VERSION 5.7 ;
  NOWIREEXTENSIONATPIN ON ;
  DIVIDERCHAR "/" ;
  BUSBITCHARS "[]" ;
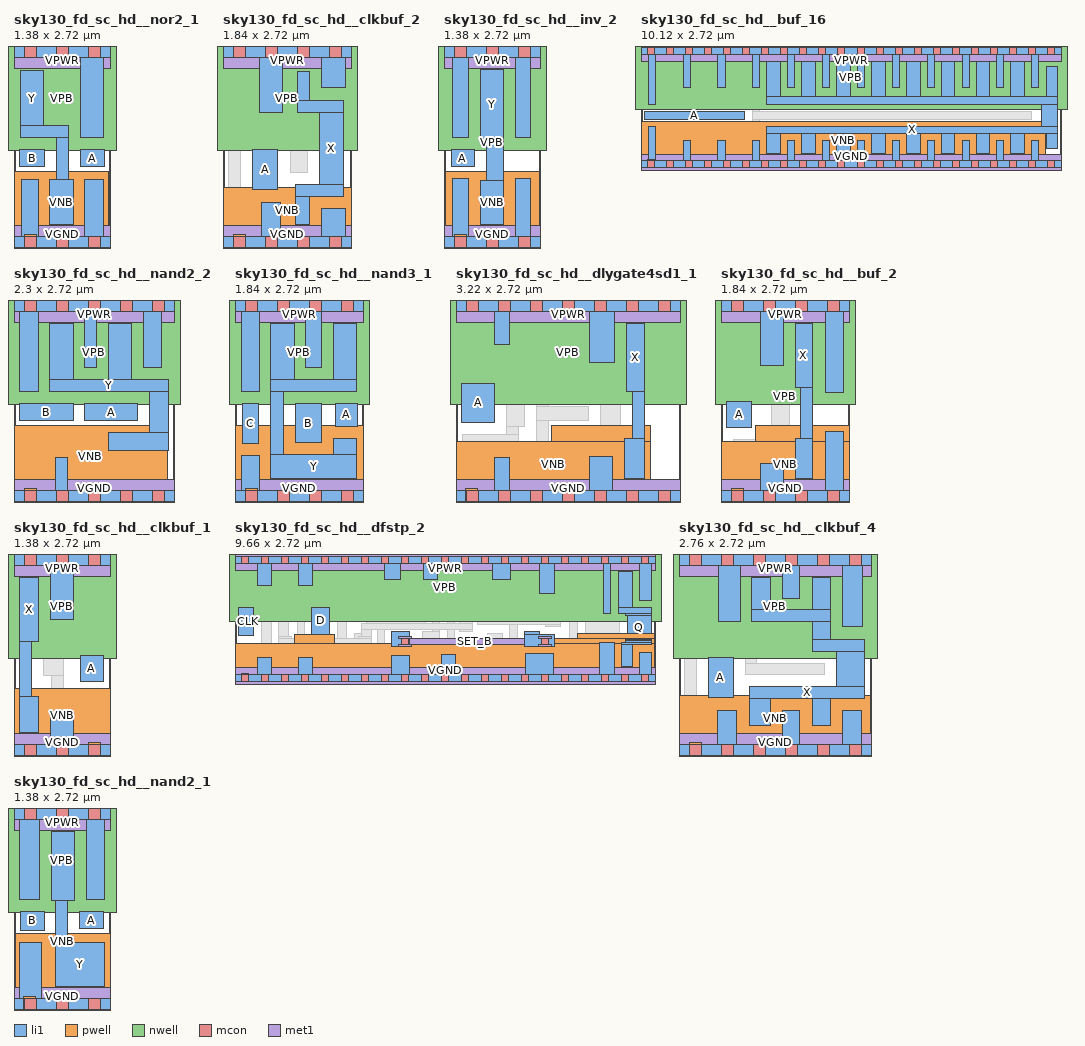
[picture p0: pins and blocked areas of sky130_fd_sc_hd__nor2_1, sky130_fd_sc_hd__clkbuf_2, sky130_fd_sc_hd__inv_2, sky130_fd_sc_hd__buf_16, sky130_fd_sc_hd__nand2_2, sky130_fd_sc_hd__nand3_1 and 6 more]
MACRO sky130_fd_sc_hd__nor2_1
  CLASS BLOCK ;
  FOREIGN sky130_fd_sc_hd__nor2_1 ;
  ORIGIN 0.000 0.000 ;
  SIZE 1.380 BY 2.720 ;
  PIN B
    ANTENNAGATEAREA 0.247500 ;
    PORT
      LAYER li1 ;
        RECT 0.085 1.075 0.435 1.325 ;
    END
  END B
  PIN Y
    ANTENNADIFFAREA 0.435500 ;
    PORT
      LAYER li1 ;
        RECT 0.095 1.665 0.425 2.450 ;
        RECT 0.095 1.495 0.775 1.665 ;
        RECT 0.605 0.895 0.775 1.495 ;
        RECT 0.515 0.255 0.845 0.895 ;
    END
  END Y
  PIN A
    ANTENNAGATEAREA 0.247500 ;
    PORT
      LAYER li1 ;
        RECT 0.945 1.075 1.295 1.325 ;
    END
  END A
  PIN VNB
    PORT
      LAYER pwell ;
        RECT 0.005 0.105 1.355 1.015 ;
        RECT 0.150 -0.085 0.320 0.105 ;
    END
  END VNB
  PIN VPB
    PORT
      LAYER nwell ;
        RECT -0.190 1.305 1.570 2.910 ;
    END
  END VPB
  PIN VGND
    USE GROUND ;
    PORT
      LAYER li1 ;
        RECT 0.105 0.085 0.345 0.895 ;
        RECT 1.015 0.085 1.285 0.895 ;
        RECT 0.000 -0.085 1.380 0.085 ;
      LAYER mcon ;
        RECT 0.145 -0.085 0.315 0.085 ;
        RECT 0.605 -0.085 0.775 0.085 ;
        RECT 1.065 -0.085 1.235 0.085 ;
      LAYER met1 ;
        RECT 0.000 -0.240 1.380 0.240 ;
    END
  END VGND
  PIN VPWR
    USE POWER ;
    PORT
      LAYER li1 ;
        RECT 0.000 2.635 1.380 2.805 ;
        RECT 0.955 1.495 1.285 2.635 ;
      LAYER mcon ;
        RECT 0.145 2.635 0.315 2.805 ;
        RECT 0.605 2.635 0.775 2.805 ;
        RECT 1.065 2.635 1.235 2.805 ;
      LAYER met1 ;
        RECT 0.000 2.480 1.380 2.960 ;
    END
  END VPWR
END sky130_fd_sc_hd__nor2_1
MACRO sky130_fd_sc_hd__clkbuf_2
  CLASS BLOCK ;
  FOREIGN sky130_fd_sc_hd__clkbuf_2 ;
  ORIGIN 0.000 0.000 ;
  SIZE 1.840 BY 2.720 ;
  PIN A
    ANTENNAGATEAREA 0.213000 ;
    PORT
      LAYER li1 ;
        RECT 0.425 0.745 0.785 1.325 ;
    END
  END A
  PIN X
    ANTENNADIFFAREA 0.383400 ;
    PORT
      LAYER li1 ;
        RECT 1.060 2.030 1.245 2.435 ;
        RECT 1.060 1.855 1.725 2.030 ;
        RECT 1.385 0.825 1.725 1.855 ;
        RECT 1.040 0.655 1.725 0.825 ;
        RECT 1.040 0.255 1.245 0.655 ;
    END
  END X
  PIN VNB
    PORT
      LAYER pwell ;
        RECT 0.005 0.105 1.835 0.785 ;
        RECT 0.145 -0.085 0.315 0.105 ;
    END
  END VNB
  PIN VPB
    PORT
      LAYER nwell ;
        RECT -0.190 1.305 2.030 2.910 ;
    END
  END VPB
  PIN VGND
    USE GROUND ;
    PORT
      LAYER li1 ;
        RECT 0.555 0.085 0.830 0.565 ;
        RECT 1.415 0.085 1.750 0.485 ;
        RECT 0.000 -0.085 1.840 0.085 ;
      LAYER mcon ;
        RECT 0.145 -0.085 0.315 0.085 ;
        RECT 0.605 -0.085 0.775 0.085 ;
        RECT 1.065 -0.085 1.235 0.085 ;
        RECT 1.525 -0.085 1.695 0.085 ;
      LAYER met1 ;
        RECT 0.000 -0.240 1.840 0.240 ;
    END
  END VGND
  PIN VPWR
    USE POWER ;
    PORT
      LAYER li1 ;
        RECT 0.000 2.635 1.840 2.805 ;
        RECT 0.525 1.855 0.855 2.635 ;
        RECT 1.415 2.210 1.750 2.635 ;
      LAYER mcon ;
        RECT 0.145 2.635 0.315 2.805 ;
        RECT 0.605 2.635 0.775 2.805 ;
        RECT 1.065 2.635 1.235 2.805 ;
        RECT 1.525 2.635 1.695 2.805 ;
      LAYER met1 ;
        RECT 0.000 2.480 1.840 2.960 ;
    END
  END VPWR
  OBS
      LAYER li1 ;
        RECT 0.085 1.665 0.355 2.435 ;
        RECT 0.085 1.495 1.215 1.665 ;
        RECT 0.085 0.585 0.255 1.495 ;
        RECT 0.965 0.995 1.215 1.495 ;
        RECT 0.085 0.255 0.345 0.585 ;
  END
END sky130_fd_sc_hd__clkbuf_2
MACRO sky130_fd_sc_hd__inv_2
  CLASS BLOCK ;
  FOREIGN sky130_fd_sc_hd__inv_2 ;
  ORIGIN 0.000 0.000 ;
  SIZE 1.380 BY 2.720 ;
  PIN A
    ANTENNAGATEAREA 0.495000 ;
    PORT
      LAYER li1 ;
        RECT 0.105 1.075 0.435 1.325 ;
    END
  END A
  PIN Y
    ANTENNADIFFAREA 0.445500 ;
    PORT
      LAYER li1 ;
        RECT 0.525 1.485 0.855 2.465 ;
        RECT 0.605 0.885 0.855 1.485 ;
        RECT 0.525 0.255 0.855 0.885 ;
    END
  END Y
  PIN VNB
    PORT
      LAYER pwell ;
        RECT 0.015 0.105 1.365 1.015 ;
        RECT 0.145 -0.085 0.315 0.105 ;
    END
  END VNB
  PIN VPB
    PORT
      LAYER nwell ;
        RECT -0.190 1.305 1.570 2.910 ;
    END
  END VPB
  PIN VPWR
    USE POWER ;
    PORT
      LAYER li1 ;
        RECT 0.000 2.635 1.380 2.805 ;
        RECT 0.125 1.495 0.355 2.635 ;
        RECT 1.025 1.495 1.235 2.635 ;
      LAYER mcon ;
        RECT 0.145 2.635 0.315 2.805 ;
        RECT 0.605 2.635 0.775 2.805 ;
        RECT 1.065 2.635 1.235 2.805 ;
      LAYER met1 ;
        RECT 0.000 2.480 1.380 2.960 ;
    END
  END VPWR
  PIN VGND
    USE GROUND ;
    PORT
      LAYER li1 ;
        RECT 0.125 0.085 0.355 0.905 ;
        RECT 1.025 0.085 1.235 0.905 ;
        RECT 0.000 -0.085 1.380 0.085 ;
      LAYER mcon ;
        RECT 0.145 -0.085 0.315 0.085 ;
        RECT 0.605 -0.085 0.775 0.085 ;
        RECT 1.065 -0.085 1.235 0.085 ;
      LAYER met1 ;
        RECT 0.000 -0.240 1.380 0.240 ;
    END
  END VGND
END sky130_fd_sc_hd__inv_2
MACRO sky130_fd_sc_hd__buf_16
  CLASS BLOCK ;
  FOREIGN sky130_fd_sc_hd__buf_16 ;
  ORIGIN 0.000 0.000 ;
  SIZE 10.120 BY 2.720 ;
  PIN A
    ANTENNAGATEAREA 1.485000 ;
    PORT
      LAYER li1 ;
        RECT 0.085 1.075 2.485 1.275 ;
    END
  END A
  PIN X
    ANTENNADIFFAREA 3.564000 ;
    PORT
      LAYER li1 ;
        RECT 3.035 1.615 3.365 2.465 ;
        RECT 3.875 1.615 4.205 2.465 ;
        RECT 4.715 1.615 5.045 2.465 ;
        RECT 5.555 1.615 5.885 2.465 ;
        RECT 6.395 1.615 6.725 2.465 ;
        RECT 7.235 1.615 7.565 2.465 ;
        RECT 8.075 1.615 8.405 2.465 ;
        RECT 8.915 1.615 9.245 2.465 ;
        RECT 9.760 1.615 10.035 2.360 ;
        RECT 3.035 1.445 10.035 1.615 ;
        RECT 9.655 0.905 10.035 1.445 ;
        RECT 3.035 0.735 10.035 0.905 ;
        RECT 3.035 0.260 3.365 0.735 ;
        RECT 3.875 0.260 4.205 0.735 ;
        RECT 4.715 0.260 5.045 0.735 ;
        RECT 5.555 0.260 5.885 0.735 ;
        RECT 6.395 0.260 6.725 0.735 ;
        RECT 7.235 0.260 7.565 0.735 ;
        RECT 8.075 0.260 8.405 0.735 ;
        RECT 8.915 0.260 9.245 0.735 ;
        RECT 9.760 0.365 10.035 0.735 ;
        RECT 3.035 0.255 3.285 0.260 ;
        RECT 3.955 0.255 4.125 0.260 ;
        RECT 4.795 0.255 4.965 0.260 ;
    END
  END X
  PIN VNB
    PORT
      LAYER pwell ;
        RECT 0.005 0.105 9.755 1.015 ;
        RECT 0.150 -0.085 0.320 0.105 ;
    END
  END VNB
  PIN VPB
    PORT
      LAYER nwell ;
        RECT -0.190 1.305 10.310 2.910 ;
    END
  END VPB
  PIN VGND
    USE GROUND ;
    PORT
      LAYER li1 ;
        RECT 0.175 0.085 0.345 0.905 ;
        RECT 1.015 0.085 1.185 0.565 ;
        RECT 1.855 0.085 2.025 0.565 ;
        RECT 2.695 0.085 2.865 0.565 ;
        RECT 3.535 0.085 3.705 0.565 ;
        RECT 4.375 0.085 4.545 0.565 ;
        RECT 5.215 0.085 5.385 0.565 ;
        RECT 6.055 0.085 6.225 0.565 ;
        RECT 6.895 0.085 7.065 0.565 ;
        RECT 7.735 0.085 7.905 0.565 ;
        RECT 8.575 0.085 8.745 0.565 ;
        RECT 9.415 0.085 9.585 0.565 ;
        RECT 0.000 -0.085 10.120 0.085 ;
      LAYER mcon ;
        RECT 0.145 -0.085 0.315 0.085 ;
        RECT 0.605 -0.085 0.775 0.085 ;
        RECT 1.065 -0.085 1.235 0.085 ;
        RECT 1.525 -0.085 1.695 0.085 ;
        RECT 1.985 -0.085 2.155 0.085 ;
        RECT 2.445 -0.085 2.615 0.085 ;
        RECT 2.905 -0.085 3.075 0.085 ;
        RECT 3.365 -0.085 3.535 0.085 ;
        RECT 3.825 -0.085 3.995 0.085 ;
        RECT 4.285 -0.085 4.455 0.085 ;
        RECT 4.745 -0.085 4.915 0.085 ;
        RECT 5.205 -0.085 5.375 0.085 ;
        RECT 5.665 -0.085 5.835 0.085 ;
        RECT 6.125 -0.085 6.295 0.085 ;
        RECT 6.585 -0.085 6.755 0.085 ;
        RECT 7.045 -0.085 7.215 0.085 ;
        RECT 7.505 -0.085 7.675 0.085 ;
        RECT 7.965 -0.085 8.135 0.085 ;
        RECT 8.425 -0.085 8.595 0.085 ;
        RECT 8.885 -0.085 9.055 0.085 ;
        RECT 9.345 -0.085 9.515 0.085 ;
        RECT 9.805 -0.085 9.975 0.085 ;
      LAYER met1 ;
        RECT 0.000 -0.240 10.120 0.240 ;
    END
  END VGND
  PIN VPWR
    USE POWER ;
    PORT
      LAYER li1 ;
        RECT 0.000 2.635 10.120 2.805 ;
        RECT 0.175 1.445 0.345 2.635 ;
        RECT 1.015 1.835 1.185 2.635 ;
        RECT 1.855 1.835 2.025 2.635 ;
        RECT 2.695 1.835 2.865 2.635 ;
        RECT 3.535 1.835 3.705 2.635 ;
        RECT 4.375 1.835 4.545 2.635 ;
        RECT 5.215 1.835 5.385 2.635 ;
        RECT 6.055 1.835 6.225 2.635 ;
        RECT 6.895 1.835 7.065 2.635 ;
        RECT 7.735 1.835 7.905 2.635 ;
        RECT 8.575 1.835 8.745 2.635 ;
        RECT 9.415 1.835 9.585 2.635 ;
      LAYER mcon ;
        RECT 0.145 2.635 0.315 2.805 ;
        RECT 0.605 2.635 0.775 2.805 ;
        RECT 1.065 2.635 1.235 2.805 ;
        RECT 1.525 2.635 1.695 2.805 ;
        RECT 1.985 2.635 2.155 2.805 ;
        RECT 2.445 2.635 2.615 2.805 ;
        RECT 2.905 2.635 3.075 2.805 ;
        RECT 3.365 2.635 3.535 2.805 ;
        RECT 3.825 2.635 3.995 2.805 ;
        RECT 4.285 2.635 4.455 2.805 ;
        RECT 4.745 2.635 4.915 2.805 ;
        RECT 5.205 2.635 5.375 2.805 ;
        RECT 5.665 2.635 5.835 2.805 ;
        RECT 6.125 2.635 6.295 2.805 ;
        RECT 6.585 2.635 6.755 2.805 ;
        RECT 7.045 2.635 7.215 2.805 ;
        RECT 7.505 2.635 7.675 2.805 ;
        RECT 7.965 2.635 8.135 2.805 ;
        RECT 8.425 2.635 8.595 2.805 ;
        RECT 8.885 2.635 9.055 2.805 ;
        RECT 9.345 2.635 9.515 2.805 ;
        RECT 9.805 2.635 9.975 2.805 ;
      LAYER met1 ;
        RECT 0.000 2.480 10.120 2.960 ;
    END
  END VPWR
  OBS
      LAYER li1 ;
        RECT 0.515 1.615 0.845 2.465 ;
        RECT 1.355 1.615 1.685 2.465 ;
        RECT 2.195 1.615 2.525 2.465 ;
        RECT 0.515 1.445 2.865 1.615 ;
        RECT 2.690 1.275 2.865 1.445 ;
        RECT 2.690 1.075 9.410 1.275 ;
        RECT 2.690 0.905 2.865 1.075 ;
        RECT 0.515 0.735 2.865 0.905 ;
        RECT 0.515 0.260 0.845 0.735 ;
        RECT 1.355 0.260 1.685 0.735 ;
        RECT 2.195 0.260 2.525 0.735 ;
  END
END sky130_fd_sc_hd__buf_16
MACRO VIA_via4_1600x1600
  CLASS BLOCK ;
  FOREIGN VIA_via4_1600x1600 ;
  ORIGIN 0.800 0.800 ;
  SIZE 1.600 BY 1.600 ;
  OBS
      LAYER met4 ;
        RECT -0.800 -0.800 0.800 0.800 ;
      LAYER via4 ;
        RECT -0.590 -0.590 0.590 0.590 ;
      LAYER met5 ;
        RECT -0.800 -0.800 0.800 0.800 ;
  END
END VIA_via4_1600x1600
MACRO VIA_via4_4200x1600
  CLASS BLOCK ;
  FOREIGN VIA_via4_4200x1600 ;
  ORIGIN 2.100 0.800 ;
  SIZE 4.200 BY 1.600 ;
  OBS
      LAYER met4 ;
        RECT -2.100 -0.800 2.100 0.800 ;
      LAYER via4 ;
        RECT -1.390 -0.590 -0.210 0.590 ;
        RECT 0.210 -0.590 1.390 0.590 ;
      LAYER met5 ;
        RECT -2.100 -0.800 2.100 0.800 ;
  END
END VIA_via4_4200x1600
MACRO VIA_M2M3_PR
  CLASS BLOCK ;
  FOREIGN VIA_M2M3_PR ;
  ORIGIN 0.165 0.185 ;
  SIZE 0.330 BY 0.370 ;
  OBS
      LAYER met2 ;
        RECT -0.140 -0.185 0.140 0.185 ;
      LAYER via2 ;
        RECT -0.140 -0.140 0.140 0.140 ;
      LAYER met3 ;
        RECT -0.165 -0.165 0.165 0.165 ;
  END
END VIA_M2M3_PR
MACRO sky130_fd_sc_hd__nand2_2
  CLASS BLOCK ;
  FOREIGN sky130_fd_sc_hd__nand2_2 ;
  ORIGIN 0.000 0.000 ;
  SIZE 2.300 BY 2.720 ;
  PIN Y
    ANTENNADIFFAREA 0.715500 ;
    PORT
      LAYER li1 ;
        RECT 0.515 1.665 0.845 2.465 ;
        RECT 1.355 1.665 1.685 2.465 ;
        RECT 0.515 1.495 2.215 1.665 ;
        RECT 1.935 0.905 2.215 1.495 ;
        RECT 1.355 0.655 2.215 0.905 ;
    END
  END Y
  PIN A
    ANTENNAGATEAREA 0.495000 ;
    PORT
      LAYER li1 ;
        RECT 1.015 1.075 1.765 1.325 ;
    END
  END A
  PIN B
    ANTENNAGATEAREA 0.495000 ;
    PORT
      LAYER li1 ;
        RECT 0.085 1.075 0.845 1.325 ;
    END
  END B
  PIN VNB
    PORT
      LAYER pwell ;
        RECT 0.005 0.105 2.195 1.015 ;
        RECT 0.150 -0.085 0.320 0.105 ;
    END
  END VNB
  PIN VPB
    PORT
      LAYER nwell ;
        RECT -0.190 1.305 2.490 2.910 ;
    END
  END VPB
  PIN VGND
    USE GROUND ;
    PORT
      LAYER li1 ;
        RECT 0.595 0.085 0.765 0.545 ;
        RECT 0.000 -0.085 2.300 0.085 ;
      LAYER mcon ;
        RECT 0.145 -0.085 0.315 0.085 ;
        RECT 0.605 -0.085 0.775 0.085 ;
        RECT 1.065 -0.085 1.235 0.085 ;
        RECT 1.525 -0.085 1.695 0.085 ;
        RECT 1.985 -0.085 2.155 0.085 ;
      LAYER met1 ;
        RECT 0.000 -0.240 2.300 0.240 ;
    END
  END VGND
  PIN VPWR
    USE POWER ;
    PORT
      LAYER li1 ;
        RECT 0.000 2.635 2.300 2.805 ;
        RECT 0.085 1.495 0.345 2.635 ;
        RECT 1.015 1.835 1.185 2.635 ;
        RECT 1.855 1.835 2.110 2.635 ;
      LAYER mcon ;
        RECT 0.145 2.635 0.315 2.805 ;
        RECT 0.605 2.635 0.775 2.805 ;
        RECT 1.065 2.635 1.235 2.805 ;
        RECT 1.525 2.635 1.695 2.805 ;
        RECT 1.985 2.635 2.155 2.805 ;
      LAYER met1 ;
        RECT 0.000 2.480 2.300 2.960 ;
    END
  END VPWR
  OBS
      LAYER li1 ;
        RECT 0.085 0.715 1.185 0.885 ;
        RECT 0.085 0.255 0.425 0.715 ;
        RECT 0.935 0.465 1.185 0.715 ;
        RECT 1.775 0.465 2.105 0.485 ;
        RECT 0.935 0.255 2.105 0.465 ;
  END
END sky130_fd_sc_hd__nand2_2
MACRO sky130_fd_sc_hd__nand3_1
  CLASS BLOCK ;
  FOREIGN sky130_fd_sc_hd__nand3_1 ;
  ORIGIN 0.000 0.000 ;
  SIZE 1.840 BY 2.720 ;
  PIN Y
    ANTENNADIFFAREA 0.699000 ;
    PORT
      LAYER li1 ;
        RECT 0.515 1.665 0.845 2.465 ;
        RECT 1.415 1.665 1.745 2.465 ;
        RECT 0.515 1.495 1.745 1.665 ;
        RECT 0.515 0.595 0.695 1.495 ;
        RECT 1.415 0.595 1.745 0.825 ;
        RECT 0.515 0.255 1.745 0.595 ;
    END
  END Y
  PIN A
    ANTENNAGATEAREA 0.247500 ;
    PORT
      LAYER li1 ;
        RECT 1.445 0.995 1.755 1.325 ;
    END
  END A
  PIN C
    ANTENNAGATEAREA 0.247500 ;
    PORT
      LAYER li1 ;
        RECT 0.110 0.745 0.330 1.325 ;
    END
  END C
  PIN B
    ANTENNAGATEAREA 0.247500 ;
    PORT
      LAYER li1 ;
        RECT 0.865 0.765 1.240 1.325 ;
    END
  END B
  PIN VNB
    PORT
      LAYER pwell ;
        RECT 0.005 0.105 1.835 1.015 ;
        RECT 0.150 -0.085 0.320 0.105 ;
    END
  END VNB
  PIN VPB
    PORT
      LAYER nwell ;
        RECT -0.190 1.305 2.030 2.910 ;
    END
  END VPB
  PIN VGND
    USE GROUND ;
    PORT
      LAYER li1 ;
        RECT 0.090 0.085 0.345 0.575 ;
        RECT 0.000 -0.085 1.840 0.085 ;
      LAYER mcon ;
        RECT 0.145 -0.085 0.315 0.085 ;
        RECT 0.605 -0.085 0.775 0.085 ;
        RECT 1.065 -0.085 1.235 0.085 ;
        RECT 1.525 -0.085 1.695 0.085 ;
      LAYER met1 ;
        RECT 0.000 -0.240 1.840 0.240 ;
    END
  END VGND
  PIN VPWR
    USE POWER ;
    PORT
      LAYER li1 ;
        RECT 0.000 2.635 1.840 2.805 ;
        RECT 0.090 1.495 0.345 2.635 ;
        RECT 1.015 1.835 1.245 2.635 ;
      LAYER mcon ;
        RECT 0.145 2.635 0.315 2.805 ;
        RECT 0.605 2.635 0.775 2.805 ;
        RECT 1.065 2.635 1.235 2.805 ;
        RECT 1.525 2.635 1.695 2.805 ;
      LAYER met1 ;
        RECT 0.000 2.480 1.840 2.960 ;
    END
  END VPWR
END sky130_fd_sc_hd__nand3_1
MACRO sky130_fd_sc_hd__dlygate4sd1_1
  CLASS BLOCK ;
  FOREIGN sky130_fd_sc_hd__dlygate4sd1_1 ;
  ORIGIN 0.000 0.000 ;
  SIZE 3.220 BY 2.720 ;
  PIN A
    ANTENNAGATEAREA 0.126000 ;
    PORT
      LAYER li1 ;
        RECT 0.085 1.055 0.555 1.615 ;
    END
  END A
  PIN X
    ANTENNADIFFAREA 0.429000 ;
    PORT
      LAYER li1 ;
        RECT 2.440 1.495 2.700 2.465 ;
        RECT 2.530 0.825 2.700 1.495 ;
        RECT 2.410 0.255 2.700 0.825 ;
    END
  END X
  PIN VNB
    PORT
      LAYER pwell ;
        RECT 1.365 0.785 2.780 1.015 ;
        RECT 0.005 0.105 2.780 0.785 ;
        RECT 0.140 -0.085 0.310 0.105 ;
    END
  END VNB
  PIN VPB
    PORT
      LAYER nwell ;
        RECT -0.190 1.305 3.410 2.910 ;
    END
  END VPB
  PIN VPWR
    USE POWER ;
    PORT
      LAYER li1 ;
        RECT 0.000 2.635 3.220 2.805 ;
        RECT 0.550 2.175 0.765 2.635 ;
        RECT 1.910 1.915 2.270 2.635 ;
      LAYER mcon ;
        RECT 0.145 2.635 0.315 2.805 ;
        RECT 0.605 2.635 0.775 2.805 ;
        RECT 1.065 2.635 1.235 2.805 ;
        RECT 1.525 2.635 1.695 2.805 ;
        RECT 1.985 2.635 2.155 2.805 ;
        RECT 2.445 2.635 2.615 2.805 ;
        RECT 2.905 2.635 3.075 2.805 ;
      LAYER met1 ;
        RECT 0.000 2.480 3.220 2.960 ;
    END
  END VPWR
  PIN VGND
    USE GROUND ;
    PORT
      LAYER li1 ;
        RECT 0.550 0.085 0.765 0.545 ;
        RECT 1.910 0.085 2.240 0.565 ;
        RECT 0.000 -0.085 3.220 0.085 ;
      LAYER mcon ;
        RECT 0.145 -0.085 0.315 0.085 ;
        RECT 0.605 -0.085 0.775 0.085 ;
        RECT 1.065 -0.085 1.235 0.085 ;
        RECT 1.525 -0.085 1.695 0.085 ;
        RECT 1.985 -0.085 2.155 0.085 ;
        RECT 2.445 -0.085 2.615 0.085 ;
        RECT 2.905 -0.085 3.075 0.085 ;
      LAYER met1 ;
        RECT 0.000 -0.240 3.220 0.240 ;
    END
  END VGND
  OBS
      LAYER li1 ;
        RECT 0.085 2.005 0.380 2.465 ;
        RECT 0.935 2.175 1.320 2.465 ;
        RECT 0.085 1.785 0.895 2.005 ;
        RECT 0.725 1.325 0.895 1.785 ;
        RECT 0.725 0.995 0.980 1.325 ;
        RECT 1.150 1.275 1.320 2.175 ;
        RECT 1.515 1.745 1.740 2.430 ;
        RECT 1.515 1.575 2.240 1.745 ;
        RECT 2.070 1.325 2.240 1.575 ;
        RECT 1.150 1.075 1.900 1.275 ;
        RECT 0.725 0.885 0.895 0.995 ;
        RECT 0.095 0.715 0.895 0.885 ;
        RECT 0.095 0.255 0.380 0.715 ;
        RECT 1.150 0.545 1.320 1.075 ;
        RECT 2.070 0.995 2.360 1.325 ;
        RECT 2.070 0.905 2.240 0.995 ;
        RECT 0.935 0.255 1.320 0.545 ;
        RECT 1.515 0.735 2.240 0.905 ;
        RECT 1.515 0.255 1.740 0.735 ;
  END
END sky130_fd_sc_hd__dlygate4sd1_1
MACRO sky130_fd_sc_hd__buf_2
  CLASS BLOCK ;
  FOREIGN sky130_fd_sc_hd__buf_2 ;
  ORIGIN 0.000 0.000 ;
  SIZE 1.840 BY 2.720 ;
  PIN VPWR
    USE POWER ;
    PORT
      LAYER li1 ;
        RECT 0.000 2.635 1.840 2.805 ;
        RECT 0.560 1.875 0.890 2.635 ;
        RECT 1.490 1.485 1.750 2.635 ;
      LAYER mcon ;
        RECT 0.145 2.635 0.315 2.805 ;
        RECT 0.605 2.635 0.775 2.805 ;
        RECT 1.065 2.635 1.235 2.805 ;
        RECT 1.525 2.635 1.695 2.805 ;
      LAYER met1 ;
        RECT 0.000 2.480 1.840 2.960 ;
    END
  END VPWR
  PIN VGND
    USE GROUND ;
    PORT
      LAYER li1 ;
        RECT 0.560 0.085 0.890 0.465 ;
        RECT 1.490 0.085 1.750 0.925 ;
        RECT 0.000 -0.085 1.840 0.085 ;
      LAYER mcon ;
        RECT 0.145 -0.085 0.315 0.085 ;
        RECT 0.605 -0.085 0.775 0.085 ;
        RECT 1.065 -0.085 1.235 0.085 ;
        RECT 1.525 -0.085 1.695 0.085 ;
      LAYER met1 ;
        RECT 0.000 -0.240 1.840 0.240 ;
    END
  END VGND
  PIN X
    ANTENNADIFFAREA 0.445500 ;
    PORT
      LAYER li1 ;
        RECT 1.060 1.560 1.315 2.465 ;
        RECT 1.145 0.830 1.315 1.560 ;
        RECT 1.060 0.255 1.315 0.830 ;
    END
  END X
  PIN A
    ANTENNAGATEAREA 0.159000 ;
    PORT
      LAYER li1 ;
        RECT 0.085 0.985 0.440 1.355 ;
    END
  END A
  PIN VNB
    PORT
      LAYER pwell ;
        RECT 0.490 0.785 1.835 1.015 ;
        RECT 0.005 0.105 1.835 0.785 ;
        RECT 0.145 -0.085 0.315 0.105 ;
    END
  END VNB
  PIN VPB
    PORT
      LAYER nwell ;
        RECT -0.190 1.305 2.030 2.910 ;
    END
  END VPB
  OBS
      LAYER li1 ;
        RECT 0.175 1.705 0.345 2.465 ;
        RECT 0.175 1.535 0.890 1.705 ;
        RECT 0.720 1.325 0.890 1.535 ;
        RECT 0.720 0.995 0.975 1.325 ;
        RECT 0.720 0.805 0.890 0.995 ;
        RECT 0.175 0.635 0.890 0.805 ;
        RECT 0.175 0.255 0.345 0.635 ;
  END
END sky130_fd_sc_hd__buf_2
MACRO sky130_fd_sc_hd__clkbuf_1
  CLASS BLOCK ;
  FOREIGN sky130_fd_sc_hd__clkbuf_1 ;
  ORIGIN 0.000 0.000 ;
  SIZE 1.380 BY 2.720 ;
  PIN X
    ANTENNADIFFAREA 0.340600 ;
    PORT
      LAYER li1 ;
        RECT 0.085 1.560 0.355 2.465 ;
        RECT 0.085 0.760 0.255 1.560 ;
        RECT 0.085 0.255 0.345 0.760 ;
    END
  END X
  PIN A
    ANTENNAGATEAREA 0.196500 ;
    PORT
      LAYER li1 ;
        RECT 0.945 0.985 1.275 1.355 ;
    END
  END A
  PIN VNB
    PORT
      LAYER pwell ;
        RECT 0.005 0.105 1.375 0.885 ;
        RECT 1.065 -0.085 1.235 0.105 ;
    END
  END VNB
  PIN VPB
    PORT
      LAYER nwell ;
        RECT -0.190 1.305 1.570 2.910 ;
    END
  END VPB
  PIN VGND
    USE GROUND ;
    PORT
      LAYER li1 ;
        RECT 0.525 0.085 0.855 0.465 ;
        RECT 0.000 -0.085 1.380 0.085 ;
      LAYER mcon ;
        RECT 0.145 -0.085 0.315 0.085 ;
        RECT 0.605 -0.085 0.775 0.085 ;
        RECT 1.065 -0.085 1.235 0.085 ;
      LAYER met1 ;
        RECT 0.000 -0.240 1.380 0.240 ;
    END
  END VGND
  PIN VPWR
    USE POWER ;
    PORT
      LAYER li1 ;
        RECT 0.000 2.635 1.380 2.805 ;
        RECT 0.525 1.875 0.855 2.635 ;
      LAYER mcon ;
        RECT 0.145 2.635 0.315 2.805 ;
        RECT 0.605 2.635 0.775 2.805 ;
        RECT 1.065 2.635 1.235 2.805 ;
      LAYER met1 ;
        RECT 0.000 2.480 1.380 2.960 ;
    END
  END VPWR
  OBS
      LAYER li1 ;
        RECT 1.035 1.705 1.205 2.465 ;
        RECT 0.540 1.535 1.205 1.705 ;
        RECT 0.540 1.390 0.710 1.535 ;
        RECT 0.425 1.060 0.710 1.390 ;
        RECT 0.540 0.805 0.710 1.060 ;
        RECT 0.540 0.635 1.205 0.805 ;
        RECT 1.035 0.255 1.205 0.635 ;
  END
END sky130_fd_sc_hd__clkbuf_1
MACRO sky130_fd_sc_hd__dfstp_2
  CLASS BLOCK ;
  FOREIGN sky130_fd_sc_hd__dfstp_2 ;
  ORIGIN 0.000 0.000 ;
  SIZE 9.660 BY 2.720 ;
  PIN Q
    ANTENNADIFFAREA 0.445500 ;
    PORT
      LAYER li1 ;
        RECT 8.810 1.615 9.140 2.460 ;
        RECT 8.810 1.495 9.575 1.615 ;
        RECT 8.975 1.445 9.575 1.495 ;
        RECT 9.020 0.895 9.575 1.445 ;
        RECT 8.990 0.855 9.575 0.895 ;
        RECT 8.975 0.825 9.575 0.855 ;
        RECT 8.890 0.765 9.575 0.825 ;
        RECT 8.890 0.265 9.135 0.765 ;
    END
  END Q
  PIN D
    ANTENNAGATEAREA 0.222000 ;
    PORT
      LAYER li1 ;
        RECT 1.770 1.005 2.180 1.625 ;
    END
  END D
  PIN VPWR
    USE POWER ;
    PORT
      LAYER li1 ;
        RECT 0.000 2.635 9.660 2.805 ;
        RECT 0.515 2.135 0.845 2.635 ;
        RECT 1.455 2.135 1.785 2.635 ;
        RECT 3.430 2.255 3.810 2.635 ;
        RECT 4.330 2.255 4.660 2.635 ;
        RECT 5.920 2.255 6.340 2.635 ;
        RECT 7.010 1.945 7.340 2.635 ;
        RECT 8.470 1.495 8.640 2.635 ;
        RECT 9.310 1.785 9.575 2.635 ;
      LAYER mcon ;
        RECT 0.145 2.635 0.315 2.805 ;
        RECT 0.605 2.635 0.775 2.805 ;
        RECT 1.065 2.635 1.235 2.805 ;
        RECT 1.525 2.635 1.695 2.805 ;
        RECT 1.985 2.635 2.155 2.805 ;
        RECT 2.445 2.635 2.615 2.805 ;
        RECT 2.905 2.635 3.075 2.805 ;
        RECT 3.365 2.635 3.535 2.805 ;
        RECT 3.825 2.635 3.995 2.805 ;
        RECT 4.285 2.635 4.455 2.805 ;
        RECT 4.745 2.635 4.915 2.805 ;
        RECT 5.205 2.635 5.375 2.805 ;
        RECT 5.665 2.635 5.835 2.805 ;
        RECT 6.125 2.635 6.295 2.805 ;
        RECT 6.585 2.635 6.755 2.805 ;
        RECT 7.045 2.635 7.215 2.805 ;
        RECT 7.505 2.635 7.675 2.805 ;
        RECT 7.965 2.635 8.135 2.805 ;
        RECT 8.425 2.635 8.595 2.805 ;
        RECT 8.885 2.635 9.055 2.805 ;
        RECT 9.345 2.635 9.515 2.805 ;
      LAYER met1 ;
        RECT 0.000 2.480 9.660 2.960 ;
    END
  END VPWR
  PIN SET_B
    ANTENNAGATEAREA 0.252000 ;
    PORT
      LAYER li1 ;
        RECT 3.610 0.735 4.020 1.065 ;
        RECT 6.660 1.005 7.010 1.065 ;
        RECT 6.660 0.735 7.340 1.005 ;
      LAYER mcon ;
        RECT 3.825 0.765 3.995 0.935 ;
        RECT 7.045 0.765 7.215 0.935 ;
      LAYER met1 ;
        RECT 3.765 0.920 4.055 0.965 ;
        RECT 6.985 0.920 7.275 0.965 ;
        RECT 3.765 0.780 7.275 0.920 ;
        RECT 3.765 0.735 4.055 0.780 ;
        RECT 6.985 0.735 7.275 0.780 ;
    END
  END SET_B
  PIN CLK
    ANTENNAGATEAREA 0.159000 ;
    PORT
      LAYER li1 ;
        RECT 0.085 0.975 0.435 1.625 ;
    END
  END CLK
  PIN VGND
    USE GROUND ;
    PORT
      LAYER li1 ;
        RECT 0.515 0.085 0.845 0.465 ;
        RECT 1.455 0.085 1.785 0.465 ;
        RECT 3.610 0.085 4.020 0.525 ;
        RECT 4.760 0.085 5.080 0.545 ;
        RECT 6.690 0.085 7.330 0.565 ;
        RECT 8.390 0.085 8.720 0.825 ;
        RECT 9.305 0.085 9.575 0.595 ;
        RECT 0.000 -0.085 9.660 0.085 ;
      LAYER mcon ;
        RECT 0.145 -0.085 0.315 0.085 ;
        RECT 0.605 -0.085 0.775 0.085 ;
        RECT 1.065 -0.085 1.235 0.085 ;
        RECT 1.525 -0.085 1.695 0.085 ;
        RECT 1.985 -0.085 2.155 0.085 ;
        RECT 2.445 -0.085 2.615 0.085 ;
        RECT 2.905 -0.085 3.075 0.085 ;
        RECT 3.365 -0.085 3.535 0.085 ;
        RECT 3.825 -0.085 3.995 0.085 ;
        RECT 4.285 -0.085 4.455 0.085 ;
        RECT 4.745 -0.085 4.915 0.085 ;
        RECT 5.205 -0.085 5.375 0.085 ;
        RECT 5.665 -0.085 5.835 0.085 ;
        RECT 6.125 -0.085 6.295 0.085 ;
        RECT 6.585 -0.085 6.755 0.085 ;
        RECT 7.045 -0.085 7.215 0.085 ;
        RECT 7.505 -0.085 7.675 0.085 ;
        RECT 7.965 -0.085 8.135 0.085 ;
        RECT 8.425 -0.085 8.595 0.085 ;
        RECT 8.885 -0.085 9.055 0.085 ;
        RECT 9.345 -0.085 9.515 0.085 ;
      LAYER met1 ;
        RECT 0.000 -0.240 9.660 0.240 ;
    END
  END VGND
  PIN VNB
    PORT
      LAYER pwell ;
        RECT 1.365 0.785 2.285 1.005 ;
        RECT 7.880 0.905 9.650 1.015 ;
        RECT 6.950 0.785 9.650 0.905 ;
        RECT 0.005 0.105 9.650 0.785 ;
        RECT 0.145 -0.085 0.315 0.105 ;
    END
  END VNB
  PIN VPB
    PORT
      LAYER nwell ;
        RECT -0.190 1.305 9.850 2.910 ;
    END
  END VPB
  OBS
      LAYER li1 ;
        RECT 0.085 1.965 0.345 2.465 ;
        RECT 1.015 2.045 1.235 2.465 ;
        RECT 0.085 1.795 0.835 1.965 ;
        RECT 0.605 0.805 0.835 1.795 ;
        RECT 0.085 0.635 0.835 0.805 ;
        RECT 0.085 0.345 0.345 0.635 ;
        RECT 1.005 0.565 1.235 2.045 ;
        RECT 1.955 1.965 2.125 2.465 ;
        RECT 2.360 2.250 3.190 2.420 ;
        RECT 1.430 1.795 2.125 1.965 ;
        RECT 1.430 0.825 1.600 1.795 ;
        RECT 2.350 1.575 2.850 1.955 ;
        RECT 1.430 0.635 2.125 0.825 ;
        RECT 2.350 0.705 2.570 1.575 ;
        RECT 3.020 1.405 3.190 2.250 ;
        RECT 3.990 2.085 4.160 2.375 ;
        RECT 5.110 2.165 5.740 2.415 ;
        RECT 5.570 2.085 5.740 2.165 ;
        RECT 6.540 2.085 6.780 2.375 ;
        RECT 3.360 1.835 4.710 2.085 ;
        RECT 3.360 1.575 3.610 1.835 ;
        RECT 4.120 1.405 4.370 1.565 ;
        RECT 3.020 1.235 4.370 1.405 ;
        RECT 3.020 1.195 3.440 1.235 ;
        RECT 2.750 0.645 3.100 1.015 ;
        RECT 1.015 0.345 1.235 0.565 ;
        RECT 1.955 0.305 2.125 0.635 ;
        RECT 3.270 0.465 3.440 1.195 ;
        RECT 4.540 1.065 4.710 1.835 ;
        RECT 2.425 0.265 3.440 0.465 ;
        RECT 4.310 0.725 4.710 1.065 ;
        RECT 4.880 1.655 5.400 1.965 ;
        RECT 5.570 1.915 6.780 2.085 ;
        RECT 4.880 0.895 5.050 1.655 ;
        RECT 5.220 1.065 5.400 1.475 ;
        RECT 5.570 1.405 5.740 1.915 ;
        RECT 7.510 1.765 7.680 2.375 ;
        RECT 7.970 1.915 8.300 2.425 ;
        RECT 7.510 1.745 7.880 1.765 ;
        RECT 5.910 1.575 7.880 1.745 ;
        RECT 5.570 1.235 7.490 1.405 ;
        RECT 5.800 0.895 6.150 1.015 ;
        RECT 4.880 0.725 6.150 0.895 ;
        RECT 4.310 0.295 4.560 0.725 ;
        RECT 6.320 0.475 6.490 1.235 ;
        RECT 7.140 1.175 7.490 1.235 ;
        RECT 7.690 0.680 7.880 1.575 ;
        RECT 5.640 0.305 6.490 0.475 ;
        RECT 7.530 0.350 7.880 0.680 ;
        RECT 8.050 1.325 8.300 1.915 ;
        RECT 8.050 0.995 8.850 1.325 ;
        RECT 8.050 0.345 8.220 0.995 ;
      LAYER mcon ;
        RECT 0.605 1.785 0.775 1.955 ;
        RECT 1.065 0.765 1.235 0.935 ;
        RECT 2.445 1.785 2.615 1.955 ;
        RECT 2.905 0.765 3.075 0.935 ;
        RECT 5.205 1.785 5.375 1.955 ;
        RECT 5.225 1.105 5.395 1.275 ;
      LAYER met1 ;
        RECT 0.545 1.940 0.835 1.985 ;
        RECT 2.385 1.940 2.675 1.985 ;
        RECT 5.145 1.940 5.435 1.985 ;
        RECT 0.545 1.800 5.435 1.940 ;
        RECT 0.545 1.755 0.835 1.800 ;
        RECT 2.385 1.755 2.675 1.800 ;
        RECT 5.145 1.755 5.435 1.800 ;
        RECT 5.165 1.260 5.455 1.305 ;
        RECT 2.920 1.120 5.455 1.260 ;
        RECT 2.920 0.965 3.135 1.120 ;
        RECT 5.165 1.075 5.455 1.120 ;
        RECT 1.005 0.920 1.295 0.965 ;
        RECT 2.845 0.920 3.135 0.965 ;
        RECT 1.005 0.780 3.135 0.920 ;
        RECT 1.005 0.735 1.295 0.780 ;
        RECT 2.845 0.735 3.135 0.780 ;
  END
END sky130_fd_sc_hd__dfstp_2
MACRO sky130_fd_sc_hd__clkbuf_4
  CLASS BLOCK ;
  FOREIGN sky130_fd_sc_hd__clkbuf_4 ;
  ORIGIN 0.000 0.000 ;
  SIZE 2.760 BY 2.720 ;
  PIN X
    ANTENNADIFFAREA 0.795200 ;
    PORT
      LAYER li1 ;
        RECT 1.045 2.005 1.305 2.465 ;
        RECT 1.905 2.005 2.165 2.465 ;
        RECT 1.045 1.835 2.165 2.005 ;
        RECT 1.905 1.585 2.165 1.835 ;
        RECT 1.905 1.415 2.660 1.585 ;
        RECT 2.255 0.905 2.660 1.415 ;
        RECT 1.010 0.735 2.660 0.905 ;
        RECT 1.010 0.345 1.305 0.735 ;
        RECT 1.905 0.345 2.165 0.735 ;
    END
  END X
  PIN A
    ANTENNAGATEAREA 0.213000 ;
    PORT
      LAYER li1 ;
        RECT 0.425 0.755 0.775 1.325 ;
    END
  END A
  PIN VNB
    PORT
      LAYER pwell ;
        RECT 0.005 0.105 2.745 0.785 ;
        RECT 0.145 -0.085 0.315 0.105 ;
    END
  END VNB
  PIN VPB
    PORT
      LAYER nwell ;
        RECT -0.190 1.305 2.950 2.910 ;
    END
  END VPB
  PIN VGND
    USE GROUND ;
    PORT
      LAYER li1 ;
        RECT 0.555 0.085 0.830 0.565 ;
        RECT 1.475 0.085 1.730 0.565 ;
        RECT 2.335 0.085 2.615 0.565 ;
        RECT 0.000 -0.085 2.760 0.085 ;
      LAYER mcon ;
        RECT 0.145 -0.085 0.315 0.085 ;
        RECT 0.605 -0.085 0.775 0.085 ;
        RECT 1.065 -0.085 1.235 0.085 ;
        RECT 1.525 -0.085 1.695 0.085 ;
        RECT 1.985 -0.085 2.155 0.085 ;
        RECT 2.445 -0.085 2.615 0.085 ;
      LAYER met1 ;
        RECT 0.000 -0.240 2.760 0.240 ;
    END
  END VGND
  PIN VPWR
    USE POWER ;
    PORT
      LAYER li1 ;
        RECT 0.000 2.635 2.760 2.805 ;
        RECT 0.565 1.835 0.875 2.635 ;
        RECT 1.475 2.175 1.730 2.635 ;
        RECT 2.335 1.765 2.620 2.635 ;
      LAYER mcon ;
        RECT 0.145 2.635 0.315 2.805 ;
        RECT 0.605 2.635 0.775 2.805 ;
        RECT 1.065 2.635 1.235 2.805 ;
        RECT 1.525 2.635 1.695 2.805 ;
        RECT 1.985 2.635 2.155 2.805 ;
        RECT 2.445 2.635 2.615 2.805 ;
      LAYER met1 ;
        RECT 0.000 2.480 2.760 2.960 ;
    END
  END VPWR
  OBS
      LAYER li1 ;
        RECT 0.085 1.665 0.395 2.465 ;
        RECT 0.085 1.495 1.115 1.665 ;
        RECT 0.085 0.585 0.255 1.495 ;
        RECT 0.945 1.245 1.115 1.495 ;
        RECT 0.945 1.075 2.085 1.245 ;
        RECT 0.085 0.255 0.385 0.585 ;
  END
END sky130_fd_sc_hd__clkbuf_4
MACRO sky130_fd_sc_hd__nand2_1
  CLASS BLOCK ;
  FOREIGN sky130_fd_sc_hd__nand2_1 ;
  ORIGIN 0.000 0.000 ;
  SIZE 1.380 BY 2.720 ;
  PIN Y
    ANTENNADIFFAREA 0.439000 ;
    PORT
      LAYER li1 ;
        RECT 0.535 1.485 0.865 2.465 ;
        RECT 0.600 0.885 0.770 1.485 ;
        RECT 0.600 0.255 1.295 0.885 ;
    END
  END Y
  PIN B
    ANTENNAGATEAREA 0.247500 ;
    PORT
      LAYER li1 ;
        RECT 0.095 1.055 0.430 1.325 ;
    END
  END B
  PIN A
    ANTENNAGATEAREA 0.247500 ;
    PORT
      LAYER li1 ;
        RECT 0.940 1.075 1.275 1.325 ;
    END
  END A
  PIN VNB
    PORT
      LAYER pwell ;
        RECT 0.025 0.105 1.375 1.015 ;
        RECT 0.140 -0.085 0.310 0.105 ;
    END
  END VNB
  PIN VPB
    PORT
      LAYER nwell ;
        RECT -0.190 1.305 1.570 2.910 ;
    END
  END VPB
  PIN VGND
    USE GROUND ;
    PORT
      LAYER li1 ;
        RECT 0.085 0.085 0.395 0.885 ;
        RECT 0.000 -0.085 1.380 0.085 ;
      LAYER mcon ;
        RECT 0.145 -0.085 0.315 0.085 ;
        RECT 0.605 -0.085 0.775 0.085 ;
        RECT 1.065 -0.085 1.235 0.085 ;
      LAYER met1 ;
        RECT 0.000 -0.240 1.380 0.240 ;
    END
  END VGND
  PIN VPWR
    USE POWER ;
    PORT
      LAYER li1 ;
        RECT 0.000 2.635 1.380 2.805 ;
        RECT 0.085 1.495 0.365 2.635 ;
        RECT 1.035 1.495 1.295 2.635 ;
      LAYER mcon ;
        RECT 0.145 2.635 0.315 2.805 ;
        RECT 0.605 2.635 0.775 2.805 ;
        RECT 1.065 2.635 1.235 2.805 ;
      LAYER met1 ;
        RECT 0.000 2.480 1.380 2.960 ;
    END
  END VPWR
END sky130_fd_sc_hd__nand2_1
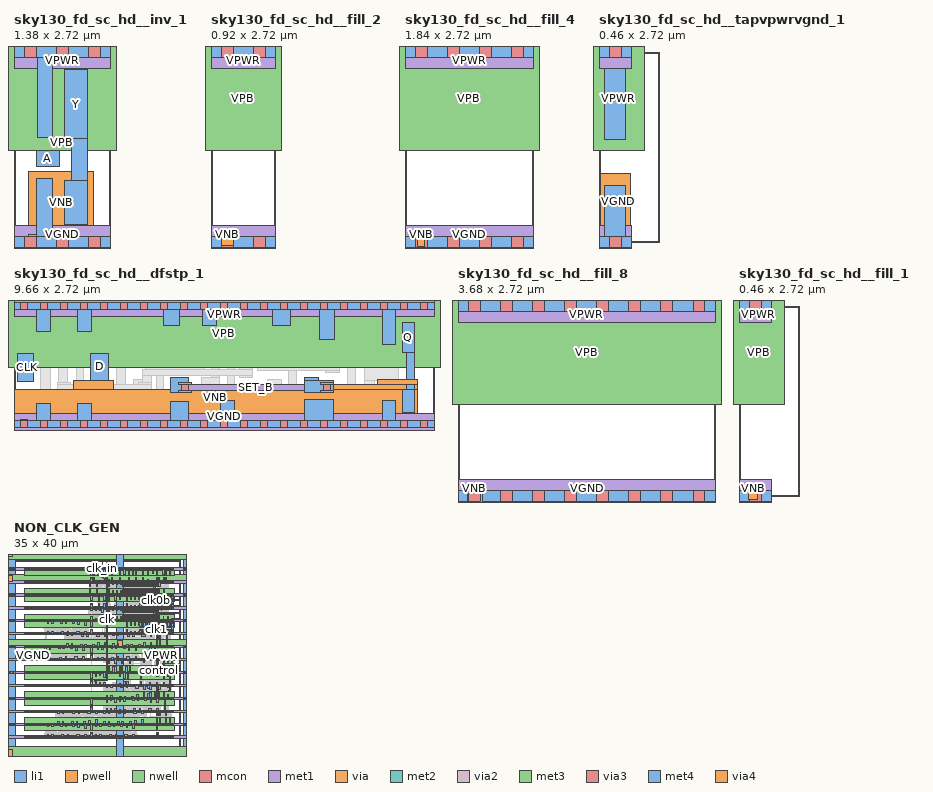
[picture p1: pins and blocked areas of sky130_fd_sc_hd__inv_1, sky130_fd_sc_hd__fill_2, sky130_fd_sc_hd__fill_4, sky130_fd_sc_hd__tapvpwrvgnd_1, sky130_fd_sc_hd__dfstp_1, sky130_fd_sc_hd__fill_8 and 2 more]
MACRO sky130_fd_sc_hd__inv_1
  CLASS BLOCK ;
  FOREIGN sky130_fd_sc_hd__inv_1 ;
  ORIGIN 0.000 0.000 ;
  SIZE 1.380 BY 2.720 ;
  PIN Y
    ANTENNADIFFAREA 0.429000 ;
    PORT
      LAYER li1 ;
        RECT 0.720 1.485 1.050 2.465 ;
        RECT 0.820 0.885 1.050 1.485 ;
        RECT 0.720 0.255 1.050 0.885 ;
    END
  END Y
  PIN A
    ANTENNAGATEAREA 0.247500 ;
    PORT
      LAYER li1 ;
        RECT 0.320 1.075 0.650 1.315 ;
    END
  END A
  PIN VNB
    PORT
      LAYER pwell ;
        RECT 0.210 0.105 1.140 1.015 ;
        RECT 0.210 0.085 0.315 0.105 ;
        RECT 0.145 -0.085 0.315 0.085 ;
    END
  END VNB
  PIN VPB
    PORT
      LAYER nwell ;
        RECT -0.190 1.305 1.570 2.910 ;
    END
  END VPB
  PIN VGND
    USE GROUND ;
    PORT
      LAYER li1 ;
        RECT 0.320 0.085 0.550 0.905 ;
        RECT 0.000 -0.085 1.380 0.085 ;
      LAYER mcon ;
        RECT 0.145 -0.085 0.315 0.085 ;
        RECT 0.605 -0.085 0.775 0.085 ;
        RECT 1.065 -0.085 1.235 0.085 ;
      LAYER met1 ;
        RECT 0.000 -0.240 1.380 0.240 ;
    END
  END VGND
  PIN VPWR
    USE POWER ;
    PORT
      LAYER li1 ;
        RECT 0.000 2.635 1.380 2.805 ;
        RECT 0.340 1.495 0.550 2.635 ;
      LAYER mcon ;
        RECT 0.145 2.635 0.315 2.805 ;
        RECT 0.605 2.635 0.775 2.805 ;
        RECT 1.065 2.635 1.235 2.805 ;
      LAYER met1 ;
        RECT 0.000 2.480 1.380 2.960 ;
    END
  END VPWR
END sky130_fd_sc_hd__inv_1
MACRO VIA_M1M2_PR
  CLASS BLOCK ;
  FOREIGN VIA_M1M2_PR ;
  ORIGIN 0.160 0.160 ;
  SIZE 0.320 BY 0.320 ;
  OBS
      LAYER met1 ;
        RECT -0.160 -0.130 0.160 0.130 ;
      LAYER via ;
        RECT -0.130 -0.130 0.130 0.130 ;
      LAYER met2 ;
        RECT -0.130 -0.160 0.130 0.160 ;
  END
END VIA_M1M2_PR
MACRO sky130_fd_sc_hd__fill_2
  CLASS BLOCK ;
  FOREIGN sky130_fd_sc_hd__fill_2 ;
  ORIGIN 0.000 0.000 ;
  SIZE 0.920 BY 2.720 ;
  PIN VNB
    PORT
      LAYER pwell ;
        RECT 0.155 -0.050 0.315 0.060 ;
    END
  END VNB
  PIN VPB
    PORT
      LAYER nwell ;
        RECT -0.190 1.305 1.110 2.910 ;
    END
  END VPB
  PIN VGND
    USE GROUND ;
    PORT
      LAYER li1 ;
        RECT 0.000 -0.085 0.920 0.085 ;
      LAYER mcon ;
        RECT 0.145 -0.085 0.315 0.085 ;
        RECT 0.605 -0.085 0.775 0.085 ;
      LAYER met1 ;
        RECT 0.000 -0.240 0.920 0.240 ;
    END
  END VGND
  PIN VPWR
    USE POWER ;
    PORT
      LAYER li1 ;
        RECT 0.000 2.635 0.920 2.805 ;
      LAYER mcon ;
        RECT 0.145 2.635 0.315 2.805 ;
        RECT 0.605 2.635 0.775 2.805 ;
      LAYER met1 ;
        RECT 0.000 2.480 0.920 2.960 ;
    END
  END VPWR
END sky130_fd_sc_hd__fill_2
MACRO sky130_fd_sc_hd__fill_4
  CLASS BLOCK ;
  FOREIGN sky130_fd_sc_hd__fill_4 ;
  ORIGIN 0.000 0.000 ;
  SIZE 1.840 BY 2.720 ;
  PIN VNB
    PORT
      LAYER pwell ;
        RECT 0.175 -0.060 0.285 0.060 ;
    END
  END VNB
  PIN VPB
    PORT
      LAYER nwell ;
        RECT -0.190 1.305 2.030 2.910 ;
    END
  END VPB
  PIN VGND
    USE GROUND ;
    PORT
      LAYER li1 ;
        RECT 0.000 -0.085 1.840 0.085 ;
      LAYER mcon ;
        RECT 0.145 -0.085 0.315 0.085 ;
        RECT 0.605 -0.085 0.775 0.085 ;
        RECT 1.065 -0.085 1.235 0.085 ;
        RECT 1.525 -0.085 1.695 0.085 ;
      LAYER met1 ;
        RECT 0.000 -0.240 1.840 0.240 ;
    END
  END VGND
  PIN VPWR
    USE POWER ;
    PORT
      LAYER li1 ;
        RECT 0.000 2.635 1.840 2.805 ;
      LAYER mcon ;
        RECT 0.145 2.635 0.315 2.805 ;
        RECT 0.605 2.635 0.775 2.805 ;
        RECT 1.065 2.635 1.235 2.805 ;
        RECT 1.525 2.635 1.695 2.805 ;
      LAYER met1 ;
        RECT 0.000 2.480 1.840 2.960 ;
    END
  END VPWR
END sky130_fd_sc_hd__fill_4
MACRO VIA_L1M1_PR_MR
  CLASS BLOCK ;
  FOREIGN VIA_L1M1_PR_MR ;
  ORIGIN 0.145 0.115 ;
  SIZE 0.290 BY 0.230 ;
  OBS
      LAYER li1 ;
        RECT -0.085 -0.085 0.085 0.085 ;
      LAYER met1 ;
        RECT -0.145 -0.115 0.145 0.115 ;
  END
END VIA_L1M1_PR_MR
MACRO sky130_fd_sc_hd__tapvpwrvgnd_1
  CLASS BLOCK ;
  FOREIGN sky130_fd_sc_hd__tapvpwrvgnd_1 ;
  ORIGIN 0.000 0.000 ;
  SIZE 0.460 BY 2.720 ;
  PIN VPWR
    USE POWER ;
    PORT
      LAYER nwell ;
        RECT -0.190 1.305 0.650 2.910 ;
      LAYER li1 ;
        RECT 0.000 2.635 0.460 2.805 ;
        RECT 0.085 1.470 0.375 2.635 ;
      LAYER mcon ;
        RECT 0.145 2.635 0.315 2.805 ;
      LAYER met1 ;
        RECT 0.000 2.480 0.460 2.960 ;
    END
  END VPWR
  PIN VGND
    USE GROUND ;
    PORT
      LAYER pwell ;
        RECT 0.015 0.190 0.445 0.975 ;
      LAYER li1 ;
        RECT 0.085 0.085 0.375 0.810 ;
        RECT 0.000 -0.085 0.460 0.085 ;
      LAYER mcon ;
        RECT 0.145 -0.085 0.315 0.085 ;
      LAYER met1 ;
        RECT 0.000 -0.240 0.460 0.240 ;
    END
  END VGND
END sky130_fd_sc_hd__tapvpwrvgnd_1
MACRO VIA_via2_1600x480
  CLASS BLOCK ;
  FOREIGN VIA_via2_1600x480 ;
  ORIGIN 0.800 0.240 ;
  SIZE 1.600 BY 0.480 ;
  OBS
      LAYER met2 ;
        RECT -0.740 -0.240 0.740 0.240 ;
      LAYER via2 ;
        RECT -0.740 -0.140 -0.460 0.140 ;
        RECT -0.340 -0.140 -0.060 0.140 ;
        RECT 0.060 -0.140 0.340 0.140 ;
        RECT 0.460 -0.140 0.740 0.140 ;
      LAYER met3 ;
        RECT -0.800 -0.165 0.800 0.165 ;
  END
END VIA_via2_1600x480
MACRO VIA_via3_1600x480
  CLASS BLOCK ;
  FOREIGN VIA_via3_1600x480 ;
  ORIGIN 0.800 0.240 ;
  SIZE 1.600 BY 0.480 ;
  OBS
      LAYER met3 ;
        RECT -0.800 -0.160 0.800 0.160 ;
      LAYER via3 ;
        RECT -0.760 -0.160 -0.440 0.160 ;
        RECT -0.360 -0.160 -0.040 0.160 ;
        RECT 0.040 -0.160 0.360 0.160 ;
        RECT 0.440 -0.160 0.760 0.160 ;
      LAYER met4 ;
        RECT -0.800 -0.240 0.800 0.240 ;
  END
END VIA_via3_1600x480
MACRO VIA_via_1600x480
  CLASS BLOCK ;
  FOREIGN VIA_via_1600x480 ;
  ORIGIN 0.800 0.240 ;
  SIZE 1.600 BY 0.480 ;
  OBS
      LAYER met1 ;
        RECT -0.800 -0.240 0.800 0.240 ;
      LAYER via ;
        RECT -0.770 -0.130 -0.510 0.130 ;
        RECT -0.450 -0.130 -0.190 0.130 ;
        RECT -0.130 -0.130 0.130 0.130 ;
        RECT 0.190 -0.130 0.450 0.130 ;
        RECT 0.510 -0.130 0.770 0.130 ;
      LAYER met2 ;
        RECT -0.770 -0.240 0.770 0.240 ;
  END
END VIA_via_1600x480
MACRO sky130_fd_sc_hd__dfstp_1
  CLASS BLOCK ;
  FOREIGN sky130_fd_sc_hd__dfstp_1 ;
  ORIGIN 0.000 0.000 ;
  SIZE 9.660 BY 2.720 ;
  PIN D
    ANTENNAGATEAREA 0.222000 ;
    PORT
      LAYER li1 ;
        RECT 1.770 1.005 2.180 1.625 ;
    END
  END D
  PIN VPWR
    USE POWER ;
    PORT
      LAYER li1 ;
        RECT 0.000 2.635 9.660 2.805 ;
        RECT 0.515 2.135 0.845 2.635 ;
        RECT 1.455 2.135 1.785 2.635 ;
        RECT 3.430 2.255 3.810 2.635 ;
        RECT 4.330 2.255 4.660 2.635 ;
        RECT 5.940 2.255 6.360 2.635 ;
        RECT 7.030 1.945 7.360 2.635 ;
        RECT 8.480 1.835 8.765 2.635 ;
      LAYER mcon ;
        RECT 0.145 2.635 0.315 2.805 ;
        RECT 0.605 2.635 0.775 2.805 ;
        RECT 1.065 2.635 1.235 2.805 ;
        RECT 1.525 2.635 1.695 2.805 ;
        RECT 1.985 2.635 2.155 2.805 ;
        RECT 2.445 2.635 2.615 2.805 ;
        RECT 2.905 2.635 3.075 2.805 ;
        RECT 3.365 2.635 3.535 2.805 ;
        RECT 3.825 2.635 3.995 2.805 ;
        RECT 4.285 2.635 4.455 2.805 ;
        RECT 4.745 2.635 4.915 2.805 ;
        RECT 5.205 2.635 5.375 2.805 ;
        RECT 5.665 2.635 5.835 2.805 ;
        RECT 6.125 2.635 6.295 2.805 ;
        RECT 6.585 2.635 6.755 2.805 ;
        RECT 7.045 2.635 7.215 2.805 ;
        RECT 7.505 2.635 7.675 2.805 ;
        RECT 7.965 2.635 8.135 2.805 ;
        RECT 8.425 2.635 8.595 2.805 ;
        RECT 8.885 2.635 9.055 2.805 ;
        RECT 9.345 2.635 9.515 2.805 ;
      LAYER met1 ;
        RECT 0.000 2.480 9.660 2.960 ;
    END
  END VPWR
  PIN Q
    ANTENNADIFFAREA 0.429000 ;
    PORT
      LAYER li1 ;
        RECT 8.945 1.655 9.200 2.325 ;
        RECT 9.020 0.795 9.200 1.655 ;
        RECT 8.945 0.265 9.200 0.795 ;
    END
  END Q
  PIN SET_B
    ANTENNAGATEAREA 0.252000 ;
    PORT
      LAYER li1 ;
        RECT 3.610 0.735 4.020 1.065 ;
        RECT 6.680 1.005 7.010 1.065 ;
        RECT 6.680 0.735 7.340 1.005 ;
      LAYER mcon ;
        RECT 3.850 0.765 4.020 0.935 ;
        RECT 7.110 0.765 7.280 0.935 ;
      LAYER met1 ;
        RECT 3.790 0.920 4.080 0.965 ;
        RECT 7.050 0.920 7.340 0.965 ;
        RECT 3.790 0.780 7.340 0.920 ;
        RECT 3.790 0.735 4.080 0.780 ;
        RECT 7.050 0.735 7.340 0.780 ;
    END
  END SET_B
  PIN CLK
    ANTENNAGATEAREA 0.159000 ;
    PORT
      LAYER li1 ;
        RECT 0.090 0.975 0.440 1.625 ;
    END
  END CLK
  PIN VGND
    USE GROUND ;
    PORT
      LAYER li1 ;
        RECT 0.515 0.085 0.845 0.465 ;
        RECT 1.455 0.085 1.785 0.465 ;
        RECT 3.610 0.085 4.020 0.525 ;
        RECT 4.760 0.085 5.080 0.545 ;
        RECT 6.690 0.085 7.350 0.565 ;
        RECT 8.480 0.085 8.765 0.545 ;
        RECT 0.000 -0.085 9.660 0.085 ;
      LAYER mcon ;
        RECT 0.145 -0.085 0.315 0.085 ;
        RECT 0.605 -0.085 0.775 0.085 ;
        RECT 1.065 -0.085 1.235 0.085 ;
        RECT 1.525 -0.085 1.695 0.085 ;
        RECT 1.985 -0.085 2.155 0.085 ;
        RECT 2.445 -0.085 2.615 0.085 ;
        RECT 2.905 -0.085 3.075 0.085 ;
        RECT 3.365 -0.085 3.535 0.085 ;
        RECT 3.825 -0.085 3.995 0.085 ;
        RECT 4.285 -0.085 4.455 0.085 ;
        RECT 4.745 -0.085 4.915 0.085 ;
        RECT 5.205 -0.085 5.375 0.085 ;
        RECT 5.665 -0.085 5.835 0.085 ;
        RECT 6.125 -0.085 6.295 0.085 ;
        RECT 6.585 -0.085 6.755 0.085 ;
        RECT 7.045 -0.085 7.215 0.085 ;
        RECT 7.505 -0.085 7.675 0.085 ;
        RECT 7.965 -0.085 8.135 0.085 ;
        RECT 8.425 -0.085 8.595 0.085 ;
        RECT 8.885 -0.085 9.055 0.085 ;
        RECT 9.345 -0.085 9.515 0.085 ;
      LAYER met1 ;
        RECT 0.000 -0.240 9.660 0.240 ;
    END
  END VGND
  PIN VNB
    PORT
      LAYER pwell ;
        RECT 1.365 0.785 2.285 1.005 ;
        RECT 8.365 0.905 9.285 1.015 ;
        RECT 6.950 0.785 9.285 0.905 ;
        RECT 0.005 0.105 9.285 0.785 ;
        RECT 0.145 -0.085 0.315 0.105 ;
    END
  END VNB
  PIN VPB
    PORT
      LAYER nwell ;
        RECT -0.190 1.305 9.850 2.910 ;
    END
  END VPB
  OBS
      LAYER li1 ;
        RECT 0.175 1.965 0.345 2.465 ;
        RECT 0.175 1.795 0.840 1.965 ;
        RECT 0.610 0.805 0.840 1.795 ;
        RECT 0.175 0.635 0.840 0.805 ;
        RECT 0.175 0.345 0.345 0.635 ;
        RECT 1.015 0.345 1.240 2.465 ;
        RECT 1.955 1.965 2.125 2.465 ;
        RECT 2.360 2.250 3.190 2.420 ;
        RECT 1.430 1.795 2.125 1.965 ;
        RECT 1.430 0.825 1.600 1.795 ;
        RECT 2.350 1.575 2.850 1.955 ;
        RECT 1.430 0.635 2.125 0.825 ;
        RECT 2.350 0.705 2.570 1.575 ;
        RECT 3.020 1.405 3.190 2.250 ;
        RECT 3.990 2.085 4.160 2.375 ;
        RECT 5.130 2.165 5.760 2.415 ;
        RECT 5.590 2.085 5.760 2.165 ;
        RECT 6.560 2.085 6.800 2.375 ;
        RECT 3.360 1.835 4.730 2.085 ;
        RECT 3.360 1.575 3.610 1.835 ;
        RECT 4.120 1.405 4.370 1.565 ;
        RECT 3.020 1.235 4.370 1.405 ;
        RECT 3.020 1.195 3.440 1.235 ;
        RECT 2.750 0.645 3.100 1.015 ;
        RECT 1.955 0.305 2.125 0.635 ;
        RECT 3.270 0.465 3.440 1.195 ;
        RECT 4.540 1.065 4.730 1.835 ;
        RECT 2.425 0.265 3.440 0.465 ;
        RECT 4.310 0.725 4.730 1.065 ;
        RECT 4.900 1.655 5.420 1.965 ;
        RECT 5.590 1.915 6.800 2.085 ;
        RECT 4.900 0.895 5.070 1.655 ;
        RECT 5.240 1.065 5.420 1.475 ;
        RECT 5.590 1.405 5.760 1.915 ;
        RECT 7.530 1.765 7.700 2.375 ;
        RECT 7.970 1.915 8.300 2.425 ;
        RECT 7.530 1.745 7.850 1.765 ;
        RECT 5.930 1.575 7.850 1.745 ;
        RECT 5.590 1.235 7.490 1.405 ;
        RECT 5.820 0.895 6.150 1.015 ;
        RECT 4.900 0.725 6.150 0.895 ;
        RECT 4.310 0.295 4.560 0.725 ;
        RECT 6.320 0.475 6.490 1.235 ;
        RECT 7.160 1.175 7.490 1.235 ;
        RECT 7.660 0.680 7.850 1.575 ;
        RECT 5.640 0.305 6.490 0.475 ;
        RECT 7.530 0.350 7.850 0.680 ;
        RECT 8.050 1.325 8.300 1.915 ;
        RECT 8.050 0.995 8.850 1.325 ;
        RECT 8.050 0.345 8.300 0.995 ;
      LAYER mcon ;
        RECT 0.610 1.785 0.780 1.955 ;
        RECT 1.070 0.765 1.240 0.935 ;
        RECT 2.470 1.785 2.640 1.955 ;
        RECT 2.930 0.765 3.100 0.935 ;
        RECT 5.250 1.785 5.420 1.955 ;
        RECT 5.250 1.105 5.420 1.275 ;
      LAYER met1 ;
        RECT 0.550 1.940 0.840 1.985 ;
        RECT 2.410 1.940 2.700 1.985 ;
        RECT 5.190 1.940 5.480 1.985 ;
        RECT 0.550 1.800 5.480 1.940 ;
        RECT 0.550 1.755 0.840 1.800 ;
        RECT 2.410 1.755 2.700 1.800 ;
        RECT 5.190 1.755 5.480 1.800 ;
        RECT 5.190 1.260 5.480 1.305 ;
        RECT 2.945 1.120 5.480 1.260 ;
        RECT 2.945 0.965 3.160 1.120 ;
        RECT 5.190 1.075 5.480 1.120 ;
        RECT 1.010 0.920 1.300 0.965 ;
        RECT 2.870 0.920 3.160 0.965 ;
        RECT 1.010 0.780 3.160 0.920 ;
        RECT 1.010 0.735 1.300 0.780 ;
        RECT 2.870 0.735 3.160 0.780 ;
  END
END sky130_fd_sc_hd__dfstp_1
MACRO sky130_fd_sc_hd__fill_8
  CLASS BLOCK ;
  FOREIGN sky130_fd_sc_hd__fill_8 ;
  ORIGIN 0.000 0.000 ;
  SIZE 3.680 BY 2.720 ;
  PIN VNB
    PORT
      LAYER pwell ;
        RECT 0.130 -0.120 0.350 0.050 ;
    END
  END VNB
  PIN VPB
    PORT
      LAYER nwell ;
        RECT -0.190 1.305 3.870 2.910 ;
    END
  END VPB
  PIN VGND
    USE GROUND ;
    PORT
      LAYER li1 ;
        RECT 0.000 -0.085 3.680 0.085 ;
      LAYER mcon ;
        RECT 0.145 -0.085 0.315 0.085 ;
        RECT 0.605 -0.085 0.775 0.085 ;
        RECT 1.065 -0.085 1.235 0.085 ;
        RECT 1.525 -0.085 1.695 0.085 ;
        RECT 1.985 -0.085 2.155 0.085 ;
        RECT 2.445 -0.085 2.615 0.085 ;
        RECT 2.905 -0.085 3.075 0.085 ;
        RECT 3.365 -0.085 3.535 0.085 ;
      LAYER met1 ;
        RECT 0.000 -0.240 3.680 0.240 ;
    END
  END VGND
  PIN VPWR
    USE POWER ;
    PORT
      LAYER li1 ;
        RECT 0.000 2.635 3.680 2.805 ;
      LAYER mcon ;
        RECT 0.145 2.635 0.315 2.805 ;
        RECT 0.605 2.635 0.775 2.805 ;
        RECT 1.065 2.635 1.235 2.805 ;
        RECT 1.525 2.635 1.695 2.805 ;
        RECT 1.985 2.635 2.155 2.805 ;
        RECT 2.445 2.635 2.615 2.805 ;
        RECT 2.905 2.635 3.075 2.805 ;
        RECT 3.365 2.635 3.535 2.805 ;
      LAYER met1 ;
        RECT 0.000 2.480 3.680 2.960 ;
    END
  END VPWR
END sky130_fd_sc_hd__fill_8
MACRO sky130_fd_sc_hd__fill_1
  CLASS BLOCK ;
  FOREIGN sky130_fd_sc_hd__fill_1 ;
  ORIGIN 0.000 0.000 ;
  SIZE 0.460 BY 2.720 ;
  PIN VNB
    PORT
      LAYER pwell ;
        RECT 0.140 -0.055 0.260 0.055 ;
    END
  END VNB
  PIN VPB
    PORT
      LAYER nwell ;
        RECT -0.190 1.305 0.650 2.910 ;
    END
  END VPB
  PIN VPWR
    USE POWER ;
    PORT
      LAYER li1 ;
        RECT 0.000 2.635 0.460 2.805 ;
      LAYER mcon ;
        RECT 0.145 2.635 0.315 2.805 ;
      LAYER met1 ;
        RECT 0.000 2.480 0.460 2.960 ;
    END
  END VPWR
  PIN VGND
    USE GROUND ;
    PORT
      LAYER li1 ;
        RECT 0.000 -0.085 0.460 0.085 ;
      LAYER mcon ;
        RECT 0.145 -0.085 0.315 0.085 ;
      LAYER met1 ;
        RECT 0.000 -0.240 0.460 0.240 ;
    END
  END VGND
END sky130_fd_sc_hd__fill_1
MACRO VIA_via2_4200x480
  CLASS BLOCK ;
  FOREIGN VIA_via2_4200x480 ;
  ORIGIN 2.100 0.240 ;
  SIZE 4.200 BY 0.480 ;
  OBS
      LAYER met2 ;
        RECT -1.940 -0.240 1.940 0.240 ;
      LAYER via2 ;
        RECT -1.940 -0.140 -1.660 0.140 ;
        RECT -1.540 -0.140 -1.260 0.140 ;
        RECT -1.140 -0.140 -0.860 0.140 ;
        RECT -0.740 -0.140 -0.460 0.140 ;
        RECT -0.340 -0.140 -0.060 0.140 ;
        RECT 0.060 -0.140 0.340 0.140 ;
        RECT 0.460 -0.140 0.740 0.140 ;
        RECT 0.860 -0.140 1.140 0.140 ;
        RECT 1.260 -0.140 1.540 0.140 ;
        RECT 1.660 -0.140 1.940 0.140 ;
      LAYER met3 ;
        RECT -2.100 -0.165 2.100 0.165 ;
  END
END VIA_via2_4200x480
MACRO VIA_via3_4200x480
  CLASS BLOCK ;
  FOREIGN VIA_via3_4200x480 ;
  ORIGIN 2.100 0.240 ;
  SIZE 4.200 BY 0.480 ;
  OBS
      LAYER met3 ;
        RECT -2.100 -0.160 2.100 0.160 ;
      LAYER via3 ;
        RECT -1.960 -0.160 -1.640 0.160 ;
        RECT -1.560 -0.160 -1.240 0.160 ;
        RECT -1.160 -0.160 -0.840 0.160 ;
        RECT -0.760 -0.160 -0.440 0.160 ;
        RECT -0.360 -0.160 -0.040 0.160 ;
        RECT 0.040 -0.160 0.360 0.160 ;
        RECT 0.440 -0.160 0.760 0.160 ;
        RECT 0.840 -0.160 1.160 0.160 ;
        RECT 1.240 -0.160 1.560 0.160 ;
        RECT 1.640 -0.160 1.960 0.160 ;
      LAYER met4 ;
        RECT -2.100 -0.240 2.100 0.240 ;
  END
END VIA_via3_4200x480
MACRO VIA_via_4200x480
  CLASS BLOCK ;
  FOREIGN VIA_via_4200x480 ;
  ORIGIN 2.100 0.240 ;
  SIZE 4.200 BY 0.480 ;
  OBS
      LAYER met1 ;
        RECT -2.100 -0.240 2.100 0.240 ;
      LAYER via ;
        RECT -2.050 -0.130 -1.790 0.130 ;
        RECT -1.730 -0.130 -1.470 0.130 ;
        RECT -1.410 -0.130 -1.150 0.130 ;
        RECT -1.090 -0.130 -0.830 0.130 ;
        RECT -0.770 -0.130 -0.510 0.130 ;
        RECT -0.450 -0.130 -0.190 0.130 ;
        RECT -0.130 -0.130 0.130 0.130 ;
        RECT 0.190 -0.130 0.450 0.130 ;
        RECT 0.510 -0.130 0.770 0.130 ;
        RECT 0.830 -0.130 1.090 0.130 ;
        RECT 1.150 -0.130 1.410 0.130 ;
        RECT 1.470 -0.130 1.730 0.130 ;
        RECT 1.790 -0.130 2.050 0.130 ;
      LAYER met2 ;
        RECT -2.050 -0.240 2.050 0.240 ;
  END
END VIA_via_4200x480
MACRO VIA_via4_1600x4200
  CLASS BLOCK ;
  FOREIGN VIA_via4_1600x4200 ;
  ORIGIN 0.800 2.100 ;
  SIZE 1.600 BY 4.200 ;
  OBS
      LAYER met4 ;
        RECT -0.800 -2.100 0.800 2.100 ;
      LAYER via4 ;
        RECT -0.590 0.210 0.590 1.390 ;
        RECT -0.590 -1.390 0.590 -0.210 ;
      LAYER met5 ;
        RECT -0.800 -2.100 0.800 2.100 ;
  END
END VIA_via4_1600x4200
MACRO VIA_via4_4200x4200
  CLASS BLOCK ;
  FOREIGN VIA_via4_4200x4200 ;
  ORIGIN 2.100 2.100 ;
  SIZE 4.200 BY 4.200 ;
  OBS
      LAYER met4 ;
        RECT -2.100 -2.100 2.100 2.100 ;
      LAYER via4 ;
        RECT -1.390 -1.390 1.390 1.390 ;
      LAYER met5 ;
        RECT -2.100 -2.100 2.100 2.100 ;
  END
END VIA_via4_4200x4200
MACRO NON_CLK_GEN
  CLASS BLOCK ;
  FOREIGN NON_CLK_GEN ;
  ORIGIN 0.000 0.000 ;
  SIZE 35.000 BY 40.000 ;
  PIN VPWR
    USE POWER ;
    PORT
      LAYER nwell ;
        RECT 2.110 36.665 33.770 38.270 ;
        RECT 2.110 31.225 33.770 34.055 ;
        RECT 2.110 25.785 33.770 28.615 ;
        RECT 2.110 20.345 33.770 23.175 ;
        RECT 2.110 14.905 33.770 17.735 ;
        RECT 2.110 9.465 33.770 12.295 ;
        RECT 2.110 4.025 33.770 6.855 ;
      LAYER li1 ;
        RECT 2.300 37.995 33.580 38.165 ;
        RECT 16.185 36.830 16.475 37.995 ;
        RECT 16.645 36.855 16.925 37.995 ;
        RECT 17.595 36.855 17.855 37.995 ;
        RECT 18.925 37.215 19.255 37.995 ;
        RECT 19.815 37.570 20.150 37.995 ;
        RECT 20.580 36.855 20.790 37.995 ;
        RECT 22.165 36.855 22.445 37.995 ;
        RECT 23.115 36.855 23.375 37.995 ;
        RECT 24.005 36.855 24.285 37.995 ;
        RECT 24.955 36.855 25.215 37.995 ;
        RECT 25.640 36.855 25.850 37.995 ;
        RECT 27.020 36.855 27.230 37.995 ;
        RECT 28.150 36.855 28.405 37.995 ;
        RECT 29.075 37.195 29.305 37.995 ;
        RECT 29.985 36.830 30.275 37.995 ;
        RECT 31.315 36.855 31.645 37.995 ;
        RECT 31.825 36.855 32.105 37.995 ;
        RECT 32.775 36.855 33.035 37.995 ;
        RECT 15.980 32.725 16.190 33.865 ;
        RECT 17.360 32.725 17.570 33.865 ;
        RECT 19.955 32.725 20.125 33.915 ;
        RECT 20.795 32.725 20.965 33.525 ;
        RECT 21.635 32.725 21.805 33.525 ;
        RECT 22.475 32.725 22.645 33.525 ;
        RECT 23.315 32.725 23.485 33.525 ;
        RECT 24.155 32.725 24.325 33.525 ;
        RECT 24.995 32.725 25.165 33.525 ;
        RECT 25.835 32.725 26.005 33.525 ;
        RECT 26.675 32.725 26.845 33.525 ;
        RECT 27.515 32.725 27.685 33.525 ;
        RECT 28.355 32.725 28.525 33.525 ;
        RECT 29.195 32.725 29.365 33.525 ;
        RECT 29.985 32.725 30.275 33.890 ;
        RECT 30.445 32.725 30.725 33.865 ;
        RECT 31.395 32.725 31.655 33.865 ;
        RECT 2.300 32.555 33.580 32.725 ;
        RECT 16.185 31.390 16.475 32.555 ;
        RECT 17.820 31.415 18.030 32.555 ;
        RECT 18.945 31.415 19.225 32.555 ;
        RECT 19.895 31.415 20.155 32.555 ;
        RECT 21.250 31.415 21.505 32.555 ;
        RECT 22.175 31.755 22.405 32.555 ;
        RECT 23.635 31.365 23.805 32.555 ;
        RECT 24.475 31.755 24.645 32.555 ;
        RECT 25.315 31.755 25.485 32.555 ;
        RECT 26.155 31.755 26.325 32.555 ;
        RECT 26.995 31.755 27.165 32.555 ;
        RECT 27.835 31.755 28.005 32.555 ;
        RECT 28.675 31.755 28.845 32.555 ;
        RECT 29.515 31.755 29.685 32.555 ;
        RECT 30.355 31.755 30.525 32.555 ;
        RECT 31.195 31.755 31.365 32.555 ;
        RECT 32.035 31.755 32.205 32.555 ;
        RECT 32.875 31.755 33.045 32.555 ;
        RECT 16.205 27.285 16.515 28.085 ;
        RECT 17.115 27.285 17.370 27.745 ;
        RECT 17.975 27.285 18.260 28.155 ;
        RECT 18.525 27.285 18.755 28.425 ;
        RECT 19.425 27.285 19.635 28.425 ;
        RECT 19.955 27.285 20.125 28.475 ;
        RECT 20.795 27.285 20.965 28.085 ;
        RECT 21.635 27.285 21.805 28.085 ;
        RECT 22.475 27.285 22.645 28.085 ;
        RECT 23.315 27.285 23.485 28.085 ;
        RECT 24.155 27.285 24.325 28.085 ;
        RECT 24.995 27.285 25.165 28.085 ;
        RECT 25.835 27.285 26.005 28.085 ;
        RECT 26.675 27.285 26.845 28.085 ;
        RECT 27.515 27.285 27.685 28.085 ;
        RECT 28.355 27.285 28.525 28.085 ;
        RECT 29.195 27.285 29.365 28.085 ;
        RECT 29.985 27.285 30.275 28.450 ;
        RECT 30.445 27.285 30.705 28.425 ;
        RECT 31.375 27.285 31.545 28.085 ;
        RECT 32.215 27.285 32.470 28.085 ;
        RECT 2.300 27.115 33.580 27.285 ;
        RECT 6.955 26.615 7.285 27.115 ;
        RECT 7.895 26.615 8.225 27.115 ;
        RECT 9.870 26.735 10.250 27.115 ;
        RECT 10.770 26.735 11.100 27.115 ;
        RECT 12.380 26.735 12.800 27.115 ;
        RECT 13.470 26.425 13.800 27.115 ;
        RECT 14.920 26.315 15.205 27.115 ;
        RECT 16.185 25.950 16.475 27.115 ;
        RECT 23.635 25.925 23.805 27.115 ;
        RECT 24.475 26.315 24.645 27.115 ;
        RECT 25.315 26.315 25.485 27.115 ;
        RECT 26.155 26.315 26.325 27.115 ;
        RECT 26.995 26.315 27.165 27.115 ;
        RECT 27.835 26.315 28.005 27.115 ;
        RECT 28.675 26.315 28.845 27.115 ;
        RECT 29.515 26.315 29.685 27.115 ;
        RECT 30.355 26.315 30.525 27.115 ;
        RECT 31.195 26.315 31.365 27.115 ;
        RECT 32.035 26.315 32.205 27.115 ;
        RECT 32.875 26.315 33.045 27.115 ;
        RECT 11.095 21.845 11.425 22.345 ;
        RECT 12.035 21.845 12.365 22.345 ;
        RECT 14.010 21.845 14.390 22.225 ;
        RECT 14.910 21.845 15.240 22.225 ;
        RECT 16.520 21.845 16.940 22.225 ;
        RECT 17.610 21.845 17.940 22.535 ;
        RECT 19.060 21.845 19.345 22.645 ;
        RECT 20.755 21.845 21.085 22.345 ;
        RECT 21.695 21.845 22.025 22.345 ;
        RECT 23.670 21.845 24.050 22.225 ;
        RECT 24.570 21.845 24.900 22.225 ;
        RECT 26.180 21.845 26.600 22.225 ;
        RECT 27.270 21.845 27.600 22.535 ;
        RECT 28.720 21.845 29.005 22.645 ;
        RECT 29.985 21.845 30.275 23.010 ;
        RECT 30.700 21.845 30.910 22.985 ;
        RECT 32.080 21.845 32.290 22.985 ;
        RECT 2.300 21.675 33.580 21.845 ;
        RECT 6.495 21.175 6.825 21.675 ;
        RECT 7.435 21.175 7.765 21.675 ;
        RECT 9.410 21.295 9.790 21.675 ;
        RECT 10.310 21.295 10.640 21.675 ;
        RECT 11.920 21.295 12.340 21.675 ;
        RECT 13.010 20.985 13.340 21.675 ;
        RECT 14.460 20.875 14.745 21.675 ;
        RECT 16.185 20.510 16.475 21.675 ;
        RECT 17.535 21.175 17.865 21.675 ;
        RECT 18.475 21.175 18.805 21.675 ;
        RECT 20.450 21.295 20.830 21.675 ;
        RECT 21.350 21.295 21.680 21.675 ;
        RECT 22.960 21.295 23.380 21.675 ;
        RECT 24.050 20.985 24.380 21.675 ;
        RECT 25.500 20.875 25.785 21.675 ;
        RECT 28.605 20.535 28.885 21.675 ;
        RECT 29.555 20.535 29.815 21.675 ;
        RECT 19.865 16.405 20.145 17.545 ;
        RECT 20.815 16.405 21.075 17.545 ;
        RECT 21.245 16.405 21.525 17.545 ;
        RECT 22.195 16.405 22.455 17.545 ;
        RECT 22.625 16.405 22.905 17.545 ;
        RECT 23.575 16.405 23.835 17.545 ;
        RECT 24.260 16.405 24.470 17.545 ;
        RECT 26.765 16.405 27.025 17.545 ;
        RECT 27.695 16.405 27.865 17.205 ;
        RECT 28.535 16.405 28.790 17.205 ;
        RECT 29.985 16.405 30.275 17.570 ;
        RECT 31.385 16.405 31.695 17.205 ;
        RECT 32.295 16.405 32.550 16.865 ;
        RECT 33.155 16.405 33.440 17.275 ;
        RECT 2.300 16.235 33.580 16.405 ;
        RECT 16.185 15.070 16.475 16.235 ;
        RECT 17.125 15.435 17.435 16.235 ;
        RECT 18.035 15.775 18.290 16.235 ;
        RECT 18.895 15.365 19.180 16.235 ;
        RECT 22.180 15.475 22.510 16.235 ;
        RECT 23.110 15.085 23.370 16.235 ;
        RECT 23.800 15.095 24.010 16.235 ;
        RECT 26.560 15.095 26.770 16.235 ;
        RECT 28.610 15.775 28.825 16.235 ;
        RECT 29.970 15.515 30.330 16.235 ;
        RECT 31.370 15.095 31.625 16.235 ;
        RECT 32.295 15.435 32.525 16.235 ;
        RECT 19.375 10.965 19.705 11.465 ;
        RECT 20.315 10.965 20.645 11.465 ;
        RECT 22.290 10.965 22.670 11.345 ;
        RECT 23.190 10.965 23.520 11.345 ;
        RECT 24.780 10.965 25.200 11.345 ;
        RECT 25.870 10.965 26.200 11.655 ;
        RECT 27.330 10.965 27.500 12.105 ;
        RECT 28.170 10.965 28.435 11.815 ;
        RECT 28.605 10.965 28.885 12.105 ;
        RECT 29.555 10.965 29.815 12.105 ;
        RECT 29.985 10.965 30.275 12.130 ;
        RECT 30.445 10.965 30.725 12.105 ;
        RECT 31.395 10.965 31.655 12.105 ;
        RECT 32.265 10.965 32.595 11.725 ;
        RECT 2.300 10.795 33.580 10.965 ;
        RECT 16.185 9.630 16.475 10.795 ;
        RECT 19.425 9.995 19.735 10.795 ;
        RECT 20.335 10.335 20.590 10.795 ;
        RECT 21.195 9.925 21.480 10.795 ;
        RECT 22.135 10.295 22.465 10.795 ;
        RECT 23.075 10.295 23.405 10.795 ;
        RECT 25.050 10.415 25.430 10.795 ;
        RECT 25.950 10.415 26.280 10.795 ;
        RECT 27.560 10.415 27.980 10.795 ;
        RECT 28.650 10.105 28.980 10.795 ;
        RECT 30.100 9.995 30.385 10.795 ;
        RECT 31.620 9.655 31.830 10.795 ;
        RECT 9.255 5.525 9.585 6.025 ;
        RECT 10.195 5.525 10.525 6.025 ;
        RECT 12.170 5.525 12.550 5.905 ;
        RECT 13.070 5.525 13.400 5.905 ;
        RECT 14.680 5.525 15.100 5.905 ;
        RECT 15.770 5.525 16.100 6.215 ;
        RECT 17.220 5.525 17.505 6.325 ;
        RECT 18.915 5.525 19.245 6.025 ;
        RECT 19.855 5.525 20.185 6.025 ;
        RECT 21.830 5.525 22.210 5.905 ;
        RECT 22.730 5.525 23.060 5.905 ;
        RECT 24.340 5.525 24.760 5.905 ;
        RECT 25.430 5.525 25.760 6.215 ;
        RECT 26.880 5.525 27.165 6.325 ;
        RECT 29.985 5.525 30.275 6.690 ;
        RECT 30.700 5.525 30.910 6.665 ;
        RECT 31.825 5.525 32.105 6.665 ;
        RECT 32.775 5.525 33.035 6.665 ;
        RECT 2.300 5.355 33.580 5.525 ;
        RECT 6.955 4.855 7.285 5.355 ;
        RECT 7.895 4.855 8.225 5.355 ;
        RECT 9.870 4.975 10.250 5.355 ;
        RECT 10.770 4.975 11.100 5.355 ;
        RECT 12.380 4.975 12.800 5.355 ;
        RECT 13.470 4.665 13.800 5.355 ;
        RECT 14.920 4.555 15.205 5.355 ;
        RECT 16.185 4.190 16.475 5.355 ;
        RECT 17.075 4.855 17.405 5.355 ;
        RECT 18.015 4.855 18.345 5.355 ;
        RECT 19.990 4.975 20.370 5.355 ;
        RECT 20.890 4.975 21.220 5.355 ;
        RECT 22.500 4.975 22.920 5.355 ;
        RECT 23.590 4.665 23.920 5.355 ;
        RECT 25.040 4.555 25.325 5.355 ;
        RECT 29.985 4.190 30.275 5.355 ;
      LAYER mcon ;
        RECT 2.445 37.995 2.615 38.165 ;
        RECT 2.905 37.995 3.075 38.165 ;
        RECT 3.365 37.995 3.535 38.165 ;
        RECT 3.825 37.995 3.995 38.165 ;
        RECT 4.285 37.995 4.455 38.165 ;
        RECT 4.745 37.995 4.915 38.165 ;
        RECT 5.205 37.995 5.375 38.165 ;
        RECT 5.665 37.995 5.835 38.165 ;
        RECT 6.125 37.995 6.295 38.165 ;
        RECT 6.585 37.995 6.755 38.165 ;
        RECT 7.045 37.995 7.215 38.165 ;
        RECT 7.505 37.995 7.675 38.165 ;
        RECT 7.965 37.995 8.135 38.165 ;
        RECT 8.425 37.995 8.595 38.165 ;
        RECT 8.885 37.995 9.055 38.165 ;
        RECT 9.345 37.995 9.515 38.165 ;
        RECT 9.805 37.995 9.975 38.165 ;
        RECT 10.265 37.995 10.435 38.165 ;
        RECT 10.725 37.995 10.895 38.165 ;
        RECT 11.185 37.995 11.355 38.165 ;
        RECT 11.645 37.995 11.815 38.165 ;
        RECT 12.105 37.995 12.275 38.165 ;
        RECT 12.565 37.995 12.735 38.165 ;
        RECT 13.025 37.995 13.195 38.165 ;
        RECT 13.485 37.995 13.655 38.165 ;
        RECT 13.945 37.995 14.115 38.165 ;
        RECT 14.405 37.995 14.575 38.165 ;
        RECT 14.865 37.995 15.035 38.165 ;
        RECT 15.325 37.995 15.495 38.165 ;
        RECT 15.785 37.995 15.955 38.165 ;
        RECT 16.245 37.995 16.415 38.165 ;
        RECT 16.705 37.995 16.875 38.165 ;
        RECT 17.165 37.995 17.335 38.165 ;
        RECT 17.625 37.995 17.795 38.165 ;
        RECT 18.085 37.995 18.255 38.165 ;
        RECT 18.545 37.995 18.715 38.165 ;
        RECT 19.005 37.995 19.175 38.165 ;
        RECT 19.465 37.995 19.635 38.165 ;
        RECT 19.925 37.995 20.095 38.165 ;
        RECT 20.385 37.995 20.555 38.165 ;
        RECT 20.845 37.995 21.015 38.165 ;
        RECT 21.305 37.995 21.475 38.165 ;
        RECT 21.765 37.995 21.935 38.165 ;
        RECT 22.225 37.995 22.395 38.165 ;
        RECT 22.685 37.995 22.855 38.165 ;
        RECT 23.145 37.995 23.315 38.165 ;
        RECT 23.605 37.995 23.775 38.165 ;
        RECT 24.065 37.995 24.235 38.165 ;
        RECT 24.525 37.995 24.695 38.165 ;
        RECT 24.985 37.995 25.155 38.165 ;
        RECT 25.445 37.995 25.615 38.165 ;
        RECT 25.905 37.995 26.075 38.165 ;
        RECT 26.365 37.995 26.535 38.165 ;
        RECT 26.825 37.995 26.995 38.165 ;
        RECT 27.285 37.995 27.455 38.165 ;
        RECT 27.745 37.995 27.915 38.165 ;
        RECT 28.205 37.995 28.375 38.165 ;
        RECT 28.665 37.995 28.835 38.165 ;
        RECT 29.125 37.995 29.295 38.165 ;
        RECT 29.585 37.995 29.755 38.165 ;
        RECT 30.045 37.995 30.215 38.165 ;
        RECT 30.505 37.995 30.675 38.165 ;
        RECT 30.965 37.995 31.135 38.165 ;
        RECT 31.425 37.995 31.595 38.165 ;
        RECT 31.885 37.995 32.055 38.165 ;
        RECT 32.345 37.995 32.515 38.165 ;
        RECT 32.805 37.995 32.975 38.165 ;
        RECT 33.265 37.995 33.435 38.165 ;
        RECT 2.445 32.555 2.615 32.725 ;
        RECT 2.905 32.555 3.075 32.725 ;
        RECT 3.365 32.555 3.535 32.725 ;
        RECT 3.825 32.555 3.995 32.725 ;
        RECT 4.285 32.555 4.455 32.725 ;
        RECT 4.745 32.555 4.915 32.725 ;
        RECT 5.205 32.555 5.375 32.725 ;
        RECT 5.665 32.555 5.835 32.725 ;
        RECT 6.125 32.555 6.295 32.725 ;
        RECT 6.585 32.555 6.755 32.725 ;
        RECT 7.045 32.555 7.215 32.725 ;
        RECT 7.505 32.555 7.675 32.725 ;
        RECT 7.965 32.555 8.135 32.725 ;
        RECT 8.425 32.555 8.595 32.725 ;
        RECT 8.885 32.555 9.055 32.725 ;
        RECT 9.345 32.555 9.515 32.725 ;
        RECT 9.805 32.555 9.975 32.725 ;
        RECT 10.265 32.555 10.435 32.725 ;
        RECT 10.725 32.555 10.895 32.725 ;
        RECT 11.185 32.555 11.355 32.725 ;
        RECT 11.645 32.555 11.815 32.725 ;
        RECT 12.105 32.555 12.275 32.725 ;
        RECT 12.565 32.555 12.735 32.725 ;
        RECT 13.025 32.555 13.195 32.725 ;
        RECT 13.485 32.555 13.655 32.725 ;
        RECT 13.945 32.555 14.115 32.725 ;
        RECT 14.405 32.555 14.575 32.725 ;
        RECT 14.865 32.555 15.035 32.725 ;
        RECT 15.325 32.555 15.495 32.725 ;
        RECT 15.785 32.555 15.955 32.725 ;
        RECT 16.245 32.555 16.415 32.725 ;
        RECT 16.705 32.555 16.875 32.725 ;
        RECT 17.165 32.555 17.335 32.725 ;
        RECT 17.625 32.555 17.795 32.725 ;
        RECT 18.085 32.555 18.255 32.725 ;
        RECT 18.545 32.555 18.715 32.725 ;
        RECT 19.005 32.555 19.175 32.725 ;
        RECT 19.465 32.555 19.635 32.725 ;
        RECT 19.925 32.555 20.095 32.725 ;
        RECT 20.385 32.555 20.555 32.725 ;
        RECT 20.845 32.555 21.015 32.725 ;
        RECT 21.305 32.555 21.475 32.725 ;
        RECT 21.765 32.555 21.935 32.725 ;
        RECT 22.225 32.555 22.395 32.725 ;
        RECT 22.685 32.555 22.855 32.725 ;
        RECT 23.145 32.555 23.315 32.725 ;
        RECT 23.605 32.555 23.775 32.725 ;
        RECT 24.065 32.555 24.235 32.725 ;
        RECT 24.525 32.555 24.695 32.725 ;
        RECT 24.985 32.555 25.155 32.725 ;
        RECT 25.445 32.555 25.615 32.725 ;
        RECT 25.905 32.555 26.075 32.725 ;
        RECT 26.365 32.555 26.535 32.725 ;
        RECT 26.825 32.555 26.995 32.725 ;
        RECT 27.285 32.555 27.455 32.725 ;
        RECT 27.745 32.555 27.915 32.725 ;
        RECT 28.205 32.555 28.375 32.725 ;
        RECT 28.665 32.555 28.835 32.725 ;
        RECT 29.125 32.555 29.295 32.725 ;
        RECT 29.585 32.555 29.755 32.725 ;
        RECT 30.045 32.555 30.215 32.725 ;
        RECT 30.505 32.555 30.675 32.725 ;
        RECT 30.965 32.555 31.135 32.725 ;
        RECT 31.425 32.555 31.595 32.725 ;
        RECT 31.885 32.555 32.055 32.725 ;
        RECT 32.345 32.555 32.515 32.725 ;
        RECT 32.805 32.555 32.975 32.725 ;
        RECT 33.265 32.555 33.435 32.725 ;
        RECT 2.445 27.115 2.615 27.285 ;
        RECT 2.905 27.115 3.075 27.285 ;
        RECT 3.365 27.115 3.535 27.285 ;
        RECT 3.825 27.115 3.995 27.285 ;
        RECT 4.285 27.115 4.455 27.285 ;
        RECT 4.745 27.115 4.915 27.285 ;
        RECT 5.205 27.115 5.375 27.285 ;
        RECT 5.665 27.115 5.835 27.285 ;
        RECT 6.125 27.115 6.295 27.285 ;
        RECT 6.585 27.115 6.755 27.285 ;
        RECT 7.045 27.115 7.215 27.285 ;
        RECT 7.505 27.115 7.675 27.285 ;
        RECT 7.965 27.115 8.135 27.285 ;
        RECT 8.425 27.115 8.595 27.285 ;
        RECT 8.885 27.115 9.055 27.285 ;
        RECT 9.345 27.115 9.515 27.285 ;
        RECT 9.805 27.115 9.975 27.285 ;
        RECT 10.265 27.115 10.435 27.285 ;
        RECT 10.725 27.115 10.895 27.285 ;
        RECT 11.185 27.115 11.355 27.285 ;
        RECT 11.645 27.115 11.815 27.285 ;
        RECT 12.105 27.115 12.275 27.285 ;
        RECT 12.565 27.115 12.735 27.285 ;
        RECT 13.025 27.115 13.195 27.285 ;
        RECT 13.485 27.115 13.655 27.285 ;
        RECT 13.945 27.115 14.115 27.285 ;
        RECT 14.405 27.115 14.575 27.285 ;
        RECT 14.865 27.115 15.035 27.285 ;
        RECT 15.325 27.115 15.495 27.285 ;
        RECT 15.785 27.115 15.955 27.285 ;
        RECT 16.245 27.115 16.415 27.285 ;
        RECT 16.705 27.115 16.875 27.285 ;
        RECT 17.165 27.115 17.335 27.285 ;
        RECT 17.625 27.115 17.795 27.285 ;
        RECT 18.085 27.115 18.255 27.285 ;
        RECT 18.545 27.115 18.715 27.285 ;
        RECT 19.005 27.115 19.175 27.285 ;
        RECT 19.465 27.115 19.635 27.285 ;
        RECT 19.925 27.115 20.095 27.285 ;
        RECT 20.385 27.115 20.555 27.285 ;
        RECT 20.845 27.115 21.015 27.285 ;
        RECT 21.305 27.115 21.475 27.285 ;
        RECT 21.765 27.115 21.935 27.285 ;
        RECT 22.225 27.115 22.395 27.285 ;
        RECT 22.685 27.115 22.855 27.285 ;
        RECT 23.145 27.115 23.315 27.285 ;
        RECT 23.605 27.115 23.775 27.285 ;
        RECT 24.065 27.115 24.235 27.285 ;
        RECT 24.525 27.115 24.695 27.285 ;
        RECT 24.985 27.115 25.155 27.285 ;
        RECT 25.445 27.115 25.615 27.285 ;
        RECT 25.905 27.115 26.075 27.285 ;
        RECT 26.365 27.115 26.535 27.285 ;
        RECT 26.825 27.115 26.995 27.285 ;
        RECT 27.285 27.115 27.455 27.285 ;
        RECT 27.745 27.115 27.915 27.285 ;
        RECT 28.205 27.115 28.375 27.285 ;
        RECT 28.665 27.115 28.835 27.285 ;
        RECT 29.125 27.115 29.295 27.285 ;
        RECT 29.585 27.115 29.755 27.285 ;
        RECT 30.045 27.115 30.215 27.285 ;
        RECT 30.505 27.115 30.675 27.285 ;
        RECT 30.965 27.115 31.135 27.285 ;
        RECT 31.425 27.115 31.595 27.285 ;
        RECT 31.885 27.115 32.055 27.285 ;
        RECT 32.345 27.115 32.515 27.285 ;
        RECT 32.805 27.115 32.975 27.285 ;
        RECT 33.265 27.115 33.435 27.285 ;
        RECT 2.445 21.675 2.615 21.845 ;
        RECT 2.905 21.675 3.075 21.845 ;
        RECT 3.365 21.675 3.535 21.845 ;
        RECT 3.825 21.675 3.995 21.845 ;
        RECT 4.285 21.675 4.455 21.845 ;
        RECT 4.745 21.675 4.915 21.845 ;
        RECT 5.205 21.675 5.375 21.845 ;
        RECT 5.665 21.675 5.835 21.845 ;
        RECT 6.125 21.675 6.295 21.845 ;
        RECT 6.585 21.675 6.755 21.845 ;
        RECT 7.045 21.675 7.215 21.845 ;
        RECT 7.505 21.675 7.675 21.845 ;
        RECT 7.965 21.675 8.135 21.845 ;
        RECT 8.425 21.675 8.595 21.845 ;
        RECT 8.885 21.675 9.055 21.845 ;
        RECT 9.345 21.675 9.515 21.845 ;
        RECT 9.805 21.675 9.975 21.845 ;
        RECT 10.265 21.675 10.435 21.845 ;
        RECT 10.725 21.675 10.895 21.845 ;
        RECT 11.185 21.675 11.355 21.845 ;
        RECT 11.645 21.675 11.815 21.845 ;
        RECT 12.105 21.675 12.275 21.845 ;
        RECT 12.565 21.675 12.735 21.845 ;
        RECT 13.025 21.675 13.195 21.845 ;
        RECT 13.485 21.675 13.655 21.845 ;
        RECT 13.945 21.675 14.115 21.845 ;
        RECT 14.405 21.675 14.575 21.845 ;
        RECT 14.865 21.675 15.035 21.845 ;
        RECT 15.325 21.675 15.495 21.845 ;
        RECT 15.785 21.675 15.955 21.845 ;
        RECT 16.245 21.675 16.415 21.845 ;
        RECT 16.705 21.675 16.875 21.845 ;
        RECT 17.165 21.675 17.335 21.845 ;
        RECT 17.625 21.675 17.795 21.845 ;
        RECT 18.085 21.675 18.255 21.845 ;
        RECT 18.545 21.675 18.715 21.845 ;
        RECT 19.005 21.675 19.175 21.845 ;
        RECT 19.465 21.675 19.635 21.845 ;
        RECT 19.925 21.675 20.095 21.845 ;
        RECT 20.385 21.675 20.555 21.845 ;
        RECT 20.845 21.675 21.015 21.845 ;
        RECT 21.305 21.675 21.475 21.845 ;
        RECT 21.765 21.675 21.935 21.845 ;
        RECT 22.225 21.675 22.395 21.845 ;
        RECT 22.685 21.675 22.855 21.845 ;
        RECT 23.145 21.675 23.315 21.845 ;
        RECT 23.605 21.675 23.775 21.845 ;
        RECT 24.065 21.675 24.235 21.845 ;
        RECT 24.525 21.675 24.695 21.845 ;
        RECT 24.985 21.675 25.155 21.845 ;
        RECT 25.445 21.675 25.615 21.845 ;
        RECT 25.905 21.675 26.075 21.845 ;
        RECT 26.365 21.675 26.535 21.845 ;
        RECT 26.825 21.675 26.995 21.845 ;
        RECT 27.285 21.675 27.455 21.845 ;
        RECT 27.745 21.675 27.915 21.845 ;
        RECT 28.205 21.675 28.375 21.845 ;
        RECT 28.665 21.675 28.835 21.845 ;
        RECT 29.125 21.675 29.295 21.845 ;
        RECT 29.585 21.675 29.755 21.845 ;
        RECT 30.045 21.675 30.215 21.845 ;
        RECT 30.505 21.675 30.675 21.845 ;
        RECT 30.965 21.675 31.135 21.845 ;
        RECT 31.425 21.675 31.595 21.845 ;
        RECT 31.885 21.675 32.055 21.845 ;
        RECT 32.345 21.675 32.515 21.845 ;
        RECT 32.805 21.675 32.975 21.845 ;
        RECT 33.265 21.675 33.435 21.845 ;
        RECT 2.445 16.235 2.615 16.405 ;
        RECT 2.905 16.235 3.075 16.405 ;
        RECT 3.365 16.235 3.535 16.405 ;
        RECT 3.825 16.235 3.995 16.405 ;
        RECT 4.285 16.235 4.455 16.405 ;
        RECT 4.745 16.235 4.915 16.405 ;
        RECT 5.205 16.235 5.375 16.405 ;
        RECT 5.665 16.235 5.835 16.405 ;
        RECT 6.125 16.235 6.295 16.405 ;
        RECT 6.585 16.235 6.755 16.405 ;
        RECT 7.045 16.235 7.215 16.405 ;
        RECT 7.505 16.235 7.675 16.405 ;
        RECT 7.965 16.235 8.135 16.405 ;
        RECT 8.425 16.235 8.595 16.405 ;
        RECT 8.885 16.235 9.055 16.405 ;
        RECT 9.345 16.235 9.515 16.405 ;
        RECT 9.805 16.235 9.975 16.405 ;
        RECT 10.265 16.235 10.435 16.405 ;
        RECT 10.725 16.235 10.895 16.405 ;
        RECT 11.185 16.235 11.355 16.405 ;
        RECT 11.645 16.235 11.815 16.405 ;
        RECT 12.105 16.235 12.275 16.405 ;
        RECT 12.565 16.235 12.735 16.405 ;
        RECT 13.025 16.235 13.195 16.405 ;
        RECT 13.485 16.235 13.655 16.405 ;
        RECT 13.945 16.235 14.115 16.405 ;
        RECT 14.405 16.235 14.575 16.405 ;
        RECT 14.865 16.235 15.035 16.405 ;
        RECT 15.325 16.235 15.495 16.405 ;
        RECT 15.785 16.235 15.955 16.405 ;
        RECT 16.245 16.235 16.415 16.405 ;
        RECT 16.705 16.235 16.875 16.405 ;
        RECT 17.165 16.235 17.335 16.405 ;
        RECT 17.625 16.235 17.795 16.405 ;
        RECT 18.085 16.235 18.255 16.405 ;
        RECT 18.545 16.235 18.715 16.405 ;
        RECT 19.005 16.235 19.175 16.405 ;
        RECT 19.465 16.235 19.635 16.405 ;
        RECT 19.925 16.235 20.095 16.405 ;
        RECT 20.385 16.235 20.555 16.405 ;
        RECT 20.845 16.235 21.015 16.405 ;
        RECT 21.305 16.235 21.475 16.405 ;
        RECT 21.765 16.235 21.935 16.405 ;
        RECT 22.225 16.235 22.395 16.405 ;
        RECT 22.685 16.235 22.855 16.405 ;
        RECT 23.145 16.235 23.315 16.405 ;
        RECT 23.605 16.235 23.775 16.405 ;
        RECT 24.065 16.235 24.235 16.405 ;
        RECT 24.525 16.235 24.695 16.405 ;
        RECT 24.985 16.235 25.155 16.405 ;
        RECT 25.445 16.235 25.615 16.405 ;
        RECT 25.905 16.235 26.075 16.405 ;
        RECT 26.365 16.235 26.535 16.405 ;
        RECT 26.825 16.235 26.995 16.405 ;
        RECT 27.285 16.235 27.455 16.405 ;
        RECT 27.745 16.235 27.915 16.405 ;
        RECT 28.205 16.235 28.375 16.405 ;
        RECT 28.665 16.235 28.835 16.405 ;
        RECT 29.125 16.235 29.295 16.405 ;
        RECT 29.585 16.235 29.755 16.405 ;
        RECT 30.045 16.235 30.215 16.405 ;
        RECT 30.505 16.235 30.675 16.405 ;
        RECT 30.965 16.235 31.135 16.405 ;
        RECT 31.425 16.235 31.595 16.405 ;
        RECT 31.885 16.235 32.055 16.405 ;
        RECT 32.345 16.235 32.515 16.405 ;
        RECT 32.805 16.235 32.975 16.405 ;
        RECT 33.265 16.235 33.435 16.405 ;
        RECT 2.445 10.795 2.615 10.965 ;
        RECT 2.905 10.795 3.075 10.965 ;
        RECT 3.365 10.795 3.535 10.965 ;
        RECT 3.825 10.795 3.995 10.965 ;
        RECT 4.285 10.795 4.455 10.965 ;
        RECT 4.745 10.795 4.915 10.965 ;
        RECT 5.205 10.795 5.375 10.965 ;
        RECT 5.665 10.795 5.835 10.965 ;
        RECT 6.125 10.795 6.295 10.965 ;
        RECT 6.585 10.795 6.755 10.965 ;
        RECT 7.045 10.795 7.215 10.965 ;
        RECT 7.505 10.795 7.675 10.965 ;
        RECT 7.965 10.795 8.135 10.965 ;
        RECT 8.425 10.795 8.595 10.965 ;
        RECT 8.885 10.795 9.055 10.965 ;
        RECT 9.345 10.795 9.515 10.965 ;
        RECT 9.805 10.795 9.975 10.965 ;
        RECT 10.265 10.795 10.435 10.965 ;
        RECT 10.725 10.795 10.895 10.965 ;
        RECT 11.185 10.795 11.355 10.965 ;
        RECT 11.645 10.795 11.815 10.965 ;
        RECT 12.105 10.795 12.275 10.965 ;
        RECT 12.565 10.795 12.735 10.965 ;
        RECT 13.025 10.795 13.195 10.965 ;
        RECT 13.485 10.795 13.655 10.965 ;
        RECT 13.945 10.795 14.115 10.965 ;
        RECT 14.405 10.795 14.575 10.965 ;
        RECT 14.865 10.795 15.035 10.965 ;
        RECT 15.325 10.795 15.495 10.965 ;
        RECT 15.785 10.795 15.955 10.965 ;
        RECT 16.245 10.795 16.415 10.965 ;
        RECT 16.705 10.795 16.875 10.965 ;
        RECT 17.165 10.795 17.335 10.965 ;
        RECT 17.625 10.795 17.795 10.965 ;
        RECT 18.085 10.795 18.255 10.965 ;
        RECT 18.545 10.795 18.715 10.965 ;
        RECT 19.005 10.795 19.175 10.965 ;
        RECT 19.465 10.795 19.635 10.965 ;
        RECT 19.925 10.795 20.095 10.965 ;
        RECT 20.385 10.795 20.555 10.965 ;
        RECT 20.845 10.795 21.015 10.965 ;
        RECT 21.305 10.795 21.475 10.965 ;
        RECT 21.765 10.795 21.935 10.965 ;
        RECT 22.225 10.795 22.395 10.965 ;
        RECT 22.685 10.795 22.855 10.965 ;
        RECT 23.145 10.795 23.315 10.965 ;
        RECT 23.605 10.795 23.775 10.965 ;
        RECT 24.065 10.795 24.235 10.965 ;
        RECT 24.525 10.795 24.695 10.965 ;
        RECT 24.985 10.795 25.155 10.965 ;
        RECT 25.445 10.795 25.615 10.965 ;
        RECT 25.905 10.795 26.075 10.965 ;
        RECT 26.365 10.795 26.535 10.965 ;
        RECT 26.825 10.795 26.995 10.965 ;
        RECT 27.285 10.795 27.455 10.965 ;
        RECT 27.745 10.795 27.915 10.965 ;
        RECT 28.205 10.795 28.375 10.965 ;
        RECT 28.665 10.795 28.835 10.965 ;
        RECT 29.125 10.795 29.295 10.965 ;
        RECT 29.585 10.795 29.755 10.965 ;
        RECT 30.045 10.795 30.215 10.965 ;
        RECT 30.505 10.795 30.675 10.965 ;
        RECT 30.965 10.795 31.135 10.965 ;
        RECT 31.425 10.795 31.595 10.965 ;
        RECT 31.885 10.795 32.055 10.965 ;
        RECT 32.345 10.795 32.515 10.965 ;
        RECT 32.805 10.795 32.975 10.965 ;
        RECT 33.265 10.795 33.435 10.965 ;
        RECT 2.445 5.355 2.615 5.525 ;
        RECT 2.905 5.355 3.075 5.525 ;
        RECT 3.365 5.355 3.535 5.525 ;
        RECT 3.825 5.355 3.995 5.525 ;
        RECT 4.285 5.355 4.455 5.525 ;
        RECT 4.745 5.355 4.915 5.525 ;
        RECT 5.205 5.355 5.375 5.525 ;
        RECT 5.665 5.355 5.835 5.525 ;
        RECT 6.125 5.355 6.295 5.525 ;
        RECT 6.585 5.355 6.755 5.525 ;
        RECT 7.045 5.355 7.215 5.525 ;
        RECT 7.505 5.355 7.675 5.525 ;
        RECT 7.965 5.355 8.135 5.525 ;
        RECT 8.425 5.355 8.595 5.525 ;
        RECT 8.885 5.355 9.055 5.525 ;
        RECT 9.345 5.355 9.515 5.525 ;
        RECT 9.805 5.355 9.975 5.525 ;
        RECT 10.265 5.355 10.435 5.525 ;
        RECT 10.725 5.355 10.895 5.525 ;
        RECT 11.185 5.355 11.355 5.525 ;
        RECT 11.645 5.355 11.815 5.525 ;
        RECT 12.105 5.355 12.275 5.525 ;
        RECT 12.565 5.355 12.735 5.525 ;
        RECT 13.025 5.355 13.195 5.525 ;
        RECT 13.485 5.355 13.655 5.525 ;
        RECT 13.945 5.355 14.115 5.525 ;
        RECT 14.405 5.355 14.575 5.525 ;
        RECT 14.865 5.355 15.035 5.525 ;
        RECT 15.325 5.355 15.495 5.525 ;
        RECT 15.785 5.355 15.955 5.525 ;
        RECT 16.245 5.355 16.415 5.525 ;
        RECT 16.705 5.355 16.875 5.525 ;
        RECT 17.165 5.355 17.335 5.525 ;
        RECT 17.625 5.355 17.795 5.525 ;
        RECT 18.085 5.355 18.255 5.525 ;
        RECT 18.545 5.355 18.715 5.525 ;
        RECT 19.005 5.355 19.175 5.525 ;
        RECT 19.465 5.355 19.635 5.525 ;
        RECT 19.925 5.355 20.095 5.525 ;
        RECT 20.385 5.355 20.555 5.525 ;
        RECT 20.845 5.355 21.015 5.525 ;
        RECT 21.305 5.355 21.475 5.525 ;
        RECT 21.765 5.355 21.935 5.525 ;
        RECT 22.225 5.355 22.395 5.525 ;
        RECT 22.685 5.355 22.855 5.525 ;
        RECT 23.145 5.355 23.315 5.525 ;
        RECT 23.605 5.355 23.775 5.525 ;
        RECT 24.065 5.355 24.235 5.525 ;
        RECT 24.525 5.355 24.695 5.525 ;
        RECT 24.985 5.355 25.155 5.525 ;
        RECT 25.445 5.355 25.615 5.525 ;
        RECT 25.905 5.355 26.075 5.525 ;
        RECT 26.365 5.355 26.535 5.525 ;
        RECT 26.825 5.355 26.995 5.525 ;
        RECT 27.285 5.355 27.455 5.525 ;
        RECT 27.745 5.355 27.915 5.525 ;
        RECT 28.205 5.355 28.375 5.525 ;
        RECT 28.665 5.355 28.835 5.525 ;
        RECT 29.125 5.355 29.295 5.525 ;
        RECT 29.585 5.355 29.755 5.525 ;
        RECT 30.045 5.355 30.215 5.525 ;
        RECT 30.505 5.355 30.675 5.525 ;
        RECT 30.965 5.355 31.135 5.525 ;
        RECT 31.425 5.355 31.595 5.525 ;
        RECT 31.885 5.355 32.055 5.525 ;
        RECT 32.345 5.355 32.515 5.525 ;
        RECT 32.805 5.355 32.975 5.525 ;
        RECT 33.265 5.355 33.435 5.525 ;
      LAYER met1 ;
        RECT -9.700 37.840 45.580 38.320 ;
        RECT -9.700 32.400 45.580 32.880 ;
        RECT -9.700 26.960 45.580 27.440 ;
        RECT -9.700 21.520 45.580 22.000 ;
        RECT -9.700 16.080 45.580 16.560 ;
        RECT -9.700 10.640 45.580 11.120 ;
        RECT -9.700 5.200 45.580 5.680 ;
      LAYER via ;
        RECT -3.850 37.950 -3.590 38.210 ;
        RECT -3.530 37.950 -3.270 38.210 ;
        RECT -3.210 37.950 -2.950 38.210 ;
        RECT -2.890 37.950 -2.630 38.210 ;
        RECT -2.570 37.950 -2.310 38.210 ;
        RECT -2.250 37.950 -1.990 38.210 ;
        RECT -1.930 37.950 -1.670 38.210 ;
        RECT -1.610 37.950 -1.350 38.210 ;
        RECT -1.290 37.950 -1.030 38.210 ;
        RECT -0.970 37.950 -0.710 38.210 ;
        RECT -0.650 37.950 -0.390 38.210 ;
        RECT -0.330 37.950 -0.070 38.210 ;
        RECT -0.010 37.950 0.250 38.210 ;
        RECT 35.630 37.950 35.890 38.210 ;
        RECT 35.950 37.950 36.210 38.210 ;
        RECT 36.270 37.950 36.530 38.210 ;
        RECT 36.590 37.950 36.850 38.210 ;
        RECT 36.910 37.950 37.170 38.210 ;
        RECT 37.230 37.950 37.490 38.210 ;
        RECT 37.550 37.950 37.810 38.210 ;
        RECT 37.870 37.950 38.130 38.210 ;
        RECT 38.190 37.950 38.450 38.210 ;
        RECT 38.510 37.950 38.770 38.210 ;
        RECT 38.830 37.950 39.090 38.210 ;
        RECT 39.150 37.950 39.410 38.210 ;
        RECT 39.470 37.950 39.730 38.210 ;
        RECT -3.850 32.510 -3.590 32.770 ;
        RECT -3.530 32.510 -3.270 32.770 ;
        RECT -3.210 32.510 -2.950 32.770 ;
        RECT -2.890 32.510 -2.630 32.770 ;
        RECT -2.570 32.510 -2.310 32.770 ;
        RECT -2.250 32.510 -1.990 32.770 ;
        RECT -1.930 32.510 -1.670 32.770 ;
        RECT -1.610 32.510 -1.350 32.770 ;
        RECT -1.290 32.510 -1.030 32.770 ;
        RECT -0.970 32.510 -0.710 32.770 ;
        RECT -0.650 32.510 -0.390 32.770 ;
        RECT -0.330 32.510 -0.070 32.770 ;
        RECT -0.010 32.510 0.250 32.770 ;
        RECT 35.630 32.510 35.890 32.770 ;
        RECT 35.950 32.510 36.210 32.770 ;
        RECT 36.270 32.510 36.530 32.770 ;
        RECT 36.590 32.510 36.850 32.770 ;
        RECT 36.910 32.510 37.170 32.770 ;
        RECT 37.230 32.510 37.490 32.770 ;
        RECT 37.550 32.510 37.810 32.770 ;
        RECT 37.870 32.510 38.130 32.770 ;
        RECT 38.190 32.510 38.450 32.770 ;
        RECT 38.510 32.510 38.770 32.770 ;
        RECT 38.830 32.510 39.090 32.770 ;
        RECT 39.150 32.510 39.410 32.770 ;
        RECT 39.470 32.510 39.730 32.770 ;
        RECT -3.850 27.070 -3.590 27.330 ;
        RECT -3.530 27.070 -3.270 27.330 ;
        RECT -3.210 27.070 -2.950 27.330 ;
        RECT -2.890 27.070 -2.630 27.330 ;
        RECT -2.570 27.070 -2.310 27.330 ;
        RECT -2.250 27.070 -1.990 27.330 ;
        RECT -1.930 27.070 -1.670 27.330 ;
        RECT -1.610 27.070 -1.350 27.330 ;
        RECT -1.290 27.070 -1.030 27.330 ;
        RECT -0.970 27.070 -0.710 27.330 ;
        RECT -0.650 27.070 -0.390 27.330 ;
        RECT -0.330 27.070 -0.070 27.330 ;
        RECT -0.010 27.070 0.250 27.330 ;
        RECT 35.630 27.070 35.890 27.330 ;
        RECT 35.950 27.070 36.210 27.330 ;
        RECT 36.270 27.070 36.530 27.330 ;
        RECT 36.590 27.070 36.850 27.330 ;
        RECT 36.910 27.070 37.170 27.330 ;
        RECT 37.230 27.070 37.490 27.330 ;
        RECT 37.550 27.070 37.810 27.330 ;
        RECT 37.870 27.070 38.130 27.330 ;
        RECT 38.190 27.070 38.450 27.330 ;
        RECT 38.510 27.070 38.770 27.330 ;
        RECT 38.830 27.070 39.090 27.330 ;
        RECT 39.150 27.070 39.410 27.330 ;
        RECT 39.470 27.070 39.730 27.330 ;
        RECT -3.850 21.630 -3.590 21.890 ;
        RECT -3.530 21.630 -3.270 21.890 ;
        RECT -3.210 21.630 -2.950 21.890 ;
        RECT -2.890 21.630 -2.630 21.890 ;
        RECT -2.570 21.630 -2.310 21.890 ;
        RECT -2.250 21.630 -1.990 21.890 ;
        RECT -1.930 21.630 -1.670 21.890 ;
        RECT -1.610 21.630 -1.350 21.890 ;
        RECT -1.290 21.630 -1.030 21.890 ;
        RECT -0.970 21.630 -0.710 21.890 ;
        RECT -0.650 21.630 -0.390 21.890 ;
        RECT -0.330 21.630 -0.070 21.890 ;
        RECT -0.010 21.630 0.250 21.890 ;
        RECT 35.630 21.630 35.890 21.890 ;
        RECT 35.950 21.630 36.210 21.890 ;
        RECT 36.270 21.630 36.530 21.890 ;
        RECT 36.590 21.630 36.850 21.890 ;
        RECT 36.910 21.630 37.170 21.890 ;
        RECT 37.230 21.630 37.490 21.890 ;
        RECT 37.550 21.630 37.810 21.890 ;
        RECT 37.870 21.630 38.130 21.890 ;
        RECT 38.190 21.630 38.450 21.890 ;
        RECT 38.510 21.630 38.770 21.890 ;
        RECT 38.830 21.630 39.090 21.890 ;
        RECT 39.150 21.630 39.410 21.890 ;
        RECT 39.470 21.630 39.730 21.890 ;
        RECT -3.850 16.190 -3.590 16.450 ;
        RECT -3.530 16.190 -3.270 16.450 ;
        RECT -3.210 16.190 -2.950 16.450 ;
        RECT -2.890 16.190 -2.630 16.450 ;
        RECT -2.570 16.190 -2.310 16.450 ;
        RECT -2.250 16.190 -1.990 16.450 ;
        RECT -1.930 16.190 -1.670 16.450 ;
        RECT -1.610 16.190 -1.350 16.450 ;
        RECT -1.290 16.190 -1.030 16.450 ;
        RECT -0.970 16.190 -0.710 16.450 ;
        RECT -0.650 16.190 -0.390 16.450 ;
        RECT -0.330 16.190 -0.070 16.450 ;
        RECT -0.010 16.190 0.250 16.450 ;
        RECT 35.630 16.190 35.890 16.450 ;
        RECT 35.950 16.190 36.210 16.450 ;
        RECT 36.270 16.190 36.530 16.450 ;
        RECT 36.590 16.190 36.850 16.450 ;
        RECT 36.910 16.190 37.170 16.450 ;
        RECT 37.230 16.190 37.490 16.450 ;
        RECT 37.550 16.190 37.810 16.450 ;
        RECT 37.870 16.190 38.130 16.450 ;
        RECT 38.190 16.190 38.450 16.450 ;
        RECT 38.510 16.190 38.770 16.450 ;
        RECT 38.830 16.190 39.090 16.450 ;
        RECT 39.150 16.190 39.410 16.450 ;
        RECT 39.470 16.190 39.730 16.450 ;
        RECT -3.850 10.750 -3.590 11.010 ;
        RECT -3.530 10.750 -3.270 11.010 ;
        RECT -3.210 10.750 -2.950 11.010 ;
        RECT -2.890 10.750 -2.630 11.010 ;
        RECT -2.570 10.750 -2.310 11.010 ;
        RECT -2.250 10.750 -1.990 11.010 ;
        RECT -1.930 10.750 -1.670 11.010 ;
        RECT -1.610 10.750 -1.350 11.010 ;
        RECT -1.290 10.750 -1.030 11.010 ;
        RECT -0.970 10.750 -0.710 11.010 ;
        RECT -0.650 10.750 -0.390 11.010 ;
        RECT -0.330 10.750 -0.070 11.010 ;
        RECT -0.010 10.750 0.250 11.010 ;
        RECT 35.630 10.750 35.890 11.010 ;
        RECT 35.950 10.750 36.210 11.010 ;
        RECT 36.270 10.750 36.530 11.010 ;
        RECT 36.590 10.750 36.850 11.010 ;
        RECT 36.910 10.750 37.170 11.010 ;
        RECT 37.230 10.750 37.490 11.010 ;
        RECT 37.550 10.750 37.810 11.010 ;
        RECT 37.870 10.750 38.130 11.010 ;
        RECT 38.190 10.750 38.450 11.010 ;
        RECT 38.510 10.750 38.770 11.010 ;
        RECT 38.830 10.750 39.090 11.010 ;
        RECT 39.150 10.750 39.410 11.010 ;
        RECT 39.470 10.750 39.730 11.010 ;
        RECT -3.850 5.310 -3.590 5.570 ;
        RECT -3.530 5.310 -3.270 5.570 ;
        RECT -3.210 5.310 -2.950 5.570 ;
        RECT -2.890 5.310 -2.630 5.570 ;
        RECT -2.570 5.310 -2.310 5.570 ;
        RECT -2.250 5.310 -1.990 5.570 ;
        RECT -1.930 5.310 -1.670 5.570 ;
        RECT -1.610 5.310 -1.350 5.570 ;
        RECT -1.290 5.310 -1.030 5.570 ;
        RECT -0.970 5.310 -0.710 5.570 ;
        RECT -0.650 5.310 -0.390 5.570 ;
        RECT -0.330 5.310 -0.070 5.570 ;
        RECT -0.010 5.310 0.250 5.570 ;
        RECT 35.630 5.310 35.890 5.570 ;
        RECT 35.950 5.310 36.210 5.570 ;
        RECT 36.270 5.310 36.530 5.570 ;
        RECT 36.590 5.310 36.850 5.570 ;
        RECT 36.910 5.310 37.170 5.570 ;
        RECT 37.230 5.310 37.490 5.570 ;
        RECT 37.550 5.310 37.810 5.570 ;
        RECT 37.870 5.310 38.130 5.570 ;
        RECT 38.190 5.310 38.450 5.570 ;
        RECT 38.510 5.310 38.770 5.570 ;
        RECT 38.830 5.310 39.090 5.570 ;
        RECT 39.150 5.310 39.410 5.570 ;
        RECT 39.470 5.310 39.730 5.570 ;
      LAYER met2 ;
        RECT -3.850 37.840 0.250 38.320 ;
        RECT 35.630 37.840 39.730 38.320 ;
        RECT -3.850 32.400 0.250 32.880 ;
        RECT 35.630 32.400 39.730 32.880 ;
        RECT -3.850 26.960 0.250 27.440 ;
        RECT 35.630 26.960 39.730 27.440 ;
        RECT -3.850 21.520 0.250 22.000 ;
        RECT 35.630 21.520 39.730 22.000 ;
        RECT -3.850 16.080 0.250 16.560 ;
        RECT 35.630 16.080 39.730 16.560 ;
        RECT -3.850 10.640 0.250 11.120 ;
        RECT 35.630 10.640 39.730 11.120 ;
        RECT -3.850 5.200 0.250 5.680 ;
        RECT 35.630 5.200 39.730 5.680 ;
      LAYER via2 ;
        RECT -3.740 37.940 -3.460 38.220 ;
        RECT -3.340 37.940 -3.060 38.220 ;
        RECT -2.940 37.940 -2.660 38.220 ;
        RECT -2.540 37.940 -2.260 38.220 ;
        RECT -2.140 37.940 -1.860 38.220 ;
        RECT -1.740 37.940 -1.460 38.220 ;
        RECT -1.340 37.940 -1.060 38.220 ;
        RECT -0.940 37.940 -0.660 38.220 ;
        RECT -0.540 37.940 -0.260 38.220 ;
        RECT -0.140 37.940 0.140 38.220 ;
        RECT 35.740 37.940 36.020 38.220 ;
        RECT 36.140 37.940 36.420 38.220 ;
        RECT 36.540 37.940 36.820 38.220 ;
        RECT 36.940 37.940 37.220 38.220 ;
        RECT 37.340 37.940 37.620 38.220 ;
        RECT 37.740 37.940 38.020 38.220 ;
        RECT 38.140 37.940 38.420 38.220 ;
        RECT 38.540 37.940 38.820 38.220 ;
        RECT 38.940 37.940 39.220 38.220 ;
        RECT 39.340 37.940 39.620 38.220 ;
        RECT -3.740 32.500 -3.460 32.780 ;
        RECT -3.340 32.500 -3.060 32.780 ;
        RECT -2.940 32.500 -2.660 32.780 ;
        RECT -2.540 32.500 -2.260 32.780 ;
        RECT -2.140 32.500 -1.860 32.780 ;
        RECT -1.740 32.500 -1.460 32.780 ;
        RECT -1.340 32.500 -1.060 32.780 ;
        RECT -0.940 32.500 -0.660 32.780 ;
        RECT -0.540 32.500 -0.260 32.780 ;
        RECT -0.140 32.500 0.140 32.780 ;
        RECT 35.740 32.500 36.020 32.780 ;
        RECT 36.140 32.500 36.420 32.780 ;
        RECT 36.540 32.500 36.820 32.780 ;
        RECT 36.940 32.500 37.220 32.780 ;
        RECT 37.340 32.500 37.620 32.780 ;
        RECT 37.740 32.500 38.020 32.780 ;
        RECT 38.140 32.500 38.420 32.780 ;
        RECT 38.540 32.500 38.820 32.780 ;
        RECT 38.940 32.500 39.220 32.780 ;
        RECT 39.340 32.500 39.620 32.780 ;
        RECT -3.740 27.060 -3.460 27.340 ;
        RECT -3.340 27.060 -3.060 27.340 ;
        RECT -2.940 27.060 -2.660 27.340 ;
        RECT -2.540 27.060 -2.260 27.340 ;
        RECT -2.140 27.060 -1.860 27.340 ;
        RECT -1.740 27.060 -1.460 27.340 ;
        RECT -1.340 27.060 -1.060 27.340 ;
        RECT -0.940 27.060 -0.660 27.340 ;
        RECT -0.540 27.060 -0.260 27.340 ;
        RECT -0.140 27.060 0.140 27.340 ;
        RECT 35.740 27.060 36.020 27.340 ;
        RECT 36.140 27.060 36.420 27.340 ;
        RECT 36.540 27.060 36.820 27.340 ;
        RECT 36.940 27.060 37.220 27.340 ;
        RECT 37.340 27.060 37.620 27.340 ;
        RECT 37.740 27.060 38.020 27.340 ;
        RECT 38.140 27.060 38.420 27.340 ;
        RECT 38.540 27.060 38.820 27.340 ;
        RECT 38.940 27.060 39.220 27.340 ;
        RECT 39.340 27.060 39.620 27.340 ;
        RECT -3.740 21.620 -3.460 21.900 ;
        RECT -3.340 21.620 -3.060 21.900 ;
        RECT -2.940 21.620 -2.660 21.900 ;
        RECT -2.540 21.620 -2.260 21.900 ;
        RECT -2.140 21.620 -1.860 21.900 ;
        RECT -1.740 21.620 -1.460 21.900 ;
        RECT -1.340 21.620 -1.060 21.900 ;
        RECT -0.940 21.620 -0.660 21.900 ;
        RECT -0.540 21.620 -0.260 21.900 ;
        RECT -0.140 21.620 0.140 21.900 ;
        RECT 35.740 21.620 36.020 21.900 ;
        RECT 36.140 21.620 36.420 21.900 ;
        RECT 36.540 21.620 36.820 21.900 ;
        RECT 36.940 21.620 37.220 21.900 ;
        RECT 37.340 21.620 37.620 21.900 ;
        RECT 37.740 21.620 38.020 21.900 ;
        RECT 38.140 21.620 38.420 21.900 ;
        RECT 38.540 21.620 38.820 21.900 ;
        RECT 38.940 21.620 39.220 21.900 ;
        RECT 39.340 21.620 39.620 21.900 ;
        RECT -3.740 16.180 -3.460 16.460 ;
        RECT -3.340 16.180 -3.060 16.460 ;
        RECT -2.940 16.180 -2.660 16.460 ;
        RECT -2.540 16.180 -2.260 16.460 ;
        RECT -2.140 16.180 -1.860 16.460 ;
        RECT -1.740 16.180 -1.460 16.460 ;
        RECT -1.340 16.180 -1.060 16.460 ;
        RECT -0.940 16.180 -0.660 16.460 ;
        RECT -0.540 16.180 -0.260 16.460 ;
        RECT -0.140 16.180 0.140 16.460 ;
        RECT 35.740 16.180 36.020 16.460 ;
        RECT 36.140 16.180 36.420 16.460 ;
        RECT 36.540 16.180 36.820 16.460 ;
        RECT 36.940 16.180 37.220 16.460 ;
        RECT 37.340 16.180 37.620 16.460 ;
        RECT 37.740 16.180 38.020 16.460 ;
        RECT 38.140 16.180 38.420 16.460 ;
        RECT 38.540 16.180 38.820 16.460 ;
        RECT 38.940 16.180 39.220 16.460 ;
        RECT 39.340 16.180 39.620 16.460 ;
        RECT -3.740 10.740 -3.460 11.020 ;
        RECT -3.340 10.740 -3.060 11.020 ;
        RECT -2.940 10.740 -2.660 11.020 ;
        RECT -2.540 10.740 -2.260 11.020 ;
        RECT -2.140 10.740 -1.860 11.020 ;
        RECT -1.740 10.740 -1.460 11.020 ;
        RECT -1.340 10.740 -1.060 11.020 ;
        RECT -0.940 10.740 -0.660 11.020 ;
        RECT -0.540 10.740 -0.260 11.020 ;
        RECT -0.140 10.740 0.140 11.020 ;
        RECT 35.740 10.740 36.020 11.020 ;
        RECT 36.140 10.740 36.420 11.020 ;
        RECT 36.540 10.740 36.820 11.020 ;
        RECT 36.940 10.740 37.220 11.020 ;
        RECT 37.340 10.740 37.620 11.020 ;
        RECT 37.740 10.740 38.020 11.020 ;
        RECT 38.140 10.740 38.420 11.020 ;
        RECT 38.540 10.740 38.820 11.020 ;
        RECT 38.940 10.740 39.220 11.020 ;
        RECT 39.340 10.740 39.620 11.020 ;
        RECT -3.740 5.300 -3.460 5.580 ;
        RECT -3.340 5.300 -3.060 5.580 ;
        RECT -2.940 5.300 -2.660 5.580 ;
        RECT -2.540 5.300 -2.260 5.580 ;
        RECT -2.140 5.300 -1.860 5.580 ;
        RECT -1.740 5.300 -1.460 5.580 ;
        RECT -1.340 5.300 -1.060 5.580 ;
        RECT -0.940 5.300 -0.660 5.580 ;
        RECT -0.540 5.300 -0.260 5.580 ;
        RECT -0.140 5.300 0.140 5.580 ;
        RECT 35.740 5.300 36.020 5.580 ;
        RECT 36.140 5.300 36.420 5.580 ;
        RECT 36.540 5.300 36.820 5.580 ;
        RECT 36.940 5.300 37.220 5.580 ;
        RECT 37.340 5.300 37.620 5.580 ;
        RECT 37.740 5.300 38.020 5.580 ;
        RECT 38.140 5.300 38.420 5.580 ;
        RECT 38.540 5.300 38.820 5.580 ;
        RECT 38.940 5.300 39.220 5.580 ;
        RECT 39.340 5.300 39.620 5.580 ;
      LAYER met3 ;
        RECT -3.900 37.915 0.300 38.245 ;
        RECT 35.580 37.915 39.780 38.245 ;
        RECT -3.900 32.475 0.300 32.805 ;
        RECT 35.580 32.475 39.780 32.805 ;
        RECT -3.900 27.035 0.300 27.365 ;
        RECT 35.580 27.035 39.780 27.365 ;
        RECT -3.900 21.595 0.300 21.925 ;
        RECT 35.580 21.595 39.780 21.925 ;
        RECT -3.900 16.155 0.300 16.485 ;
        RECT 35.580 16.155 39.780 16.485 ;
        RECT -3.900 10.715 0.300 11.045 ;
        RECT 35.580 10.715 39.780 11.045 ;
        RECT -3.900 5.275 0.300 5.605 ;
        RECT 35.580 5.275 39.780 5.605 ;
      LAYER via3 ;
        RECT -3.760 37.920 -3.440 38.240 ;
        RECT -3.360 37.920 -3.040 38.240 ;
        RECT -2.960 37.920 -2.640 38.240 ;
        RECT -2.560 37.920 -2.240 38.240 ;
        RECT -2.160 37.920 -1.840 38.240 ;
        RECT -1.760 37.920 -1.440 38.240 ;
        RECT -1.360 37.920 -1.040 38.240 ;
        RECT -0.960 37.920 -0.640 38.240 ;
        RECT -0.560 37.920 -0.240 38.240 ;
        RECT -0.160 37.920 0.160 38.240 ;
        RECT 35.720 37.920 36.040 38.240 ;
        RECT 36.120 37.920 36.440 38.240 ;
        RECT 36.520 37.920 36.840 38.240 ;
        RECT 36.920 37.920 37.240 38.240 ;
        RECT 37.320 37.920 37.640 38.240 ;
        RECT 37.720 37.920 38.040 38.240 ;
        RECT 38.120 37.920 38.440 38.240 ;
        RECT 38.520 37.920 38.840 38.240 ;
        RECT 38.920 37.920 39.240 38.240 ;
        RECT 39.320 37.920 39.640 38.240 ;
        RECT -3.760 32.480 -3.440 32.800 ;
        RECT -3.360 32.480 -3.040 32.800 ;
        RECT -2.960 32.480 -2.640 32.800 ;
        RECT -2.560 32.480 -2.240 32.800 ;
        RECT -2.160 32.480 -1.840 32.800 ;
        RECT -1.760 32.480 -1.440 32.800 ;
        RECT -1.360 32.480 -1.040 32.800 ;
        RECT -0.960 32.480 -0.640 32.800 ;
        RECT -0.560 32.480 -0.240 32.800 ;
        RECT -0.160 32.480 0.160 32.800 ;
        RECT 35.720 32.480 36.040 32.800 ;
        RECT 36.120 32.480 36.440 32.800 ;
        RECT 36.520 32.480 36.840 32.800 ;
        RECT 36.920 32.480 37.240 32.800 ;
        RECT 37.320 32.480 37.640 32.800 ;
        RECT 37.720 32.480 38.040 32.800 ;
        RECT 38.120 32.480 38.440 32.800 ;
        RECT 38.520 32.480 38.840 32.800 ;
        RECT 38.920 32.480 39.240 32.800 ;
        RECT 39.320 32.480 39.640 32.800 ;
        RECT -3.760 27.040 -3.440 27.360 ;
        RECT -3.360 27.040 -3.040 27.360 ;
        RECT -2.960 27.040 -2.640 27.360 ;
        RECT -2.560 27.040 -2.240 27.360 ;
        RECT -2.160 27.040 -1.840 27.360 ;
        RECT -1.760 27.040 -1.440 27.360 ;
        RECT -1.360 27.040 -1.040 27.360 ;
        RECT -0.960 27.040 -0.640 27.360 ;
        RECT -0.560 27.040 -0.240 27.360 ;
        RECT -0.160 27.040 0.160 27.360 ;
        RECT 35.720 27.040 36.040 27.360 ;
        RECT 36.120 27.040 36.440 27.360 ;
        RECT 36.520 27.040 36.840 27.360 ;
        RECT 36.920 27.040 37.240 27.360 ;
        RECT 37.320 27.040 37.640 27.360 ;
        RECT 37.720 27.040 38.040 27.360 ;
        RECT 38.120 27.040 38.440 27.360 ;
        RECT 38.520 27.040 38.840 27.360 ;
        RECT 38.920 27.040 39.240 27.360 ;
        RECT 39.320 27.040 39.640 27.360 ;
        RECT -3.760 21.600 -3.440 21.920 ;
        RECT -3.360 21.600 -3.040 21.920 ;
        RECT -2.960 21.600 -2.640 21.920 ;
        RECT -2.560 21.600 -2.240 21.920 ;
        RECT -2.160 21.600 -1.840 21.920 ;
        RECT -1.760 21.600 -1.440 21.920 ;
        RECT -1.360 21.600 -1.040 21.920 ;
        RECT -0.960 21.600 -0.640 21.920 ;
        RECT -0.560 21.600 -0.240 21.920 ;
        RECT -0.160 21.600 0.160 21.920 ;
        RECT 35.720 21.600 36.040 21.920 ;
        RECT 36.120 21.600 36.440 21.920 ;
        RECT 36.520 21.600 36.840 21.920 ;
        RECT 36.920 21.600 37.240 21.920 ;
        RECT 37.320 21.600 37.640 21.920 ;
        RECT 37.720 21.600 38.040 21.920 ;
        RECT 38.120 21.600 38.440 21.920 ;
        RECT 38.520 21.600 38.840 21.920 ;
        RECT 38.920 21.600 39.240 21.920 ;
        RECT 39.320 21.600 39.640 21.920 ;
        RECT -3.760 16.160 -3.440 16.480 ;
        RECT -3.360 16.160 -3.040 16.480 ;
        RECT -2.960 16.160 -2.640 16.480 ;
        RECT -2.560 16.160 -2.240 16.480 ;
        RECT -2.160 16.160 -1.840 16.480 ;
        RECT -1.760 16.160 -1.440 16.480 ;
        RECT -1.360 16.160 -1.040 16.480 ;
        RECT -0.960 16.160 -0.640 16.480 ;
        RECT -0.560 16.160 -0.240 16.480 ;
        RECT -0.160 16.160 0.160 16.480 ;
        RECT 35.720 16.160 36.040 16.480 ;
        RECT 36.120 16.160 36.440 16.480 ;
        RECT 36.520 16.160 36.840 16.480 ;
        RECT 36.920 16.160 37.240 16.480 ;
        RECT 37.320 16.160 37.640 16.480 ;
        RECT 37.720 16.160 38.040 16.480 ;
        RECT 38.120 16.160 38.440 16.480 ;
        RECT 38.520 16.160 38.840 16.480 ;
        RECT 38.920 16.160 39.240 16.480 ;
        RECT 39.320 16.160 39.640 16.480 ;
        RECT -3.760 10.720 -3.440 11.040 ;
        RECT -3.360 10.720 -3.040 11.040 ;
        RECT -2.960 10.720 -2.640 11.040 ;
        RECT -2.560 10.720 -2.240 11.040 ;
        RECT -2.160 10.720 -1.840 11.040 ;
        RECT -1.760 10.720 -1.440 11.040 ;
        RECT -1.360 10.720 -1.040 11.040 ;
        RECT -0.960 10.720 -0.640 11.040 ;
        RECT -0.560 10.720 -0.240 11.040 ;
        RECT -0.160 10.720 0.160 11.040 ;
        RECT 35.720 10.720 36.040 11.040 ;
        RECT 36.120 10.720 36.440 11.040 ;
        RECT 36.520 10.720 36.840 11.040 ;
        RECT 36.920 10.720 37.240 11.040 ;
        RECT 37.320 10.720 37.640 11.040 ;
        RECT 37.720 10.720 38.040 11.040 ;
        RECT 38.120 10.720 38.440 11.040 ;
        RECT 38.520 10.720 38.840 11.040 ;
        RECT 38.920 10.720 39.240 11.040 ;
        RECT 39.320 10.720 39.640 11.040 ;
        RECT -3.760 5.280 -3.440 5.600 ;
        RECT -3.360 5.280 -3.040 5.600 ;
        RECT -2.960 5.280 -2.640 5.600 ;
        RECT -2.560 5.280 -2.240 5.600 ;
        RECT -2.160 5.280 -1.840 5.600 ;
        RECT -1.760 5.280 -1.440 5.600 ;
        RECT -1.360 5.280 -1.040 5.600 ;
        RECT -0.960 5.280 -0.640 5.600 ;
        RECT -0.560 5.280 -0.240 5.600 ;
        RECT -0.160 5.280 0.160 5.600 ;
        RECT 35.720 5.280 36.040 5.600 ;
        RECT 36.120 5.280 36.440 5.600 ;
        RECT 36.520 5.280 36.840 5.600 ;
        RECT 36.920 5.280 37.240 5.600 ;
        RECT 37.320 5.280 37.640 5.600 ;
        RECT 37.720 5.280 38.040 5.600 ;
        RECT 38.120 5.280 38.440 5.600 ;
        RECT 38.520 5.280 38.840 5.600 ;
        RECT 38.920 5.280 39.240 5.600 ;
        RECT 39.320 5.280 39.640 5.600 ;
      LAYER met4 ;
        RECT -3.900 -3.480 0.300 44.280 ;
        RECT 35.580 -3.480 39.780 44.280 ;
      LAYER via4 ;
        RECT -3.190 40.790 -0.410 43.570 ;
        RECT -3.190 35.490 -2.010 36.670 ;
        RECT -1.590 35.490 -0.410 36.670 ;
        RECT -3.190 -2.770 -0.410 0.010 ;
        RECT 36.290 40.790 39.070 43.570 ;
        RECT 36.290 35.490 37.470 36.670 ;
        RECT 37.890 35.490 39.070 36.670 ;
        RECT 36.290 -2.770 39.070 0.010 ;
      LAYER met5 ;
        RECT -3.900 40.080 39.780 44.280 ;
        RECT -9.700 35.280 45.580 36.880 ;
        RECT -3.900 -3.480 39.780 0.720 ;
    END
  END VPWR
  PIN VGND
    USE GROUND ;
    PORT
      LAYER pwell ;
        RECT 16.115 35.550 16.545 36.335 ;
        RECT 29.915 35.550 30.345 36.335 ;
        RECT 29.915 34.385 30.345 35.170 ;
        RECT 16.115 30.110 16.545 30.895 ;
        RECT 29.915 28.945 30.345 29.730 ;
        RECT 16.115 24.670 16.545 25.455 ;
        RECT 29.915 23.505 30.345 24.290 ;
        RECT 16.115 19.230 16.545 20.015 ;
        RECT 29.915 18.065 30.345 18.850 ;
        RECT 16.115 13.790 16.545 14.575 ;
        RECT 29.915 12.625 30.345 13.410 ;
        RECT 16.115 8.350 16.545 9.135 ;
        RECT 29.915 7.185 30.345 7.970 ;
        RECT 16.115 2.910 16.545 3.695 ;
        RECT 29.915 2.910 30.345 3.695 ;
      LAYER li1 ;
        RECT 16.185 35.445 16.475 36.170 ;
        RECT 16.645 35.445 16.955 36.245 ;
        RECT 18.955 35.445 19.230 35.925 ;
        RECT 19.815 35.445 20.150 35.845 ;
        RECT 20.560 35.445 20.790 36.265 ;
        RECT 22.165 35.445 22.475 36.245 ;
        RECT 24.005 35.445 24.315 36.245 ;
        RECT 25.620 35.445 25.850 36.265 ;
        RECT 27.000 35.445 27.230 36.265 ;
        RECT 28.150 35.445 28.405 35.935 ;
        RECT 29.985 35.445 30.275 36.170 ;
        RECT 30.465 35.445 30.705 36.255 ;
        RECT 31.375 35.445 31.645 36.255 ;
        RECT 31.825 35.445 32.135 36.245 ;
        RECT 2.300 35.275 33.580 35.445 ;
        RECT 15.960 34.455 16.190 35.275 ;
        RECT 17.340 34.455 17.570 35.275 ;
        RECT 19.955 34.455 20.125 35.275 ;
        RECT 20.795 34.795 20.965 35.275 ;
        RECT 21.635 34.795 21.805 35.275 ;
        RECT 22.475 34.795 22.645 35.275 ;
        RECT 23.315 34.795 23.485 35.275 ;
        RECT 24.155 34.795 24.325 35.275 ;
        RECT 24.995 34.795 25.165 35.275 ;
        RECT 25.835 34.795 26.005 35.275 ;
        RECT 26.675 34.795 26.845 35.275 ;
        RECT 27.515 34.795 27.685 35.275 ;
        RECT 28.355 34.795 28.525 35.275 ;
        RECT 29.195 34.795 29.365 35.275 ;
        RECT 29.985 34.550 30.275 35.275 ;
        RECT 30.445 34.475 30.755 35.275 ;
        RECT 16.185 30.005 16.475 30.730 ;
        RECT 17.800 30.005 18.030 30.825 ;
        RECT 18.945 30.005 19.255 30.805 ;
        RECT 21.250 30.005 21.505 30.495 ;
        RECT 23.635 30.005 23.805 30.825 ;
        RECT 24.475 30.005 24.645 30.485 ;
        RECT 25.315 30.005 25.485 30.485 ;
        RECT 26.155 30.005 26.325 30.485 ;
        RECT 26.995 30.005 27.165 30.485 ;
        RECT 27.835 30.005 28.005 30.485 ;
        RECT 28.675 30.005 28.845 30.485 ;
        RECT 29.515 30.005 29.685 30.485 ;
        RECT 30.355 30.005 30.525 30.485 ;
        RECT 31.195 30.005 31.365 30.485 ;
        RECT 32.035 30.005 32.205 30.485 ;
        RECT 32.875 30.005 33.045 30.485 ;
        RECT 2.300 29.835 33.580 30.005 ;
        RECT 16.195 29.355 16.470 29.835 ;
        RECT 17.115 29.355 17.370 29.835 ;
        RECT 17.975 29.355 18.255 29.835 ;
        RECT 18.525 29.015 18.755 29.835 ;
        RECT 19.425 29.015 19.635 29.835 ;
        RECT 19.955 29.015 20.125 29.835 ;
        RECT 20.795 29.355 20.965 29.835 ;
        RECT 21.635 29.355 21.805 29.835 ;
        RECT 22.475 29.355 22.645 29.835 ;
        RECT 23.315 29.355 23.485 29.835 ;
        RECT 24.155 29.355 24.325 29.835 ;
        RECT 24.995 29.355 25.165 29.835 ;
        RECT 25.835 29.355 26.005 29.835 ;
        RECT 26.675 29.355 26.845 29.835 ;
        RECT 27.515 29.355 27.685 29.835 ;
        RECT 28.355 29.355 28.525 29.835 ;
        RECT 29.195 29.355 29.365 29.835 ;
        RECT 29.985 29.110 30.275 29.835 ;
        RECT 30.955 29.375 31.125 29.835 ;
        RECT 6.955 24.565 7.285 24.945 ;
        RECT 7.895 24.565 8.225 24.945 ;
        RECT 10.050 24.565 10.460 25.005 ;
        RECT 11.200 24.565 11.520 25.025 ;
        RECT 13.130 24.565 13.790 25.045 ;
        RECT 14.920 24.565 15.205 25.025 ;
        RECT 16.185 24.565 16.475 25.290 ;
        RECT 23.635 24.565 23.805 25.385 ;
        RECT 24.475 24.565 24.645 25.045 ;
        RECT 25.315 24.565 25.485 25.045 ;
        RECT 26.155 24.565 26.325 25.045 ;
        RECT 26.995 24.565 27.165 25.045 ;
        RECT 27.835 24.565 28.005 25.045 ;
        RECT 28.675 24.565 28.845 25.045 ;
        RECT 29.515 24.565 29.685 25.045 ;
        RECT 30.355 24.565 30.525 25.045 ;
        RECT 31.195 24.565 31.365 25.045 ;
        RECT 32.035 24.565 32.205 25.045 ;
        RECT 32.875 24.565 33.045 25.045 ;
        RECT 2.300 24.395 33.580 24.565 ;
        RECT 11.095 24.015 11.425 24.395 ;
        RECT 12.035 24.015 12.365 24.395 ;
        RECT 14.190 23.955 14.600 24.395 ;
        RECT 15.340 23.935 15.660 24.395 ;
        RECT 17.270 23.915 17.930 24.395 ;
        RECT 19.060 23.935 19.345 24.395 ;
        RECT 20.755 24.015 21.085 24.395 ;
        RECT 21.695 24.015 22.025 24.395 ;
        RECT 23.850 23.955 24.260 24.395 ;
        RECT 25.000 23.935 25.320 24.395 ;
        RECT 26.930 23.915 27.590 24.395 ;
        RECT 28.720 23.935 29.005 24.395 ;
        RECT 29.985 23.670 30.275 24.395 ;
        RECT 30.680 23.575 30.910 24.395 ;
        RECT 32.060 23.575 32.290 24.395 ;
        RECT 6.495 19.125 6.825 19.505 ;
        RECT 7.435 19.125 7.765 19.505 ;
        RECT 9.590 19.125 10.000 19.565 ;
        RECT 10.740 19.125 11.060 19.585 ;
        RECT 12.670 19.125 13.330 19.605 ;
        RECT 14.460 19.125 14.745 19.585 ;
        RECT 16.185 19.125 16.475 19.850 ;
        RECT 17.535 19.125 17.865 19.505 ;
        RECT 18.475 19.125 18.805 19.505 ;
        RECT 20.630 19.125 21.040 19.565 ;
        RECT 21.780 19.125 22.100 19.585 ;
        RECT 23.710 19.125 24.370 19.605 ;
        RECT 25.500 19.125 25.785 19.585 ;
        RECT 28.605 19.125 28.915 19.925 ;
        RECT 2.300 18.955 33.580 19.125 ;
        RECT 19.865 18.155 20.175 18.955 ;
        RECT 21.245 18.155 21.555 18.955 ;
        RECT 22.625 18.155 22.935 18.955 ;
        RECT 24.240 18.135 24.470 18.955 ;
        RECT 27.275 18.495 27.445 18.955 ;
        RECT 29.985 18.230 30.275 18.955 ;
        RECT 31.375 18.475 31.650 18.955 ;
        RECT 32.295 18.475 32.550 18.955 ;
        RECT 33.155 18.475 33.435 18.955 ;
        RECT 16.185 13.685 16.475 14.410 ;
        RECT 17.115 13.685 17.390 14.165 ;
        RECT 18.035 13.685 18.290 14.165 ;
        RECT 18.895 13.685 19.175 14.165 ;
        RECT 22.180 13.685 22.510 14.065 ;
        RECT 23.110 13.685 23.370 14.525 ;
        RECT 23.780 13.685 24.010 14.505 ;
        RECT 26.540 13.685 26.770 14.505 ;
        RECT 28.610 13.685 28.825 14.145 ;
        RECT 29.970 13.685 30.300 14.165 ;
        RECT 31.370 13.685 31.625 14.175 ;
        RECT 2.300 13.515 33.580 13.685 ;
        RECT 19.375 13.135 19.705 13.515 ;
        RECT 20.315 13.135 20.645 13.515 ;
        RECT 22.470 13.075 22.880 13.515 ;
        RECT 23.620 13.055 23.940 13.515 ;
        RECT 25.550 13.035 26.190 13.515 ;
        RECT 27.250 12.775 27.580 13.515 ;
        RECT 28.165 13.005 28.435 13.515 ;
        RECT 28.605 12.715 28.915 13.515 ;
        RECT 29.985 12.790 30.275 13.515 ;
        RECT 30.445 12.715 30.755 13.515 ;
        RECT 32.265 13.135 32.595 13.515 ;
        RECT 16.185 8.245 16.475 8.970 ;
        RECT 19.415 8.245 19.690 8.725 ;
        RECT 20.335 8.245 20.590 8.725 ;
        RECT 21.195 8.245 21.475 8.725 ;
        RECT 22.135 8.245 22.465 8.625 ;
        RECT 23.075 8.245 23.405 8.625 ;
        RECT 25.230 8.245 25.640 8.685 ;
        RECT 26.380 8.245 26.700 8.705 ;
        RECT 28.310 8.245 28.970 8.725 ;
        RECT 30.100 8.245 30.385 8.705 ;
        RECT 31.600 8.245 31.830 9.065 ;
        RECT 2.300 8.075 33.580 8.245 ;
        RECT 9.255 7.695 9.585 8.075 ;
        RECT 10.195 7.695 10.525 8.075 ;
        RECT 12.350 7.635 12.760 8.075 ;
        RECT 13.500 7.615 13.820 8.075 ;
        RECT 15.430 7.595 16.090 8.075 ;
        RECT 17.220 7.615 17.505 8.075 ;
        RECT 18.915 7.695 19.245 8.075 ;
        RECT 19.855 7.695 20.185 8.075 ;
        RECT 22.010 7.635 22.420 8.075 ;
        RECT 23.160 7.615 23.480 8.075 ;
        RECT 25.090 7.595 25.750 8.075 ;
        RECT 26.880 7.615 27.165 8.075 ;
        RECT 29.985 7.350 30.275 8.075 ;
        RECT 30.680 7.255 30.910 8.075 ;
        RECT 31.825 7.275 32.135 8.075 ;
        RECT 6.955 2.805 7.285 3.185 ;
        RECT 7.895 2.805 8.225 3.185 ;
        RECT 10.050 2.805 10.460 3.245 ;
        RECT 11.200 2.805 11.520 3.265 ;
        RECT 13.130 2.805 13.790 3.285 ;
        RECT 14.920 2.805 15.205 3.265 ;
        RECT 16.185 2.805 16.475 3.530 ;
        RECT 17.075 2.805 17.405 3.185 ;
        RECT 18.015 2.805 18.345 3.185 ;
        RECT 20.170 2.805 20.580 3.245 ;
        RECT 21.320 2.805 21.640 3.265 ;
        RECT 23.250 2.805 23.910 3.285 ;
        RECT 25.040 2.805 25.325 3.265 ;
        RECT 29.985 2.805 30.275 3.530 ;
        RECT 2.300 2.635 33.580 2.805 ;
      LAYER mcon ;
        RECT 2.445 35.275 2.615 35.445 ;
        RECT 2.905 35.275 3.075 35.445 ;
        RECT 3.365 35.275 3.535 35.445 ;
        RECT 3.825 35.275 3.995 35.445 ;
        RECT 4.285 35.275 4.455 35.445 ;
        RECT 4.745 35.275 4.915 35.445 ;
        RECT 5.205 35.275 5.375 35.445 ;
        RECT 5.665 35.275 5.835 35.445 ;
        RECT 6.125 35.275 6.295 35.445 ;
        RECT 6.585 35.275 6.755 35.445 ;
        RECT 7.045 35.275 7.215 35.445 ;
        RECT 7.505 35.275 7.675 35.445 ;
        RECT 7.965 35.275 8.135 35.445 ;
        RECT 8.425 35.275 8.595 35.445 ;
        RECT 8.885 35.275 9.055 35.445 ;
        RECT 9.345 35.275 9.515 35.445 ;
        RECT 9.805 35.275 9.975 35.445 ;
        RECT 10.265 35.275 10.435 35.445 ;
        RECT 10.725 35.275 10.895 35.445 ;
        RECT 11.185 35.275 11.355 35.445 ;
        RECT 11.645 35.275 11.815 35.445 ;
        RECT 12.105 35.275 12.275 35.445 ;
        RECT 12.565 35.275 12.735 35.445 ;
        RECT 13.025 35.275 13.195 35.445 ;
        RECT 13.485 35.275 13.655 35.445 ;
        RECT 13.945 35.275 14.115 35.445 ;
        RECT 14.405 35.275 14.575 35.445 ;
        RECT 14.865 35.275 15.035 35.445 ;
        RECT 15.325 35.275 15.495 35.445 ;
        RECT 15.785 35.275 15.955 35.445 ;
        RECT 16.245 35.275 16.415 35.445 ;
        RECT 16.705 35.275 16.875 35.445 ;
        RECT 17.165 35.275 17.335 35.445 ;
        RECT 17.625 35.275 17.795 35.445 ;
        RECT 18.085 35.275 18.255 35.445 ;
        RECT 18.545 35.275 18.715 35.445 ;
        RECT 19.005 35.275 19.175 35.445 ;
        RECT 19.465 35.275 19.635 35.445 ;
        RECT 19.925 35.275 20.095 35.445 ;
        RECT 20.385 35.275 20.555 35.445 ;
        RECT 20.845 35.275 21.015 35.445 ;
        RECT 21.305 35.275 21.475 35.445 ;
        RECT 21.765 35.275 21.935 35.445 ;
        RECT 22.225 35.275 22.395 35.445 ;
        RECT 22.685 35.275 22.855 35.445 ;
        RECT 23.145 35.275 23.315 35.445 ;
        RECT 23.605 35.275 23.775 35.445 ;
        RECT 24.065 35.275 24.235 35.445 ;
        RECT 24.525 35.275 24.695 35.445 ;
        RECT 24.985 35.275 25.155 35.445 ;
        RECT 25.445 35.275 25.615 35.445 ;
        RECT 25.905 35.275 26.075 35.445 ;
        RECT 26.365 35.275 26.535 35.445 ;
        RECT 26.825 35.275 26.995 35.445 ;
        RECT 27.285 35.275 27.455 35.445 ;
        RECT 27.745 35.275 27.915 35.445 ;
        RECT 28.205 35.275 28.375 35.445 ;
        RECT 28.665 35.275 28.835 35.445 ;
        RECT 29.125 35.275 29.295 35.445 ;
        RECT 29.585 35.275 29.755 35.445 ;
        RECT 30.045 35.275 30.215 35.445 ;
        RECT 30.505 35.275 30.675 35.445 ;
        RECT 30.965 35.275 31.135 35.445 ;
        RECT 31.425 35.275 31.595 35.445 ;
        RECT 31.885 35.275 32.055 35.445 ;
        RECT 32.345 35.275 32.515 35.445 ;
        RECT 32.805 35.275 32.975 35.445 ;
        RECT 33.265 35.275 33.435 35.445 ;
        RECT 2.445 29.835 2.615 30.005 ;
        RECT 2.905 29.835 3.075 30.005 ;
        RECT 3.365 29.835 3.535 30.005 ;
        RECT 3.825 29.835 3.995 30.005 ;
        RECT 4.285 29.835 4.455 30.005 ;
        RECT 4.745 29.835 4.915 30.005 ;
        RECT 5.205 29.835 5.375 30.005 ;
        RECT 5.665 29.835 5.835 30.005 ;
        RECT 6.125 29.835 6.295 30.005 ;
        RECT 6.585 29.835 6.755 30.005 ;
        RECT 7.045 29.835 7.215 30.005 ;
        RECT 7.505 29.835 7.675 30.005 ;
        RECT 7.965 29.835 8.135 30.005 ;
        RECT 8.425 29.835 8.595 30.005 ;
        RECT 8.885 29.835 9.055 30.005 ;
        RECT 9.345 29.835 9.515 30.005 ;
        RECT 9.805 29.835 9.975 30.005 ;
        RECT 10.265 29.835 10.435 30.005 ;
        RECT 10.725 29.835 10.895 30.005 ;
        RECT 11.185 29.835 11.355 30.005 ;
        RECT 11.645 29.835 11.815 30.005 ;
        RECT 12.105 29.835 12.275 30.005 ;
        RECT 12.565 29.835 12.735 30.005 ;
        RECT 13.025 29.835 13.195 30.005 ;
        RECT 13.485 29.835 13.655 30.005 ;
        RECT 13.945 29.835 14.115 30.005 ;
        RECT 14.405 29.835 14.575 30.005 ;
        RECT 14.865 29.835 15.035 30.005 ;
        RECT 15.325 29.835 15.495 30.005 ;
        RECT 15.785 29.835 15.955 30.005 ;
        RECT 16.245 29.835 16.415 30.005 ;
        RECT 16.705 29.835 16.875 30.005 ;
        RECT 17.165 29.835 17.335 30.005 ;
        RECT 17.625 29.835 17.795 30.005 ;
        RECT 18.085 29.835 18.255 30.005 ;
        RECT 18.545 29.835 18.715 30.005 ;
        RECT 19.005 29.835 19.175 30.005 ;
        RECT 19.465 29.835 19.635 30.005 ;
        RECT 19.925 29.835 20.095 30.005 ;
        RECT 20.385 29.835 20.555 30.005 ;
        RECT 20.845 29.835 21.015 30.005 ;
        RECT 21.305 29.835 21.475 30.005 ;
        RECT 21.765 29.835 21.935 30.005 ;
        RECT 22.225 29.835 22.395 30.005 ;
        RECT 22.685 29.835 22.855 30.005 ;
        RECT 23.145 29.835 23.315 30.005 ;
        RECT 23.605 29.835 23.775 30.005 ;
        RECT 24.065 29.835 24.235 30.005 ;
        RECT 24.525 29.835 24.695 30.005 ;
        RECT 24.985 29.835 25.155 30.005 ;
        RECT 25.445 29.835 25.615 30.005 ;
        RECT 25.905 29.835 26.075 30.005 ;
        RECT 26.365 29.835 26.535 30.005 ;
        RECT 26.825 29.835 26.995 30.005 ;
        RECT 27.285 29.835 27.455 30.005 ;
        RECT 27.745 29.835 27.915 30.005 ;
        RECT 28.205 29.835 28.375 30.005 ;
        RECT 28.665 29.835 28.835 30.005 ;
        RECT 29.125 29.835 29.295 30.005 ;
        RECT 29.585 29.835 29.755 30.005 ;
        RECT 30.045 29.835 30.215 30.005 ;
        RECT 30.505 29.835 30.675 30.005 ;
        RECT 30.965 29.835 31.135 30.005 ;
        RECT 31.425 29.835 31.595 30.005 ;
        RECT 31.885 29.835 32.055 30.005 ;
        RECT 32.345 29.835 32.515 30.005 ;
        RECT 32.805 29.835 32.975 30.005 ;
        RECT 33.265 29.835 33.435 30.005 ;
        RECT 2.445 24.395 2.615 24.565 ;
        RECT 2.905 24.395 3.075 24.565 ;
        RECT 3.365 24.395 3.535 24.565 ;
        RECT 3.825 24.395 3.995 24.565 ;
        RECT 4.285 24.395 4.455 24.565 ;
        RECT 4.745 24.395 4.915 24.565 ;
        RECT 5.205 24.395 5.375 24.565 ;
        RECT 5.665 24.395 5.835 24.565 ;
        RECT 6.125 24.395 6.295 24.565 ;
        RECT 6.585 24.395 6.755 24.565 ;
        RECT 7.045 24.395 7.215 24.565 ;
        RECT 7.505 24.395 7.675 24.565 ;
        RECT 7.965 24.395 8.135 24.565 ;
        RECT 8.425 24.395 8.595 24.565 ;
        RECT 8.885 24.395 9.055 24.565 ;
        RECT 9.345 24.395 9.515 24.565 ;
        RECT 9.805 24.395 9.975 24.565 ;
        RECT 10.265 24.395 10.435 24.565 ;
        RECT 10.725 24.395 10.895 24.565 ;
        RECT 11.185 24.395 11.355 24.565 ;
        RECT 11.645 24.395 11.815 24.565 ;
        RECT 12.105 24.395 12.275 24.565 ;
        RECT 12.565 24.395 12.735 24.565 ;
        RECT 13.025 24.395 13.195 24.565 ;
        RECT 13.485 24.395 13.655 24.565 ;
        RECT 13.945 24.395 14.115 24.565 ;
        RECT 14.405 24.395 14.575 24.565 ;
        RECT 14.865 24.395 15.035 24.565 ;
        RECT 15.325 24.395 15.495 24.565 ;
        RECT 15.785 24.395 15.955 24.565 ;
        RECT 16.245 24.395 16.415 24.565 ;
        RECT 16.705 24.395 16.875 24.565 ;
        RECT 17.165 24.395 17.335 24.565 ;
        RECT 17.625 24.395 17.795 24.565 ;
        RECT 18.085 24.395 18.255 24.565 ;
        RECT 18.545 24.395 18.715 24.565 ;
        RECT 19.005 24.395 19.175 24.565 ;
        RECT 19.465 24.395 19.635 24.565 ;
        RECT 19.925 24.395 20.095 24.565 ;
        RECT 20.385 24.395 20.555 24.565 ;
        RECT 20.845 24.395 21.015 24.565 ;
        RECT 21.305 24.395 21.475 24.565 ;
        RECT 21.765 24.395 21.935 24.565 ;
        RECT 22.225 24.395 22.395 24.565 ;
        RECT 22.685 24.395 22.855 24.565 ;
        RECT 23.145 24.395 23.315 24.565 ;
        RECT 23.605 24.395 23.775 24.565 ;
        RECT 24.065 24.395 24.235 24.565 ;
        RECT 24.525 24.395 24.695 24.565 ;
        RECT 24.985 24.395 25.155 24.565 ;
        RECT 25.445 24.395 25.615 24.565 ;
        RECT 25.905 24.395 26.075 24.565 ;
        RECT 26.365 24.395 26.535 24.565 ;
        RECT 26.825 24.395 26.995 24.565 ;
        RECT 27.285 24.395 27.455 24.565 ;
        RECT 27.745 24.395 27.915 24.565 ;
        RECT 28.205 24.395 28.375 24.565 ;
        RECT 28.665 24.395 28.835 24.565 ;
        RECT 29.125 24.395 29.295 24.565 ;
        RECT 29.585 24.395 29.755 24.565 ;
        RECT 30.045 24.395 30.215 24.565 ;
        RECT 30.505 24.395 30.675 24.565 ;
        RECT 30.965 24.395 31.135 24.565 ;
        RECT 31.425 24.395 31.595 24.565 ;
        RECT 31.885 24.395 32.055 24.565 ;
        RECT 32.345 24.395 32.515 24.565 ;
        RECT 32.805 24.395 32.975 24.565 ;
        RECT 33.265 24.395 33.435 24.565 ;
        RECT 2.445 18.955 2.615 19.125 ;
        RECT 2.905 18.955 3.075 19.125 ;
        RECT 3.365 18.955 3.535 19.125 ;
        RECT 3.825 18.955 3.995 19.125 ;
        RECT 4.285 18.955 4.455 19.125 ;
        RECT 4.745 18.955 4.915 19.125 ;
        RECT 5.205 18.955 5.375 19.125 ;
        RECT 5.665 18.955 5.835 19.125 ;
        RECT 6.125 18.955 6.295 19.125 ;
        RECT 6.585 18.955 6.755 19.125 ;
        RECT 7.045 18.955 7.215 19.125 ;
        RECT 7.505 18.955 7.675 19.125 ;
        RECT 7.965 18.955 8.135 19.125 ;
        RECT 8.425 18.955 8.595 19.125 ;
        RECT 8.885 18.955 9.055 19.125 ;
        RECT 9.345 18.955 9.515 19.125 ;
        RECT 9.805 18.955 9.975 19.125 ;
        RECT 10.265 18.955 10.435 19.125 ;
        RECT 10.725 18.955 10.895 19.125 ;
        RECT 11.185 18.955 11.355 19.125 ;
        RECT 11.645 18.955 11.815 19.125 ;
        RECT 12.105 18.955 12.275 19.125 ;
        RECT 12.565 18.955 12.735 19.125 ;
        RECT 13.025 18.955 13.195 19.125 ;
        RECT 13.485 18.955 13.655 19.125 ;
        RECT 13.945 18.955 14.115 19.125 ;
        RECT 14.405 18.955 14.575 19.125 ;
        RECT 14.865 18.955 15.035 19.125 ;
        RECT 15.325 18.955 15.495 19.125 ;
        RECT 15.785 18.955 15.955 19.125 ;
        RECT 16.245 18.955 16.415 19.125 ;
        RECT 16.705 18.955 16.875 19.125 ;
        RECT 17.165 18.955 17.335 19.125 ;
        RECT 17.625 18.955 17.795 19.125 ;
        RECT 18.085 18.955 18.255 19.125 ;
        RECT 18.545 18.955 18.715 19.125 ;
        RECT 19.005 18.955 19.175 19.125 ;
        RECT 19.465 18.955 19.635 19.125 ;
        RECT 19.925 18.955 20.095 19.125 ;
        RECT 20.385 18.955 20.555 19.125 ;
        RECT 20.845 18.955 21.015 19.125 ;
        RECT 21.305 18.955 21.475 19.125 ;
        RECT 21.765 18.955 21.935 19.125 ;
        RECT 22.225 18.955 22.395 19.125 ;
        RECT 22.685 18.955 22.855 19.125 ;
        RECT 23.145 18.955 23.315 19.125 ;
        RECT 23.605 18.955 23.775 19.125 ;
        RECT 24.065 18.955 24.235 19.125 ;
        RECT 24.525 18.955 24.695 19.125 ;
        RECT 24.985 18.955 25.155 19.125 ;
        RECT 25.445 18.955 25.615 19.125 ;
        RECT 25.905 18.955 26.075 19.125 ;
        RECT 26.365 18.955 26.535 19.125 ;
        RECT 26.825 18.955 26.995 19.125 ;
        RECT 27.285 18.955 27.455 19.125 ;
        RECT 27.745 18.955 27.915 19.125 ;
        RECT 28.205 18.955 28.375 19.125 ;
        RECT 28.665 18.955 28.835 19.125 ;
        RECT 29.125 18.955 29.295 19.125 ;
        RECT 29.585 18.955 29.755 19.125 ;
        RECT 30.045 18.955 30.215 19.125 ;
        RECT 30.505 18.955 30.675 19.125 ;
        RECT 30.965 18.955 31.135 19.125 ;
        RECT 31.425 18.955 31.595 19.125 ;
        RECT 31.885 18.955 32.055 19.125 ;
        RECT 32.345 18.955 32.515 19.125 ;
        RECT 32.805 18.955 32.975 19.125 ;
        RECT 33.265 18.955 33.435 19.125 ;
        RECT 2.445 13.515 2.615 13.685 ;
        RECT 2.905 13.515 3.075 13.685 ;
        RECT 3.365 13.515 3.535 13.685 ;
        RECT 3.825 13.515 3.995 13.685 ;
        RECT 4.285 13.515 4.455 13.685 ;
        RECT 4.745 13.515 4.915 13.685 ;
        RECT 5.205 13.515 5.375 13.685 ;
        RECT 5.665 13.515 5.835 13.685 ;
        RECT 6.125 13.515 6.295 13.685 ;
        RECT 6.585 13.515 6.755 13.685 ;
        RECT 7.045 13.515 7.215 13.685 ;
        RECT 7.505 13.515 7.675 13.685 ;
        RECT 7.965 13.515 8.135 13.685 ;
        RECT 8.425 13.515 8.595 13.685 ;
        RECT 8.885 13.515 9.055 13.685 ;
        RECT 9.345 13.515 9.515 13.685 ;
        RECT 9.805 13.515 9.975 13.685 ;
        RECT 10.265 13.515 10.435 13.685 ;
        RECT 10.725 13.515 10.895 13.685 ;
        RECT 11.185 13.515 11.355 13.685 ;
        RECT 11.645 13.515 11.815 13.685 ;
        RECT 12.105 13.515 12.275 13.685 ;
        RECT 12.565 13.515 12.735 13.685 ;
        RECT 13.025 13.515 13.195 13.685 ;
        RECT 13.485 13.515 13.655 13.685 ;
        RECT 13.945 13.515 14.115 13.685 ;
        RECT 14.405 13.515 14.575 13.685 ;
        RECT 14.865 13.515 15.035 13.685 ;
        RECT 15.325 13.515 15.495 13.685 ;
        RECT 15.785 13.515 15.955 13.685 ;
        RECT 16.245 13.515 16.415 13.685 ;
        RECT 16.705 13.515 16.875 13.685 ;
        RECT 17.165 13.515 17.335 13.685 ;
        RECT 17.625 13.515 17.795 13.685 ;
        RECT 18.085 13.515 18.255 13.685 ;
        RECT 18.545 13.515 18.715 13.685 ;
        RECT 19.005 13.515 19.175 13.685 ;
        RECT 19.465 13.515 19.635 13.685 ;
        RECT 19.925 13.515 20.095 13.685 ;
        RECT 20.385 13.515 20.555 13.685 ;
        RECT 20.845 13.515 21.015 13.685 ;
        RECT 21.305 13.515 21.475 13.685 ;
        RECT 21.765 13.515 21.935 13.685 ;
        RECT 22.225 13.515 22.395 13.685 ;
        RECT 22.685 13.515 22.855 13.685 ;
        RECT 23.145 13.515 23.315 13.685 ;
        RECT 23.605 13.515 23.775 13.685 ;
        RECT 24.065 13.515 24.235 13.685 ;
        RECT 24.525 13.515 24.695 13.685 ;
        RECT 24.985 13.515 25.155 13.685 ;
        RECT 25.445 13.515 25.615 13.685 ;
        RECT 25.905 13.515 26.075 13.685 ;
        RECT 26.365 13.515 26.535 13.685 ;
        RECT 26.825 13.515 26.995 13.685 ;
        RECT 27.285 13.515 27.455 13.685 ;
        RECT 27.745 13.515 27.915 13.685 ;
        RECT 28.205 13.515 28.375 13.685 ;
        RECT 28.665 13.515 28.835 13.685 ;
        RECT 29.125 13.515 29.295 13.685 ;
        RECT 29.585 13.515 29.755 13.685 ;
        RECT 30.045 13.515 30.215 13.685 ;
        RECT 30.505 13.515 30.675 13.685 ;
        RECT 30.965 13.515 31.135 13.685 ;
        RECT 31.425 13.515 31.595 13.685 ;
        RECT 31.885 13.515 32.055 13.685 ;
        RECT 32.345 13.515 32.515 13.685 ;
        RECT 32.805 13.515 32.975 13.685 ;
        RECT 33.265 13.515 33.435 13.685 ;
        RECT 2.445 8.075 2.615 8.245 ;
        RECT 2.905 8.075 3.075 8.245 ;
        RECT 3.365 8.075 3.535 8.245 ;
        RECT 3.825 8.075 3.995 8.245 ;
        RECT 4.285 8.075 4.455 8.245 ;
        RECT 4.745 8.075 4.915 8.245 ;
        RECT 5.205 8.075 5.375 8.245 ;
        RECT 5.665 8.075 5.835 8.245 ;
        RECT 6.125 8.075 6.295 8.245 ;
        RECT 6.585 8.075 6.755 8.245 ;
        RECT 7.045 8.075 7.215 8.245 ;
        RECT 7.505 8.075 7.675 8.245 ;
        RECT 7.965 8.075 8.135 8.245 ;
        RECT 8.425 8.075 8.595 8.245 ;
        RECT 8.885 8.075 9.055 8.245 ;
        RECT 9.345 8.075 9.515 8.245 ;
        RECT 9.805 8.075 9.975 8.245 ;
        RECT 10.265 8.075 10.435 8.245 ;
        RECT 10.725 8.075 10.895 8.245 ;
        RECT 11.185 8.075 11.355 8.245 ;
        RECT 11.645 8.075 11.815 8.245 ;
        RECT 12.105 8.075 12.275 8.245 ;
        RECT 12.565 8.075 12.735 8.245 ;
        RECT 13.025 8.075 13.195 8.245 ;
        RECT 13.485 8.075 13.655 8.245 ;
        RECT 13.945 8.075 14.115 8.245 ;
        RECT 14.405 8.075 14.575 8.245 ;
        RECT 14.865 8.075 15.035 8.245 ;
        RECT 15.325 8.075 15.495 8.245 ;
        RECT 15.785 8.075 15.955 8.245 ;
        RECT 16.245 8.075 16.415 8.245 ;
        RECT 16.705 8.075 16.875 8.245 ;
        RECT 17.165 8.075 17.335 8.245 ;
        RECT 17.625 8.075 17.795 8.245 ;
        RECT 18.085 8.075 18.255 8.245 ;
        RECT 18.545 8.075 18.715 8.245 ;
        RECT 19.005 8.075 19.175 8.245 ;
        RECT 19.465 8.075 19.635 8.245 ;
        RECT 19.925 8.075 20.095 8.245 ;
        RECT 20.385 8.075 20.555 8.245 ;
        RECT 20.845 8.075 21.015 8.245 ;
        RECT 21.305 8.075 21.475 8.245 ;
        RECT 21.765 8.075 21.935 8.245 ;
        RECT 22.225 8.075 22.395 8.245 ;
        RECT 22.685 8.075 22.855 8.245 ;
        RECT 23.145 8.075 23.315 8.245 ;
        RECT 23.605 8.075 23.775 8.245 ;
        RECT 24.065 8.075 24.235 8.245 ;
        RECT 24.525 8.075 24.695 8.245 ;
        RECT 24.985 8.075 25.155 8.245 ;
        RECT 25.445 8.075 25.615 8.245 ;
        RECT 25.905 8.075 26.075 8.245 ;
        RECT 26.365 8.075 26.535 8.245 ;
        RECT 26.825 8.075 26.995 8.245 ;
        RECT 27.285 8.075 27.455 8.245 ;
        RECT 27.745 8.075 27.915 8.245 ;
        RECT 28.205 8.075 28.375 8.245 ;
        RECT 28.665 8.075 28.835 8.245 ;
        RECT 29.125 8.075 29.295 8.245 ;
        RECT 29.585 8.075 29.755 8.245 ;
        RECT 30.045 8.075 30.215 8.245 ;
        RECT 30.505 8.075 30.675 8.245 ;
        RECT 30.965 8.075 31.135 8.245 ;
        RECT 31.425 8.075 31.595 8.245 ;
        RECT 31.885 8.075 32.055 8.245 ;
        RECT 32.345 8.075 32.515 8.245 ;
        RECT 32.805 8.075 32.975 8.245 ;
        RECT 33.265 8.075 33.435 8.245 ;
        RECT 2.445 2.635 2.615 2.805 ;
        RECT 2.905 2.635 3.075 2.805 ;
        RECT 3.365 2.635 3.535 2.805 ;
        RECT 3.825 2.635 3.995 2.805 ;
        RECT 4.285 2.635 4.455 2.805 ;
        RECT 4.745 2.635 4.915 2.805 ;
        RECT 5.205 2.635 5.375 2.805 ;
        RECT 5.665 2.635 5.835 2.805 ;
        RECT 6.125 2.635 6.295 2.805 ;
        RECT 6.585 2.635 6.755 2.805 ;
        RECT 7.045 2.635 7.215 2.805 ;
        RECT 7.505 2.635 7.675 2.805 ;
        RECT 7.965 2.635 8.135 2.805 ;
        RECT 8.425 2.635 8.595 2.805 ;
        RECT 8.885 2.635 9.055 2.805 ;
        RECT 9.345 2.635 9.515 2.805 ;
        RECT 9.805 2.635 9.975 2.805 ;
        RECT 10.265 2.635 10.435 2.805 ;
        RECT 10.725 2.635 10.895 2.805 ;
        RECT 11.185 2.635 11.355 2.805 ;
        RECT 11.645 2.635 11.815 2.805 ;
        RECT 12.105 2.635 12.275 2.805 ;
        RECT 12.565 2.635 12.735 2.805 ;
        RECT 13.025 2.635 13.195 2.805 ;
        RECT 13.485 2.635 13.655 2.805 ;
        RECT 13.945 2.635 14.115 2.805 ;
        RECT 14.405 2.635 14.575 2.805 ;
        RECT 14.865 2.635 15.035 2.805 ;
        RECT 15.325 2.635 15.495 2.805 ;
        RECT 15.785 2.635 15.955 2.805 ;
        RECT 16.245 2.635 16.415 2.805 ;
        RECT 16.705 2.635 16.875 2.805 ;
        RECT 17.165 2.635 17.335 2.805 ;
        RECT 17.625 2.635 17.795 2.805 ;
        RECT 18.085 2.635 18.255 2.805 ;
        RECT 18.545 2.635 18.715 2.805 ;
        RECT 19.005 2.635 19.175 2.805 ;
        RECT 19.465 2.635 19.635 2.805 ;
        RECT 19.925 2.635 20.095 2.805 ;
        RECT 20.385 2.635 20.555 2.805 ;
        RECT 20.845 2.635 21.015 2.805 ;
        RECT 21.305 2.635 21.475 2.805 ;
        RECT 21.765 2.635 21.935 2.805 ;
        RECT 22.225 2.635 22.395 2.805 ;
        RECT 22.685 2.635 22.855 2.805 ;
        RECT 23.145 2.635 23.315 2.805 ;
        RECT 23.605 2.635 23.775 2.805 ;
        RECT 24.065 2.635 24.235 2.805 ;
        RECT 24.525 2.635 24.695 2.805 ;
        RECT 24.985 2.635 25.155 2.805 ;
        RECT 25.445 2.635 25.615 2.805 ;
        RECT 25.905 2.635 26.075 2.805 ;
        RECT 26.365 2.635 26.535 2.805 ;
        RECT 26.825 2.635 26.995 2.805 ;
        RECT 27.285 2.635 27.455 2.805 ;
        RECT 27.745 2.635 27.915 2.805 ;
        RECT 28.205 2.635 28.375 2.805 ;
        RECT 28.665 2.635 28.835 2.805 ;
        RECT 29.125 2.635 29.295 2.805 ;
        RECT 29.585 2.635 29.755 2.805 ;
        RECT 30.045 2.635 30.215 2.805 ;
        RECT 30.505 2.635 30.675 2.805 ;
        RECT 30.965 2.635 31.135 2.805 ;
        RECT 31.425 2.635 31.595 2.805 ;
        RECT 31.885 2.635 32.055 2.805 ;
        RECT 32.345 2.635 32.515 2.805 ;
        RECT 32.805 2.635 32.975 2.805 ;
        RECT 33.265 2.635 33.435 2.805 ;
      LAYER met1 ;
        RECT -9.700 35.120 45.580 35.600 ;
        RECT -9.700 29.680 45.580 30.160 ;
        RECT -9.700 24.240 45.580 24.720 ;
        RECT -9.700 18.800 45.580 19.280 ;
        RECT -9.700 13.360 45.580 13.840 ;
        RECT -9.700 7.920 45.580 8.400 ;
        RECT -9.700 2.480 45.580 2.960 ;
      LAYER via ;
        RECT -9.650 35.230 -9.390 35.490 ;
        RECT -9.330 35.230 -9.070 35.490 ;
        RECT -9.010 35.230 -8.750 35.490 ;
        RECT -8.690 35.230 -8.430 35.490 ;
        RECT -8.370 35.230 -8.110 35.490 ;
        RECT -8.050 35.230 -7.790 35.490 ;
        RECT -7.730 35.230 -7.470 35.490 ;
        RECT -7.410 35.230 -7.150 35.490 ;
        RECT -7.090 35.230 -6.830 35.490 ;
        RECT -6.770 35.230 -6.510 35.490 ;
        RECT -6.450 35.230 -6.190 35.490 ;
        RECT -6.130 35.230 -5.870 35.490 ;
        RECT -5.810 35.230 -5.550 35.490 ;
        RECT 21.530 35.230 21.790 35.490 ;
        RECT 21.850 35.230 22.110 35.490 ;
        RECT 22.170 35.230 22.430 35.490 ;
        RECT 22.490 35.230 22.750 35.490 ;
        RECT 22.810 35.230 23.070 35.490 ;
        RECT 41.430 35.230 41.690 35.490 ;
        RECT 41.750 35.230 42.010 35.490 ;
        RECT 42.070 35.230 42.330 35.490 ;
        RECT 42.390 35.230 42.650 35.490 ;
        RECT 42.710 35.230 42.970 35.490 ;
        RECT 43.030 35.230 43.290 35.490 ;
        RECT 43.350 35.230 43.610 35.490 ;
        RECT 43.670 35.230 43.930 35.490 ;
        RECT 43.990 35.230 44.250 35.490 ;
        RECT 44.310 35.230 44.570 35.490 ;
        RECT 44.630 35.230 44.890 35.490 ;
        RECT 44.950 35.230 45.210 35.490 ;
        RECT 45.270 35.230 45.530 35.490 ;
        RECT -9.650 29.790 -9.390 30.050 ;
        RECT -9.330 29.790 -9.070 30.050 ;
        RECT -9.010 29.790 -8.750 30.050 ;
        RECT -8.690 29.790 -8.430 30.050 ;
        RECT -8.370 29.790 -8.110 30.050 ;
        RECT -8.050 29.790 -7.790 30.050 ;
        RECT -7.730 29.790 -7.470 30.050 ;
        RECT -7.410 29.790 -7.150 30.050 ;
        RECT -7.090 29.790 -6.830 30.050 ;
        RECT -6.770 29.790 -6.510 30.050 ;
        RECT -6.450 29.790 -6.190 30.050 ;
        RECT -6.130 29.790 -5.870 30.050 ;
        RECT -5.810 29.790 -5.550 30.050 ;
        RECT 21.530 29.790 21.790 30.050 ;
        RECT 21.850 29.790 22.110 30.050 ;
        RECT 22.170 29.790 22.430 30.050 ;
        RECT 22.490 29.790 22.750 30.050 ;
        RECT 22.810 29.790 23.070 30.050 ;
        RECT 41.430 29.790 41.690 30.050 ;
        RECT 41.750 29.790 42.010 30.050 ;
        RECT 42.070 29.790 42.330 30.050 ;
        RECT 42.390 29.790 42.650 30.050 ;
        RECT 42.710 29.790 42.970 30.050 ;
        RECT 43.030 29.790 43.290 30.050 ;
        RECT 43.350 29.790 43.610 30.050 ;
        RECT 43.670 29.790 43.930 30.050 ;
        RECT 43.990 29.790 44.250 30.050 ;
        RECT 44.310 29.790 44.570 30.050 ;
        RECT 44.630 29.790 44.890 30.050 ;
        RECT 44.950 29.790 45.210 30.050 ;
        RECT 45.270 29.790 45.530 30.050 ;
        RECT -9.650 24.350 -9.390 24.610 ;
        RECT -9.330 24.350 -9.070 24.610 ;
        RECT -9.010 24.350 -8.750 24.610 ;
        RECT -8.690 24.350 -8.430 24.610 ;
        RECT -8.370 24.350 -8.110 24.610 ;
        RECT -8.050 24.350 -7.790 24.610 ;
        RECT -7.730 24.350 -7.470 24.610 ;
        RECT -7.410 24.350 -7.150 24.610 ;
        RECT -7.090 24.350 -6.830 24.610 ;
        RECT -6.770 24.350 -6.510 24.610 ;
        RECT -6.450 24.350 -6.190 24.610 ;
        RECT -6.130 24.350 -5.870 24.610 ;
        RECT -5.810 24.350 -5.550 24.610 ;
        RECT 21.530 24.350 21.790 24.610 ;
        RECT 21.850 24.350 22.110 24.610 ;
        RECT 22.170 24.350 22.430 24.610 ;
        RECT 22.490 24.350 22.750 24.610 ;
        RECT 22.810 24.350 23.070 24.610 ;
        RECT 41.430 24.350 41.690 24.610 ;
        RECT 41.750 24.350 42.010 24.610 ;
        RECT 42.070 24.350 42.330 24.610 ;
        RECT 42.390 24.350 42.650 24.610 ;
        RECT 42.710 24.350 42.970 24.610 ;
        RECT 43.030 24.350 43.290 24.610 ;
        RECT 43.350 24.350 43.610 24.610 ;
        RECT 43.670 24.350 43.930 24.610 ;
        RECT 43.990 24.350 44.250 24.610 ;
        RECT 44.310 24.350 44.570 24.610 ;
        RECT 44.630 24.350 44.890 24.610 ;
        RECT 44.950 24.350 45.210 24.610 ;
        RECT 45.270 24.350 45.530 24.610 ;
        RECT -9.650 18.910 -9.390 19.170 ;
        RECT -9.330 18.910 -9.070 19.170 ;
        RECT -9.010 18.910 -8.750 19.170 ;
        RECT -8.690 18.910 -8.430 19.170 ;
        RECT -8.370 18.910 -8.110 19.170 ;
        RECT -8.050 18.910 -7.790 19.170 ;
        RECT -7.730 18.910 -7.470 19.170 ;
        RECT -7.410 18.910 -7.150 19.170 ;
        RECT -7.090 18.910 -6.830 19.170 ;
        RECT -6.770 18.910 -6.510 19.170 ;
        RECT -6.450 18.910 -6.190 19.170 ;
        RECT -6.130 18.910 -5.870 19.170 ;
        RECT -5.810 18.910 -5.550 19.170 ;
        RECT 21.530 18.910 21.790 19.170 ;
        RECT 21.850 18.910 22.110 19.170 ;
        RECT 22.170 18.910 22.430 19.170 ;
        RECT 22.490 18.910 22.750 19.170 ;
        RECT 22.810 18.910 23.070 19.170 ;
        RECT 41.430 18.910 41.690 19.170 ;
        RECT 41.750 18.910 42.010 19.170 ;
        RECT 42.070 18.910 42.330 19.170 ;
        RECT 42.390 18.910 42.650 19.170 ;
        RECT 42.710 18.910 42.970 19.170 ;
        RECT 43.030 18.910 43.290 19.170 ;
        RECT 43.350 18.910 43.610 19.170 ;
        RECT 43.670 18.910 43.930 19.170 ;
        RECT 43.990 18.910 44.250 19.170 ;
        RECT 44.310 18.910 44.570 19.170 ;
        RECT 44.630 18.910 44.890 19.170 ;
        RECT 44.950 18.910 45.210 19.170 ;
        RECT 45.270 18.910 45.530 19.170 ;
        RECT -9.650 13.470 -9.390 13.730 ;
        RECT -9.330 13.470 -9.070 13.730 ;
        RECT -9.010 13.470 -8.750 13.730 ;
        RECT -8.690 13.470 -8.430 13.730 ;
        RECT -8.370 13.470 -8.110 13.730 ;
        RECT -8.050 13.470 -7.790 13.730 ;
        RECT -7.730 13.470 -7.470 13.730 ;
        RECT -7.410 13.470 -7.150 13.730 ;
        RECT -7.090 13.470 -6.830 13.730 ;
        RECT -6.770 13.470 -6.510 13.730 ;
        RECT -6.450 13.470 -6.190 13.730 ;
        RECT -6.130 13.470 -5.870 13.730 ;
        RECT -5.810 13.470 -5.550 13.730 ;
        RECT 21.530 13.470 21.790 13.730 ;
        RECT 21.850 13.470 22.110 13.730 ;
        RECT 22.170 13.470 22.430 13.730 ;
        RECT 22.490 13.470 22.750 13.730 ;
        RECT 22.810 13.470 23.070 13.730 ;
        RECT 41.430 13.470 41.690 13.730 ;
        RECT 41.750 13.470 42.010 13.730 ;
        RECT 42.070 13.470 42.330 13.730 ;
        RECT 42.390 13.470 42.650 13.730 ;
        RECT 42.710 13.470 42.970 13.730 ;
        RECT 43.030 13.470 43.290 13.730 ;
        RECT 43.350 13.470 43.610 13.730 ;
        RECT 43.670 13.470 43.930 13.730 ;
        RECT 43.990 13.470 44.250 13.730 ;
        RECT 44.310 13.470 44.570 13.730 ;
        RECT 44.630 13.470 44.890 13.730 ;
        RECT 44.950 13.470 45.210 13.730 ;
        RECT 45.270 13.470 45.530 13.730 ;
        RECT -9.650 8.030 -9.390 8.290 ;
        RECT -9.330 8.030 -9.070 8.290 ;
        RECT -9.010 8.030 -8.750 8.290 ;
        RECT -8.690 8.030 -8.430 8.290 ;
        RECT -8.370 8.030 -8.110 8.290 ;
        RECT -8.050 8.030 -7.790 8.290 ;
        RECT -7.730 8.030 -7.470 8.290 ;
        RECT -7.410 8.030 -7.150 8.290 ;
        RECT -7.090 8.030 -6.830 8.290 ;
        RECT -6.770 8.030 -6.510 8.290 ;
        RECT -6.450 8.030 -6.190 8.290 ;
        RECT -6.130 8.030 -5.870 8.290 ;
        RECT -5.810 8.030 -5.550 8.290 ;
        RECT 21.530 8.030 21.790 8.290 ;
        RECT 21.850 8.030 22.110 8.290 ;
        RECT 22.170 8.030 22.430 8.290 ;
        RECT 22.490 8.030 22.750 8.290 ;
        RECT 22.810 8.030 23.070 8.290 ;
        RECT 41.430 8.030 41.690 8.290 ;
        RECT 41.750 8.030 42.010 8.290 ;
        RECT 42.070 8.030 42.330 8.290 ;
        RECT 42.390 8.030 42.650 8.290 ;
        RECT 42.710 8.030 42.970 8.290 ;
        RECT 43.030 8.030 43.290 8.290 ;
        RECT 43.350 8.030 43.610 8.290 ;
        RECT 43.670 8.030 43.930 8.290 ;
        RECT 43.990 8.030 44.250 8.290 ;
        RECT 44.310 8.030 44.570 8.290 ;
        RECT 44.630 8.030 44.890 8.290 ;
        RECT 44.950 8.030 45.210 8.290 ;
        RECT 45.270 8.030 45.530 8.290 ;
        RECT -9.650 2.590 -9.390 2.850 ;
        RECT -9.330 2.590 -9.070 2.850 ;
        RECT -9.010 2.590 -8.750 2.850 ;
        RECT -8.690 2.590 -8.430 2.850 ;
        RECT -8.370 2.590 -8.110 2.850 ;
        RECT -8.050 2.590 -7.790 2.850 ;
        RECT -7.730 2.590 -7.470 2.850 ;
        RECT -7.410 2.590 -7.150 2.850 ;
        RECT -7.090 2.590 -6.830 2.850 ;
        RECT -6.770 2.590 -6.510 2.850 ;
        RECT -6.450 2.590 -6.190 2.850 ;
        RECT -6.130 2.590 -5.870 2.850 ;
        RECT -5.810 2.590 -5.550 2.850 ;
        RECT 21.530 2.590 21.790 2.850 ;
        RECT 21.850 2.590 22.110 2.850 ;
        RECT 22.170 2.590 22.430 2.850 ;
        RECT 22.490 2.590 22.750 2.850 ;
        RECT 22.810 2.590 23.070 2.850 ;
        RECT 41.430 2.590 41.690 2.850 ;
        RECT 41.750 2.590 42.010 2.850 ;
        RECT 42.070 2.590 42.330 2.850 ;
        RECT 42.390 2.590 42.650 2.850 ;
        RECT 42.710 2.590 42.970 2.850 ;
        RECT 43.030 2.590 43.290 2.850 ;
        RECT 43.350 2.590 43.610 2.850 ;
        RECT 43.670 2.590 43.930 2.850 ;
        RECT 43.990 2.590 44.250 2.850 ;
        RECT 44.310 2.590 44.570 2.850 ;
        RECT 44.630 2.590 44.890 2.850 ;
        RECT 44.950 2.590 45.210 2.850 ;
        RECT 45.270 2.590 45.530 2.850 ;
      LAYER met2 ;
        RECT -9.650 35.120 -5.550 35.600 ;
        RECT 21.530 35.120 23.070 35.600 ;
        RECT 41.430 35.120 45.530 35.600 ;
        RECT -9.650 29.680 -5.550 30.160 ;
        RECT 21.530 29.680 23.070 30.160 ;
        RECT 41.430 29.680 45.530 30.160 ;
        RECT -9.650 24.240 -5.550 24.720 ;
        RECT 21.530 24.240 23.070 24.720 ;
        RECT 41.430 24.240 45.530 24.720 ;
        RECT -9.650 18.800 -5.550 19.280 ;
        RECT 21.530 18.800 23.070 19.280 ;
        RECT 41.430 18.800 45.530 19.280 ;
        RECT -9.650 13.360 -5.550 13.840 ;
        RECT 21.530 13.360 23.070 13.840 ;
        RECT 41.430 13.360 45.530 13.840 ;
        RECT -9.650 7.920 -5.550 8.400 ;
        RECT 21.530 7.920 23.070 8.400 ;
        RECT 41.430 7.920 45.530 8.400 ;
        RECT -9.650 2.480 -5.550 2.960 ;
        RECT 21.530 2.480 23.070 2.960 ;
        RECT 41.430 2.480 45.530 2.960 ;
      LAYER via2 ;
        RECT -9.540 35.220 -9.260 35.500 ;
        RECT -9.140 35.220 -8.860 35.500 ;
        RECT -8.740 35.220 -8.460 35.500 ;
        RECT -8.340 35.220 -8.060 35.500 ;
        RECT -7.940 35.220 -7.660 35.500 ;
        RECT -7.540 35.220 -7.260 35.500 ;
        RECT -7.140 35.220 -6.860 35.500 ;
        RECT -6.740 35.220 -6.460 35.500 ;
        RECT -6.340 35.220 -6.060 35.500 ;
        RECT -5.940 35.220 -5.660 35.500 ;
        RECT 21.560 35.220 21.840 35.500 ;
        RECT 21.960 35.220 22.240 35.500 ;
        RECT 22.360 35.220 22.640 35.500 ;
        RECT 22.760 35.220 23.040 35.500 ;
        RECT 41.540 35.220 41.820 35.500 ;
        RECT 41.940 35.220 42.220 35.500 ;
        RECT 42.340 35.220 42.620 35.500 ;
        RECT 42.740 35.220 43.020 35.500 ;
        RECT 43.140 35.220 43.420 35.500 ;
        RECT 43.540 35.220 43.820 35.500 ;
        RECT 43.940 35.220 44.220 35.500 ;
        RECT 44.340 35.220 44.620 35.500 ;
        RECT 44.740 35.220 45.020 35.500 ;
        RECT 45.140 35.220 45.420 35.500 ;
        RECT -9.540 29.780 -9.260 30.060 ;
        RECT -9.140 29.780 -8.860 30.060 ;
        RECT -8.740 29.780 -8.460 30.060 ;
        RECT -8.340 29.780 -8.060 30.060 ;
        RECT -7.940 29.780 -7.660 30.060 ;
        RECT -7.540 29.780 -7.260 30.060 ;
        RECT -7.140 29.780 -6.860 30.060 ;
        RECT -6.740 29.780 -6.460 30.060 ;
        RECT -6.340 29.780 -6.060 30.060 ;
        RECT -5.940 29.780 -5.660 30.060 ;
        RECT 21.560 29.780 21.840 30.060 ;
        RECT 21.960 29.780 22.240 30.060 ;
        RECT 22.360 29.780 22.640 30.060 ;
        RECT 22.760 29.780 23.040 30.060 ;
        RECT 41.540 29.780 41.820 30.060 ;
        RECT 41.940 29.780 42.220 30.060 ;
        RECT 42.340 29.780 42.620 30.060 ;
        RECT 42.740 29.780 43.020 30.060 ;
        RECT 43.140 29.780 43.420 30.060 ;
        RECT 43.540 29.780 43.820 30.060 ;
        RECT 43.940 29.780 44.220 30.060 ;
        RECT 44.340 29.780 44.620 30.060 ;
        RECT 44.740 29.780 45.020 30.060 ;
        RECT 45.140 29.780 45.420 30.060 ;
        RECT -9.540 24.340 -9.260 24.620 ;
        RECT -9.140 24.340 -8.860 24.620 ;
        RECT -8.740 24.340 -8.460 24.620 ;
        RECT -8.340 24.340 -8.060 24.620 ;
        RECT -7.940 24.340 -7.660 24.620 ;
        RECT -7.540 24.340 -7.260 24.620 ;
        RECT -7.140 24.340 -6.860 24.620 ;
        RECT -6.740 24.340 -6.460 24.620 ;
        RECT -6.340 24.340 -6.060 24.620 ;
        RECT -5.940 24.340 -5.660 24.620 ;
        RECT 21.560 24.340 21.840 24.620 ;
        RECT 21.960 24.340 22.240 24.620 ;
        RECT 22.360 24.340 22.640 24.620 ;
        RECT 22.760 24.340 23.040 24.620 ;
        RECT 41.540 24.340 41.820 24.620 ;
        RECT 41.940 24.340 42.220 24.620 ;
        RECT 42.340 24.340 42.620 24.620 ;
        RECT 42.740 24.340 43.020 24.620 ;
        RECT 43.140 24.340 43.420 24.620 ;
        RECT 43.540 24.340 43.820 24.620 ;
        RECT 43.940 24.340 44.220 24.620 ;
        RECT 44.340 24.340 44.620 24.620 ;
        RECT 44.740 24.340 45.020 24.620 ;
        RECT 45.140 24.340 45.420 24.620 ;
        RECT -9.540 18.900 -9.260 19.180 ;
        RECT -9.140 18.900 -8.860 19.180 ;
        RECT -8.740 18.900 -8.460 19.180 ;
        RECT -8.340 18.900 -8.060 19.180 ;
        RECT -7.940 18.900 -7.660 19.180 ;
        RECT -7.540 18.900 -7.260 19.180 ;
        RECT -7.140 18.900 -6.860 19.180 ;
        RECT -6.740 18.900 -6.460 19.180 ;
        RECT -6.340 18.900 -6.060 19.180 ;
        RECT -5.940 18.900 -5.660 19.180 ;
        RECT 21.560 18.900 21.840 19.180 ;
        RECT 21.960 18.900 22.240 19.180 ;
        RECT 22.360 18.900 22.640 19.180 ;
        RECT 22.760 18.900 23.040 19.180 ;
        RECT 41.540 18.900 41.820 19.180 ;
        RECT 41.940 18.900 42.220 19.180 ;
        RECT 42.340 18.900 42.620 19.180 ;
        RECT 42.740 18.900 43.020 19.180 ;
        RECT 43.140 18.900 43.420 19.180 ;
        RECT 43.540 18.900 43.820 19.180 ;
        RECT 43.940 18.900 44.220 19.180 ;
        RECT 44.340 18.900 44.620 19.180 ;
        RECT 44.740 18.900 45.020 19.180 ;
        RECT 45.140 18.900 45.420 19.180 ;
        RECT -9.540 13.460 -9.260 13.740 ;
        RECT -9.140 13.460 -8.860 13.740 ;
        RECT -8.740 13.460 -8.460 13.740 ;
        RECT -8.340 13.460 -8.060 13.740 ;
        RECT -7.940 13.460 -7.660 13.740 ;
        RECT -7.540 13.460 -7.260 13.740 ;
        RECT -7.140 13.460 -6.860 13.740 ;
        RECT -6.740 13.460 -6.460 13.740 ;
        RECT -6.340 13.460 -6.060 13.740 ;
        RECT -5.940 13.460 -5.660 13.740 ;
        RECT 21.560 13.460 21.840 13.740 ;
        RECT 21.960 13.460 22.240 13.740 ;
        RECT 22.360 13.460 22.640 13.740 ;
        RECT 22.760 13.460 23.040 13.740 ;
        RECT 41.540 13.460 41.820 13.740 ;
        RECT 41.940 13.460 42.220 13.740 ;
        RECT 42.340 13.460 42.620 13.740 ;
        RECT 42.740 13.460 43.020 13.740 ;
        RECT 43.140 13.460 43.420 13.740 ;
        RECT 43.540 13.460 43.820 13.740 ;
        RECT 43.940 13.460 44.220 13.740 ;
        RECT 44.340 13.460 44.620 13.740 ;
        RECT 44.740 13.460 45.020 13.740 ;
        RECT 45.140 13.460 45.420 13.740 ;
        RECT -9.540 8.020 -9.260 8.300 ;
        RECT -9.140 8.020 -8.860 8.300 ;
        RECT -8.740 8.020 -8.460 8.300 ;
        RECT -8.340 8.020 -8.060 8.300 ;
        RECT -7.940 8.020 -7.660 8.300 ;
        RECT -7.540 8.020 -7.260 8.300 ;
        RECT -7.140 8.020 -6.860 8.300 ;
        RECT -6.740 8.020 -6.460 8.300 ;
        RECT -6.340 8.020 -6.060 8.300 ;
        RECT -5.940 8.020 -5.660 8.300 ;
        RECT 21.560 8.020 21.840 8.300 ;
        RECT 21.960 8.020 22.240 8.300 ;
        RECT 22.360 8.020 22.640 8.300 ;
        RECT 22.760 8.020 23.040 8.300 ;
        RECT 41.540 8.020 41.820 8.300 ;
        RECT 41.940 8.020 42.220 8.300 ;
        RECT 42.340 8.020 42.620 8.300 ;
        RECT 42.740 8.020 43.020 8.300 ;
        RECT 43.140 8.020 43.420 8.300 ;
        RECT 43.540 8.020 43.820 8.300 ;
        RECT 43.940 8.020 44.220 8.300 ;
        RECT 44.340 8.020 44.620 8.300 ;
        RECT 44.740 8.020 45.020 8.300 ;
        RECT 45.140 8.020 45.420 8.300 ;
        RECT -9.540 2.580 -9.260 2.860 ;
        RECT -9.140 2.580 -8.860 2.860 ;
        RECT -8.740 2.580 -8.460 2.860 ;
        RECT -8.340 2.580 -8.060 2.860 ;
        RECT -7.940 2.580 -7.660 2.860 ;
        RECT -7.540 2.580 -7.260 2.860 ;
        RECT -7.140 2.580 -6.860 2.860 ;
        RECT -6.740 2.580 -6.460 2.860 ;
        RECT -6.340 2.580 -6.060 2.860 ;
        RECT -5.940 2.580 -5.660 2.860 ;
        RECT 21.560 2.580 21.840 2.860 ;
        RECT 21.960 2.580 22.240 2.860 ;
        RECT 22.360 2.580 22.640 2.860 ;
        RECT 22.760 2.580 23.040 2.860 ;
        RECT 41.540 2.580 41.820 2.860 ;
        RECT 41.940 2.580 42.220 2.860 ;
        RECT 42.340 2.580 42.620 2.860 ;
        RECT 42.740 2.580 43.020 2.860 ;
        RECT 43.140 2.580 43.420 2.860 ;
        RECT 43.540 2.580 43.820 2.860 ;
        RECT 43.940 2.580 44.220 2.860 ;
        RECT 44.340 2.580 44.620 2.860 ;
        RECT 44.740 2.580 45.020 2.860 ;
        RECT 45.140 2.580 45.420 2.860 ;
      LAYER met3 ;
        RECT -9.700 35.195 -5.500 35.525 ;
        RECT 21.500 35.195 23.100 35.525 ;
        RECT 41.380 35.195 45.580 35.525 ;
        RECT -9.700 29.755 -5.500 30.085 ;
        RECT 21.500 29.755 23.100 30.085 ;
        RECT 41.380 29.755 45.580 30.085 ;
        RECT -9.700 24.315 -5.500 24.645 ;
        RECT 21.500 24.315 23.100 24.645 ;
        RECT 41.380 24.315 45.580 24.645 ;
        RECT -9.700 18.875 -5.500 19.205 ;
        RECT 21.500 18.875 23.100 19.205 ;
        RECT 41.380 18.875 45.580 19.205 ;
        RECT -9.700 13.435 -5.500 13.765 ;
        RECT 21.500 13.435 23.100 13.765 ;
        RECT 41.380 13.435 45.580 13.765 ;
        RECT -9.700 7.995 -5.500 8.325 ;
        RECT 21.500 7.995 23.100 8.325 ;
        RECT 41.380 7.995 45.580 8.325 ;
        RECT -9.700 2.555 -5.500 2.885 ;
        RECT 21.500 2.555 23.100 2.885 ;
        RECT 41.380 2.555 45.580 2.885 ;
      LAYER via3 ;
        RECT -9.560 35.200 -9.240 35.520 ;
        RECT -9.160 35.200 -8.840 35.520 ;
        RECT -8.760 35.200 -8.440 35.520 ;
        RECT -8.360 35.200 -8.040 35.520 ;
        RECT -7.960 35.200 -7.640 35.520 ;
        RECT -7.560 35.200 -7.240 35.520 ;
        RECT -7.160 35.200 -6.840 35.520 ;
        RECT -6.760 35.200 -6.440 35.520 ;
        RECT -6.360 35.200 -6.040 35.520 ;
        RECT -5.960 35.200 -5.640 35.520 ;
        RECT 21.540 35.200 21.860 35.520 ;
        RECT 21.940 35.200 22.260 35.520 ;
        RECT 22.340 35.200 22.660 35.520 ;
        RECT 22.740 35.200 23.060 35.520 ;
        RECT 41.520 35.200 41.840 35.520 ;
        RECT 41.920 35.200 42.240 35.520 ;
        RECT 42.320 35.200 42.640 35.520 ;
        RECT 42.720 35.200 43.040 35.520 ;
        RECT 43.120 35.200 43.440 35.520 ;
        RECT 43.520 35.200 43.840 35.520 ;
        RECT 43.920 35.200 44.240 35.520 ;
        RECT 44.320 35.200 44.640 35.520 ;
        RECT 44.720 35.200 45.040 35.520 ;
        RECT 45.120 35.200 45.440 35.520 ;
        RECT -9.560 29.760 -9.240 30.080 ;
        RECT -9.160 29.760 -8.840 30.080 ;
        RECT -8.760 29.760 -8.440 30.080 ;
        RECT -8.360 29.760 -8.040 30.080 ;
        RECT -7.960 29.760 -7.640 30.080 ;
        RECT -7.560 29.760 -7.240 30.080 ;
        RECT -7.160 29.760 -6.840 30.080 ;
        RECT -6.760 29.760 -6.440 30.080 ;
        RECT -6.360 29.760 -6.040 30.080 ;
        RECT -5.960 29.760 -5.640 30.080 ;
        RECT 21.540 29.760 21.860 30.080 ;
        RECT 21.940 29.760 22.260 30.080 ;
        RECT 22.340 29.760 22.660 30.080 ;
        RECT 22.740 29.760 23.060 30.080 ;
        RECT 41.520 29.760 41.840 30.080 ;
        RECT 41.920 29.760 42.240 30.080 ;
        RECT 42.320 29.760 42.640 30.080 ;
        RECT 42.720 29.760 43.040 30.080 ;
        RECT 43.120 29.760 43.440 30.080 ;
        RECT 43.520 29.760 43.840 30.080 ;
        RECT 43.920 29.760 44.240 30.080 ;
        RECT 44.320 29.760 44.640 30.080 ;
        RECT 44.720 29.760 45.040 30.080 ;
        RECT 45.120 29.760 45.440 30.080 ;
        RECT -9.560 24.320 -9.240 24.640 ;
        RECT -9.160 24.320 -8.840 24.640 ;
        RECT -8.760 24.320 -8.440 24.640 ;
        RECT -8.360 24.320 -8.040 24.640 ;
        RECT -7.960 24.320 -7.640 24.640 ;
        RECT -7.560 24.320 -7.240 24.640 ;
        RECT -7.160 24.320 -6.840 24.640 ;
        RECT -6.760 24.320 -6.440 24.640 ;
        RECT -6.360 24.320 -6.040 24.640 ;
        RECT -5.960 24.320 -5.640 24.640 ;
        RECT 21.540 24.320 21.860 24.640 ;
        RECT 21.940 24.320 22.260 24.640 ;
        RECT 22.340 24.320 22.660 24.640 ;
        RECT 22.740 24.320 23.060 24.640 ;
        RECT 41.520 24.320 41.840 24.640 ;
        RECT 41.920 24.320 42.240 24.640 ;
        RECT 42.320 24.320 42.640 24.640 ;
        RECT 42.720 24.320 43.040 24.640 ;
        RECT 43.120 24.320 43.440 24.640 ;
        RECT 43.520 24.320 43.840 24.640 ;
        RECT 43.920 24.320 44.240 24.640 ;
        RECT 44.320 24.320 44.640 24.640 ;
        RECT 44.720 24.320 45.040 24.640 ;
        RECT 45.120 24.320 45.440 24.640 ;
        RECT -9.560 18.880 -9.240 19.200 ;
        RECT -9.160 18.880 -8.840 19.200 ;
        RECT -8.760 18.880 -8.440 19.200 ;
        RECT -8.360 18.880 -8.040 19.200 ;
        RECT -7.960 18.880 -7.640 19.200 ;
        RECT -7.560 18.880 -7.240 19.200 ;
        RECT -7.160 18.880 -6.840 19.200 ;
        RECT -6.760 18.880 -6.440 19.200 ;
        RECT -6.360 18.880 -6.040 19.200 ;
        RECT -5.960 18.880 -5.640 19.200 ;
        RECT 21.540 18.880 21.860 19.200 ;
        RECT 21.940 18.880 22.260 19.200 ;
        RECT 22.340 18.880 22.660 19.200 ;
        RECT 22.740 18.880 23.060 19.200 ;
        RECT 41.520 18.880 41.840 19.200 ;
        RECT 41.920 18.880 42.240 19.200 ;
        RECT 42.320 18.880 42.640 19.200 ;
        RECT 42.720 18.880 43.040 19.200 ;
        RECT 43.120 18.880 43.440 19.200 ;
        RECT 43.520 18.880 43.840 19.200 ;
        RECT 43.920 18.880 44.240 19.200 ;
        RECT 44.320 18.880 44.640 19.200 ;
        RECT 44.720 18.880 45.040 19.200 ;
        RECT 45.120 18.880 45.440 19.200 ;
        RECT -9.560 13.440 -9.240 13.760 ;
        RECT -9.160 13.440 -8.840 13.760 ;
        RECT -8.760 13.440 -8.440 13.760 ;
        RECT -8.360 13.440 -8.040 13.760 ;
        RECT -7.960 13.440 -7.640 13.760 ;
        RECT -7.560 13.440 -7.240 13.760 ;
        RECT -7.160 13.440 -6.840 13.760 ;
        RECT -6.760 13.440 -6.440 13.760 ;
        RECT -6.360 13.440 -6.040 13.760 ;
        RECT -5.960 13.440 -5.640 13.760 ;
        RECT 21.540 13.440 21.860 13.760 ;
        RECT 21.940 13.440 22.260 13.760 ;
        RECT 22.340 13.440 22.660 13.760 ;
        RECT 22.740 13.440 23.060 13.760 ;
        RECT 41.520 13.440 41.840 13.760 ;
        RECT 41.920 13.440 42.240 13.760 ;
        RECT 42.320 13.440 42.640 13.760 ;
        RECT 42.720 13.440 43.040 13.760 ;
        RECT 43.120 13.440 43.440 13.760 ;
        RECT 43.520 13.440 43.840 13.760 ;
        RECT 43.920 13.440 44.240 13.760 ;
        RECT 44.320 13.440 44.640 13.760 ;
        RECT 44.720 13.440 45.040 13.760 ;
        RECT 45.120 13.440 45.440 13.760 ;
        RECT -9.560 8.000 -9.240 8.320 ;
        RECT -9.160 8.000 -8.840 8.320 ;
        RECT -8.760 8.000 -8.440 8.320 ;
        RECT -8.360 8.000 -8.040 8.320 ;
        RECT -7.960 8.000 -7.640 8.320 ;
        RECT -7.560 8.000 -7.240 8.320 ;
        RECT -7.160 8.000 -6.840 8.320 ;
        RECT -6.760 8.000 -6.440 8.320 ;
        RECT -6.360 8.000 -6.040 8.320 ;
        RECT -5.960 8.000 -5.640 8.320 ;
        RECT 21.540 8.000 21.860 8.320 ;
        RECT 21.940 8.000 22.260 8.320 ;
        RECT 22.340 8.000 22.660 8.320 ;
        RECT 22.740 8.000 23.060 8.320 ;
        RECT 41.520 8.000 41.840 8.320 ;
        RECT 41.920 8.000 42.240 8.320 ;
        RECT 42.320 8.000 42.640 8.320 ;
        RECT 42.720 8.000 43.040 8.320 ;
        RECT 43.120 8.000 43.440 8.320 ;
        RECT 43.520 8.000 43.840 8.320 ;
        RECT 43.920 8.000 44.240 8.320 ;
        RECT 44.320 8.000 44.640 8.320 ;
        RECT 44.720 8.000 45.040 8.320 ;
        RECT 45.120 8.000 45.440 8.320 ;
        RECT -9.560 2.560 -9.240 2.880 ;
        RECT -9.160 2.560 -8.840 2.880 ;
        RECT -8.760 2.560 -8.440 2.880 ;
        RECT -8.360 2.560 -8.040 2.880 ;
        RECT -7.960 2.560 -7.640 2.880 ;
        RECT -7.560 2.560 -7.240 2.880 ;
        RECT -7.160 2.560 -6.840 2.880 ;
        RECT -6.760 2.560 -6.440 2.880 ;
        RECT -6.360 2.560 -6.040 2.880 ;
        RECT -5.960 2.560 -5.640 2.880 ;
        RECT 21.540 2.560 21.860 2.880 ;
        RECT 21.940 2.560 22.260 2.880 ;
        RECT 22.340 2.560 22.660 2.880 ;
        RECT 22.740 2.560 23.060 2.880 ;
        RECT 41.520 2.560 41.840 2.880 ;
        RECT 41.920 2.560 42.240 2.880 ;
        RECT 42.320 2.560 42.640 2.880 ;
        RECT 42.720 2.560 43.040 2.880 ;
        RECT 43.120 2.560 43.440 2.880 ;
        RECT 43.520 2.560 43.840 2.880 ;
        RECT 43.920 2.560 44.240 2.880 ;
        RECT 44.320 2.560 44.640 2.880 ;
        RECT 44.720 2.560 45.040 2.880 ;
        RECT 45.120 2.560 45.440 2.880 ;
      LAYER met4 ;
        RECT -9.700 -9.280 -5.500 50.080 ;
        RECT 21.500 -9.280 23.100 50.080 ;
        RECT 41.380 -9.280 45.580 50.080 ;
      LAYER via4 ;
        RECT -8.990 46.590 -6.210 49.370 ;
        RECT -8.990 21.890 -7.810 23.070 ;
        RECT -7.390 21.890 -6.210 23.070 ;
        RECT -8.990 -8.570 -6.210 -5.790 ;
        RECT 21.710 48.190 22.890 49.370 ;
        RECT 21.710 46.590 22.890 47.770 ;
        RECT 21.710 21.890 22.890 23.070 ;
        RECT 21.710 -6.970 22.890 -5.790 ;
        RECT 21.710 -8.570 22.890 -7.390 ;
        RECT 42.090 46.590 44.870 49.370 ;
        RECT 42.090 21.890 43.270 23.070 ;
        RECT 43.690 21.890 44.870 23.070 ;
        RECT 42.090 -8.570 44.870 -5.790 ;
      LAYER met5 ;
        RECT -9.700 45.880 45.580 50.080 ;
        RECT -9.700 21.680 45.580 23.280 ;
        RECT -9.700 -9.280 45.580 -5.080 ;
    END
  END VGND
  PIN clk
    ANTENNAGATEAREA 0.213000 ;
    PORT
      LAYER li1 ;
        RECT 16.985 14.355 17.335 14.925 ;
      LAYER mcon ;
        RECT 17.165 14.705 17.335 14.875 ;
      LAYER met1 ;
        RECT 17.105 14.860 17.395 14.905 ;
        RECT 19.390 14.860 19.710 14.920 ;
        RECT 17.105 14.720 19.710 14.860 ;
        RECT 17.105 14.675 17.395 14.720 ;
        RECT 19.390 14.660 19.710 14.720 ;
      LAYER via ;
        RECT 19.420 14.660 19.680 14.920 ;
      LAYER met2 ;
        RECT 19.480 14.950 19.620 40.000 ;
        RECT 19.420 14.630 19.680 14.950 ;
    END
  END clk
  PIN clk_in
    ANTENNAGATEAREA 0.213000 ;
    PORT
      LAYER li1 ;
        RECT 18.825 36.105 19.185 36.685 ;
      LAYER mcon ;
        RECT 19.005 36.465 19.175 36.635 ;
      LAYER met1 ;
        RECT 18.470 36.620 18.790 36.680 ;
        RECT 18.945 36.620 19.235 36.665 ;
        RECT 18.470 36.480 19.235 36.620 ;
        RECT 18.470 36.420 18.790 36.480 ;
        RECT 18.945 36.435 19.235 36.480 ;
      LAYER via ;
        RECT 18.500 36.420 18.760 36.680 ;
      LAYER met2 ;
        RECT 18.560 36.710 18.700 40.000 ;
        RECT 18.500 36.390 18.760 36.710 ;
    END
  END clk_in
  PIN clk0
    ANTENNADIFFAREA 3.564000 ;
    PORT
      LAYER li1 ;
        RECT 22.815 29.660 23.065 29.665 ;
        RECT 23.735 29.660 23.905 29.665 ;
        RECT 24.575 29.660 24.745 29.665 ;
        RECT 22.815 29.185 23.145 29.660 ;
        RECT 23.655 29.185 23.985 29.660 ;
        RECT 24.495 29.185 24.825 29.660 ;
        RECT 25.335 29.185 25.665 29.660 ;
        RECT 26.175 29.185 26.505 29.660 ;
        RECT 27.015 29.185 27.345 29.660 ;
        RECT 27.855 29.185 28.185 29.660 ;
        RECT 28.695 29.185 29.025 29.660 ;
        RECT 29.540 29.185 29.815 29.555 ;
        RECT 22.815 29.015 29.815 29.185 ;
        RECT 29.435 28.475 29.815 29.015 ;
        RECT 22.815 28.305 29.815 28.475 ;
        RECT 22.815 27.455 23.145 28.305 ;
        RECT 23.655 27.455 23.985 28.305 ;
        RECT 24.495 27.455 24.825 28.305 ;
        RECT 25.335 27.455 25.665 28.305 ;
        RECT 26.175 27.455 26.505 28.305 ;
        RECT 27.015 27.455 27.345 28.305 ;
        RECT 27.855 27.455 28.185 28.305 ;
        RECT 28.695 27.455 29.025 28.305 ;
        RECT 29.540 27.560 29.815 28.305 ;
      LAYER mcon ;
        RECT 29.585 29.325 29.755 29.495 ;
      LAYER met1 ;
        RECT 29.510 29.480 29.830 29.540 ;
        RECT 29.315 29.340 29.830 29.480 ;
        RECT 29.510 29.280 29.830 29.340 ;
      LAYER via ;
        RECT 29.540 29.280 29.800 29.540 ;
      LAYER met2 ;
        RECT 29.530 30.075 29.810 30.445 ;
        RECT 29.600 29.570 29.740 30.075 ;
        RECT 29.540 29.250 29.800 29.570 ;
      LAYER via2 ;
        RECT 29.530 30.120 29.810 30.400 ;
      LAYER met3 ;
        RECT 29.505 30.410 29.835 30.425 ;
        RECT 29.505 30.110 35.000 30.410 ;
        RECT 29.505 30.095 29.835 30.110 ;
    END
  END clk0
  PIN clk0b
    ANTENNADIFFAREA 3.564000 ;
    PORT
      LAYER li1 ;
        RECT 26.495 31.535 26.825 32.385 ;
        RECT 27.335 31.535 27.665 32.385 ;
        RECT 28.175 31.535 28.505 32.385 ;
        RECT 29.015 31.535 29.345 32.385 ;
        RECT 29.855 31.535 30.185 32.385 ;
        RECT 30.695 31.535 31.025 32.385 ;
        RECT 31.535 31.535 31.865 32.385 ;
        RECT 32.375 31.535 32.705 32.385 ;
        RECT 33.220 31.535 33.495 32.280 ;
        RECT 26.495 31.365 33.495 31.535 ;
        RECT 33.115 30.825 33.495 31.365 ;
        RECT 26.495 30.655 33.495 30.825 ;
        RECT 26.495 30.180 26.825 30.655 ;
        RECT 27.335 30.180 27.665 30.655 ;
        RECT 28.175 30.180 28.505 30.655 ;
        RECT 29.015 30.180 29.345 30.655 ;
        RECT 29.855 30.180 30.185 30.655 ;
        RECT 30.695 30.180 31.025 30.655 ;
        RECT 31.535 30.180 31.865 30.655 ;
        RECT 32.375 30.180 32.705 30.655 ;
        RECT 33.220 30.285 33.495 30.655 ;
        RECT 26.495 30.175 26.745 30.180 ;
        RECT 27.415 30.175 27.585 30.180 ;
        RECT 28.255 30.175 28.425 30.180 ;
      LAYER mcon ;
        RECT 33.265 31.365 33.435 31.535 ;
      LAYER met1 ;
        RECT 33.190 31.520 33.510 31.580 ;
        RECT 32.995 31.380 33.510 31.520 ;
        RECT 33.190 31.320 33.510 31.380 ;
      LAYER via ;
        RECT 33.220 31.320 33.480 31.580 ;
      LAYER met2 ;
        RECT 33.210 31.435 33.490 31.805 ;
        RECT 33.220 31.290 33.480 31.435 ;
      LAYER via2 ;
        RECT 33.210 31.480 33.490 31.760 ;
      LAYER met3 ;
        RECT 33.185 31.770 33.515 31.785 ;
        RECT 33.185 31.470 35.000 31.770 ;
        RECT 33.185 31.455 33.515 31.470 ;
    END
  END clk0b
  PIN clk1
    ANTENNADIFFAREA 3.564000 ;
    PORT
      LAYER li1 ;
        RECT 26.495 26.095 26.825 26.945 ;
        RECT 27.335 26.095 27.665 26.945 ;
        RECT 28.175 26.095 28.505 26.945 ;
        RECT 29.015 26.095 29.345 26.945 ;
        RECT 29.855 26.095 30.185 26.945 ;
        RECT 30.695 26.095 31.025 26.945 ;
        RECT 31.535 26.095 31.865 26.945 ;
        RECT 32.375 26.095 32.705 26.945 ;
        RECT 33.220 26.095 33.495 26.840 ;
        RECT 26.495 25.925 33.495 26.095 ;
        RECT 33.115 25.385 33.495 25.925 ;
        RECT 26.495 25.215 33.495 25.385 ;
        RECT 26.495 24.740 26.825 25.215 ;
        RECT 27.335 24.740 27.665 25.215 ;
        RECT 28.175 24.740 28.505 25.215 ;
        RECT 29.015 24.740 29.345 25.215 ;
        RECT 29.855 24.740 30.185 25.215 ;
        RECT 30.695 24.740 31.025 25.215 ;
        RECT 31.535 24.740 31.865 25.215 ;
        RECT 32.375 24.740 32.705 25.215 ;
        RECT 33.220 24.845 33.495 25.215 ;
        RECT 26.495 24.735 26.745 24.740 ;
        RECT 27.415 24.735 27.585 24.740 ;
        RECT 28.255 24.735 28.425 24.740 ;
      LAYER mcon ;
        RECT 33.265 26.605 33.435 26.775 ;
      LAYER met1 ;
        RECT 33.190 26.760 33.510 26.820 ;
        RECT 32.995 26.620 33.510 26.760 ;
        RECT 33.190 26.560 33.510 26.620 ;
      LAYER via ;
        RECT 33.220 26.560 33.480 26.820 ;
      LAYER met2 ;
        RECT 33.210 27.355 33.490 27.725 ;
        RECT 33.280 26.850 33.420 27.355 ;
        RECT 33.220 26.530 33.480 26.850 ;
      LAYER via2 ;
        RECT 33.210 27.400 33.490 27.680 ;
      LAYER met3 ;
        RECT 33.185 27.690 33.515 27.705 ;
        RECT 33.185 27.390 35.000 27.690 ;
        RECT 33.185 27.375 33.515 27.390 ;
    END
  END clk1
  PIN clk1b
    ANTENNADIFFAREA 3.564000 ;
    PORT
      LAYER li1 ;
        RECT 22.815 35.100 23.065 35.105 ;
        RECT 23.735 35.100 23.905 35.105 ;
        RECT 24.575 35.100 24.745 35.105 ;
        RECT 22.815 34.625 23.145 35.100 ;
        RECT 23.655 34.625 23.985 35.100 ;
        RECT 24.495 34.625 24.825 35.100 ;
        RECT 25.335 34.625 25.665 35.100 ;
        RECT 26.175 34.625 26.505 35.100 ;
        RECT 27.015 34.625 27.345 35.100 ;
        RECT 27.855 34.625 28.185 35.100 ;
        RECT 28.695 34.625 29.025 35.100 ;
        RECT 29.540 34.625 29.815 34.995 ;
        RECT 22.815 34.455 29.815 34.625 ;
        RECT 29.435 33.915 29.815 34.455 ;
        RECT 22.815 33.745 29.815 33.915 ;
        RECT 22.815 32.895 23.145 33.745 ;
        RECT 23.655 32.895 23.985 33.745 ;
        RECT 24.495 32.895 24.825 33.745 ;
        RECT 25.335 32.895 25.665 33.745 ;
        RECT 26.175 32.895 26.505 33.745 ;
        RECT 27.015 32.895 27.345 33.745 ;
        RECT 27.855 32.895 28.185 33.745 ;
        RECT 28.695 32.895 29.025 33.745 ;
        RECT 29.540 33.000 29.815 33.745 ;
      LAYER mcon ;
        RECT 29.585 33.065 29.755 33.235 ;
      LAYER met1 ;
        RECT 29.525 33.220 29.815 33.265 ;
        RECT 29.970 33.220 30.290 33.280 ;
        RECT 29.525 33.080 30.290 33.220 ;
        RECT 29.525 33.035 29.815 33.080 ;
        RECT 29.970 33.020 30.290 33.080 ;
      LAYER via ;
        RECT 30.000 33.020 30.260 33.280 ;
      LAYER met2 ;
        RECT 30.000 32.990 30.260 33.310 ;
        RECT 30.060 29.085 30.200 32.990 ;
        RECT 29.990 28.715 30.270 29.085 ;
      LAYER via2 ;
        RECT 29.990 28.760 30.270 29.040 ;
      LAYER met3 ;
        RECT 29.965 29.050 30.295 29.065 ;
        RECT 29.965 28.750 35.000 29.050 ;
        RECT 29.965 28.735 30.295 28.750 ;
    END
  END clk1b
  PIN control
    ANTENNAGATEAREA 0.196500 ;
    PORT
      LAYER li1 ;
        RECT 32.685 12.245 33.015 12.615 ;
      LAYER mcon ;
        RECT 32.805 12.325 32.975 12.495 ;
      LAYER met1 ;
        RECT 32.730 12.480 33.050 12.540 ;
        RECT 32.535 12.340 33.050 12.480 ;
        RECT 32.730 12.280 33.050 12.340 ;
      LAYER via ;
        RECT 32.760 12.280 33.020 12.540 ;
      LAYER met2 ;
        RECT 32.750 16.475 33.030 16.845 ;
        RECT 32.820 12.570 32.960 16.475 ;
        RECT 32.760 12.250 33.020 12.570 ;
      LAYER via2 ;
        RECT 32.750 16.520 33.030 16.800 ;
      LAYER met3 ;
        RECT 32.725 16.810 33.055 16.825 ;
        RECT 32.725 16.510 35.000 16.810 ;
        RECT 32.725 16.495 33.055 16.510 ;
    END
  END control
  PIN rst_n
    ANTENNAGATEAREA 0.213000 ;
    PORT
      LAYER li1 ;
        RECT 31.245 17.715 31.595 18.285 ;
      LAYER mcon ;
        RECT 31.425 17.765 31.595 17.935 ;
      LAYER met1 ;
        RECT 31.350 17.920 31.670 17.980 ;
        RECT 31.155 17.780 31.670 17.920 ;
        RECT 31.350 17.720 31.670 17.780 ;
      LAYER via ;
        RECT 31.380 17.720 31.640 17.980 ;
      LAYER met2 ;
        RECT 31.370 17.835 31.650 18.205 ;
        RECT 31.380 17.690 31.640 17.835 ;
      LAYER via2 ;
        RECT 31.370 17.880 31.650 18.160 ;
      LAYER met3 ;
        RECT 31.345 18.170 31.675 18.185 ;
        RECT 31.345 17.870 35.000 18.170 ;
        RECT 31.345 17.855 31.675 17.870 ;
    END
  END rst_n
  OBS
      LAYER pwell ;
        RECT 2.430 35.240 2.650 35.480 ;
        RECT 6.110 35.240 6.330 35.480 ;
        RECT 9.790 35.240 10.010 35.480 ;
        RECT 16.585 35.465 17.935 36.375 ;
        RECT 18.405 35.465 20.235 36.145 ;
        RECT 20.450 35.465 21.380 36.375 ;
        RECT 22.105 35.465 23.455 36.375 ;
        RECT 23.945 35.465 25.295 36.375 ;
        RECT 25.510 35.465 26.440 36.375 ;
        RECT 26.890 35.465 27.820 36.375 ;
        RECT 28.065 35.465 29.895 36.375 ;
        RECT 30.365 35.465 31.715 36.375 ;
        RECT 31.765 35.465 33.115 36.375 ;
        RECT 13.515 35.300 13.625 35.420 ;
        RECT 15.335 35.415 15.495 35.420 ;
        RECT 15.320 35.310 15.495 35.415 ;
        RECT 15.320 35.305 15.440 35.310 ;
        RECT 15.785 35.275 15.955 35.445 ;
        RECT 16.700 35.275 16.870 35.465 ;
        RECT 17.165 35.275 17.335 35.445 ;
        RECT 18.080 35.305 18.200 35.415 ;
        RECT 18.545 35.275 18.715 35.465 ;
        RECT 20.450 35.445 20.555 35.465 ;
        RECT 19.460 35.305 19.580 35.415 ;
        RECT 15.850 35.255 15.955 35.275 ;
        RECT 17.230 35.255 17.335 35.275 ;
        RECT 19.930 35.255 20.100 35.445 ;
        RECT 20.385 35.275 20.555 35.445 ;
        RECT 21.760 35.305 21.880 35.415 ;
        RECT 22.220 35.275 22.390 35.465 ;
        RECT 23.600 35.305 23.720 35.415 ;
        RECT 24.060 35.275 24.230 35.465 ;
        RECT 25.510 35.445 25.615 35.465 ;
        RECT 26.890 35.445 26.995 35.465 ;
        RECT 25.445 35.275 25.615 35.445 ;
        RECT 26.825 35.275 26.995 35.445 ;
        RECT 28.210 35.275 28.380 35.465 ;
        RECT 30.510 35.445 30.680 35.465 ;
        RECT 30.500 35.275 30.680 35.445 ;
        RECT 31.880 35.275 32.050 35.465 ;
        RECT 33.260 35.305 33.380 35.415 ;
        RECT 30.500 35.255 30.670 35.275 ;
        RECT 15.850 34.345 16.780 35.255 ;
        RECT 17.230 34.345 18.160 35.255 ;
        RECT 19.785 34.345 29.535 35.255 ;
        RECT 30.385 34.345 31.735 35.255 ;
        RECT 2.430 29.800 2.650 30.040 ;
        RECT 6.110 29.800 6.330 30.040 ;
        RECT 9.790 29.800 10.010 30.040 ;
        RECT 17.690 30.025 18.620 30.935 ;
        RECT 18.885 30.025 20.235 30.935 ;
        RECT 21.165 30.025 22.995 30.935 ;
        RECT 23.465 30.025 33.215 30.935 ;
        RECT 17.690 30.005 17.795 30.025 ;
        RECT 13.515 29.860 13.625 29.980 ;
        RECT 15.335 29.975 15.495 29.980 ;
        RECT 15.320 29.870 15.495 29.975 ;
        RECT 15.320 29.865 15.440 29.870 ;
        RECT 15.785 29.815 15.955 30.005 ;
        RECT 16.715 29.870 16.875 29.980 ;
        RECT 17.625 29.835 17.795 30.005 ;
        RECT 18.545 29.815 18.715 30.005 ;
        RECT 19.000 29.835 19.170 30.025 ;
        RECT 19.930 29.815 20.100 30.005 ;
        RECT 20.395 29.870 20.555 29.980 ;
        RECT 21.310 29.835 21.480 30.025 ;
        RECT 23.140 29.865 23.260 29.975 ;
        RECT 23.610 29.835 23.780 30.025 ;
        RECT 30.510 29.815 30.680 30.005 ;
        RECT 32.815 29.860 32.975 29.970 ;
        RECT 15.645 29.135 18.385 29.815 ;
        RECT 18.415 28.905 19.765 29.815 ;
        RECT 19.785 28.905 29.535 29.815 ;
        RECT 30.365 28.905 32.555 29.815 ;
        RECT 7.805 25.265 8.725 25.485 ;
        RECT 14.805 25.385 15.725 25.495 ;
        RECT 13.390 25.265 15.725 25.385 ;
        RECT 2.430 24.360 2.650 24.600 ;
        RECT 6.110 24.430 6.330 24.600 ;
        RECT 6.445 24.585 15.725 25.265 ;
        RECT 23.465 24.585 33.215 25.495 ;
        RECT 6.120 24.425 6.240 24.430 ;
        RECT 6.585 24.395 6.755 24.585 ;
        RECT 9.815 24.420 9.975 24.530 ;
        RECT 10.725 24.375 10.895 24.565 ;
        RECT 16.690 24.375 16.910 24.530 ;
        RECT 20.385 24.375 20.555 24.565 ;
        RECT 22.235 24.430 22.395 24.540 ;
        RECT 23.140 24.425 23.260 24.535 ;
        RECT 23.610 24.395 23.780 24.585 ;
        RECT 30.505 24.395 30.675 24.565 ;
        RECT 31.885 24.395 32.055 24.565 ;
        RECT 33.260 24.425 33.380 24.535 ;
        RECT 30.570 24.375 30.675 24.395 ;
        RECT 31.950 24.375 32.055 24.395 ;
        RECT 10.585 23.695 19.865 24.375 ;
        RECT 20.245 23.695 29.525 24.375 ;
        RECT 11.945 23.475 12.865 23.695 ;
        RECT 17.530 23.575 19.865 23.695 ;
        RECT 18.945 23.465 19.865 23.575 ;
        RECT 21.605 23.475 22.525 23.695 ;
        RECT 27.190 23.575 29.525 23.695 ;
        RECT 28.605 23.465 29.525 23.575 ;
        RECT 30.570 23.465 31.500 24.375 ;
        RECT 31.950 23.465 32.880 24.375 ;
        RECT 7.345 19.825 8.265 20.045 ;
        RECT 14.345 19.945 15.265 20.055 ;
        RECT 12.930 19.825 15.265 19.945 ;
        RECT 18.385 19.825 19.305 20.045 ;
        RECT 25.385 19.945 26.305 20.055 ;
        RECT 23.970 19.825 26.305 19.945 ;
        RECT 2.430 18.920 2.650 19.160 ;
        RECT 5.985 19.145 15.265 19.825 ;
        RECT 17.025 19.145 26.305 19.825 ;
        RECT 28.545 19.145 29.895 20.055 ;
        RECT 6.110 18.990 6.330 19.145 ;
        RECT 9.790 18.990 10.010 19.145 ;
        RECT 13.470 18.990 13.690 19.145 ;
        RECT 6.125 18.955 6.295 18.990 ;
        RECT 15.780 18.985 15.900 19.095 ;
        RECT 16.700 18.985 16.820 19.095 ;
        RECT 17.165 18.955 17.335 19.145 ;
        RECT 19.015 18.980 19.175 19.090 ;
        RECT 19.920 18.935 20.090 19.125 ;
        RECT 21.300 18.935 21.470 19.125 ;
        RECT 22.680 18.935 22.850 19.125 ;
        RECT 24.065 18.955 24.235 19.125 ;
        RECT 25.455 18.980 25.615 19.090 ;
        RECT 26.360 18.985 26.480 19.095 ;
        RECT 24.130 18.935 24.235 18.955 ;
        RECT 26.830 18.935 27.000 19.125 ;
        RECT 28.660 18.955 28.830 19.145 ;
        RECT 29.135 18.980 29.295 19.090 ;
        RECT 19.805 18.025 21.155 18.935 ;
        RECT 21.185 18.025 22.535 18.935 ;
        RECT 22.565 18.025 23.915 18.935 ;
        RECT 24.130 18.025 25.060 18.935 ;
        RECT 26.685 18.025 28.875 18.935 ;
        RECT 30.030 18.920 30.250 19.090 ;
        RECT 30.500 18.985 30.620 19.095 ;
        RECT 30.965 18.935 31.135 19.125 ;
        RECT 30.825 18.255 33.565 18.935 ;
        RECT 22.110 14.385 23.455 14.615 ;
        RECT 2.430 13.480 2.650 13.720 ;
        RECT 6.110 13.480 6.330 13.720 ;
        RECT 9.790 13.480 10.010 13.720 ;
        RECT 13.470 13.550 13.690 13.720 ;
        RECT 16.565 13.705 19.305 14.385 ;
        RECT 21.625 13.705 23.455 14.385 ;
        RECT 23.670 13.705 24.600 14.615 ;
        RECT 26.430 13.705 27.360 14.615 ;
        RECT 29.425 14.385 30.840 14.615 ;
        RECT 28.065 13.705 30.840 14.385 ;
        RECT 31.285 13.705 33.115 14.615 ;
        RECT 15.335 13.550 15.495 13.660 ;
        RECT 13.515 13.540 13.625 13.550 ;
        RECT 16.705 13.515 16.875 13.705 ;
        RECT 17.195 13.540 17.305 13.660 ;
        RECT 19.005 13.495 19.175 13.685 ;
        RECT 19.495 13.540 19.605 13.660 ;
        RECT 21.300 13.545 21.420 13.655 ;
        RECT 21.765 13.515 21.935 13.705 ;
        RECT 23.670 13.685 23.775 13.705 ;
        RECT 26.430 13.685 26.535 13.705 ;
        RECT 23.605 13.515 23.775 13.685 ;
        RECT 24.995 13.550 25.155 13.660 ;
        RECT 25.900 13.545 26.020 13.655 ;
        RECT 26.365 13.515 26.535 13.685 ;
        RECT 27.740 13.545 27.860 13.655 ;
        RECT 28.200 13.515 28.370 13.705 ;
        RECT 28.660 13.495 28.830 13.685 ;
        RECT 30.500 13.495 30.670 13.685 ;
        RECT 31.430 13.515 31.600 13.705 ;
        RECT 32.805 13.495 32.975 13.685 ;
        RECT 33.260 13.545 33.380 13.655 ;
        RECT 18.865 12.815 28.510 13.495 ;
        RECT 20.225 12.595 21.145 12.815 ;
        RECT 25.810 12.695 28.510 12.815 ;
        RECT 26.740 12.585 28.510 12.695 ;
        RECT 28.545 12.585 29.895 13.495 ;
        RECT 30.385 12.585 31.735 13.495 ;
        RECT 31.745 12.715 33.115 13.495 ;
        RECT 22.985 8.945 23.905 9.165 ;
        RECT 29.985 9.065 30.905 9.175 ;
        RECT 28.570 8.945 30.905 9.065 ;
        RECT 2.430 8.040 2.650 8.280 ;
        RECT 18.865 8.265 21.605 8.945 ;
        RECT 21.625 8.265 30.905 8.945 ;
        RECT 31.490 8.265 32.420 9.175 ;
        RECT 6.155 8.210 6.265 8.220 ;
        RECT 6.110 8.040 6.330 8.210 ;
        RECT 7.975 8.100 8.135 8.210 ;
        RECT 8.885 8.055 9.055 8.245 ;
        RECT 9.790 8.055 10.010 8.210 ;
        RECT 13.515 8.100 13.625 8.220 ;
        RECT 15.335 8.110 15.495 8.220 ;
        RECT 16.735 8.100 16.845 8.220 ;
        RECT 18.545 8.215 18.715 8.245 ;
        RECT 18.540 8.105 18.715 8.215 ;
        RECT 18.545 8.055 18.715 8.105 ;
        RECT 19.005 8.075 19.175 8.265 ;
        RECT 21.765 8.075 21.935 8.265 ;
        RECT 31.490 8.245 31.595 8.265 ;
        RECT 28.235 8.100 28.345 8.220 ;
        RECT 30.505 8.075 30.675 8.245 ;
        RECT 31.425 8.075 31.595 8.245 ;
        RECT 30.570 8.055 30.675 8.075 ;
        RECT 31.880 8.055 32.050 8.245 ;
        RECT 32.815 8.110 32.975 8.220 ;
        RECT 33.260 8.105 33.380 8.215 ;
        RECT 8.745 7.375 18.025 8.055 ;
        RECT 18.405 7.375 27.685 8.055 ;
        RECT 10.105 7.155 11.025 7.375 ;
        RECT 15.690 7.255 18.025 7.375 ;
        RECT 17.105 7.145 18.025 7.255 ;
        RECT 19.765 7.155 20.685 7.375 ;
        RECT 25.350 7.255 27.685 7.375 ;
        RECT 26.765 7.145 27.685 7.255 ;
        RECT 30.570 7.145 31.500 8.055 ;
        RECT 31.765 7.145 33.115 8.055 ;
        RECT 7.805 3.505 8.725 3.725 ;
        RECT 14.805 3.625 15.725 3.735 ;
        RECT 13.390 3.505 15.725 3.625 ;
        RECT 17.925 3.505 18.845 3.725 ;
        RECT 24.925 3.625 25.845 3.735 ;
        RECT 23.510 3.505 25.845 3.625 ;
        RECT 6.445 2.825 15.725 3.505 ;
        RECT 16.565 2.825 25.845 3.505 ;
        RECT 2.430 2.600 2.650 2.770 ;
        RECT 6.120 2.665 6.240 2.775 ;
        RECT 6.585 2.635 6.755 2.825 ;
        RECT 16.705 2.635 16.875 2.825 ;
        RECT 26.350 2.600 26.570 2.770 ;
        RECT 30.535 2.660 30.645 2.780 ;
        RECT 32.355 2.670 32.515 2.780 ;
        RECT 33.260 2.665 33.380 2.775 ;
      LAYER li1 ;
        RECT 17.095 36.845 17.425 37.825 ;
        RECT 18.485 37.025 18.755 37.795 ;
        RECT 19.460 37.390 19.645 37.795 ;
        RECT 19.460 37.215 20.125 37.390 ;
        RECT 18.485 36.855 19.615 37.025 ;
        RECT 16.655 36.415 16.990 36.685 ;
        RECT 17.160 36.245 17.330 36.845 ;
        RECT 17.500 36.435 17.835 36.685 ;
        RECT 17.160 35.615 17.855 36.245 ;
        RECT 18.485 35.945 18.655 36.855 ;
        RECT 19.365 36.355 19.615 36.855 ;
        RECT 19.785 36.185 20.125 37.215 ;
        RECT 20.960 36.845 21.290 37.825 ;
        RECT 22.615 36.845 22.945 37.825 ;
        RECT 24.455 36.845 24.785 37.825 ;
        RECT 26.020 36.845 26.350 37.825 ;
        RECT 27.400 36.845 27.730 37.825 ;
        RECT 20.560 36.435 20.890 36.675 ;
        RECT 21.060 36.245 21.290 36.845 ;
        RECT 22.175 36.415 22.510 36.685 ;
        RECT 19.440 36.015 20.125 36.185 ;
        RECT 18.485 35.615 18.745 35.945 ;
        RECT 19.440 35.615 19.645 36.015 ;
        RECT 20.960 35.615 21.290 36.245 ;
        RECT 22.680 36.245 22.850 36.845 ;
        RECT 23.020 36.435 23.355 36.685 ;
        RECT 24.015 36.415 24.350 36.685 ;
        RECT 24.520 36.245 24.690 36.845 ;
        RECT 24.860 36.435 25.195 36.685 ;
        RECT 25.620 36.435 25.950 36.675 ;
        RECT 26.120 36.245 26.350 36.845 ;
        RECT 27.000 36.435 27.330 36.675 ;
        RECT 27.500 36.245 27.730 36.845 ;
        RECT 28.575 37.025 28.905 37.825 ;
        RECT 29.475 37.025 29.805 37.825 ;
        RECT 28.575 36.855 29.805 37.025 ;
        RECT 30.455 37.025 30.785 37.810 ;
        RECT 30.455 36.855 31.135 37.025 ;
        RECT 22.680 35.615 23.375 36.245 ;
        RECT 24.520 35.615 25.215 36.245 ;
        RECT 26.020 35.615 26.350 36.245 ;
        RECT 27.400 35.615 27.730 36.245 ;
        RECT 28.170 36.105 28.390 36.685 ;
        RECT 28.575 35.955 28.755 36.855 ;
        RECT 28.925 36.125 29.300 36.685 ;
        RECT 29.505 36.355 29.815 36.685 ;
        RECT 30.445 36.435 30.795 36.685 ;
        RECT 30.965 36.255 31.135 36.855 ;
        RECT 32.275 36.845 32.605 37.825 ;
        RECT 31.305 36.435 31.655 36.685 ;
        RECT 31.835 36.415 32.170 36.685 ;
        RECT 29.475 35.955 29.805 36.185 ;
        RECT 28.575 35.615 29.805 35.955 ;
        RECT 30.875 35.615 31.205 36.255 ;
        RECT 32.340 36.245 32.510 36.845 ;
        RECT 32.680 36.435 33.015 36.685 ;
        RECT 32.340 35.615 33.035 36.245 ;
        RECT 16.360 34.475 16.690 35.105 ;
        RECT 17.740 34.475 18.070 35.105 ;
        RECT 15.960 34.045 16.290 34.285 ;
        RECT 16.460 33.875 16.690 34.475 ;
        RECT 17.340 34.045 17.670 34.285 ;
        RECT 17.840 33.875 18.070 34.475 ;
        RECT 20.295 34.625 20.625 35.100 ;
        RECT 21.135 34.625 21.465 35.100 ;
        RECT 21.975 34.625 22.305 35.100 ;
        RECT 20.295 34.455 22.645 34.625 ;
        RECT 22.470 34.285 22.645 34.455 ;
        RECT 30.960 34.475 31.655 35.105 ;
        RECT 30.960 34.425 31.135 34.475 ;
        RECT 19.865 34.085 22.265 34.285 ;
        RECT 22.470 34.085 29.190 34.285 ;
        RECT 22.470 33.915 22.645 34.085 ;
        RECT 30.455 34.035 30.790 34.305 ;
        RECT 16.360 32.895 16.690 33.875 ;
        RECT 17.740 32.895 18.070 33.875 ;
        RECT 20.295 33.745 22.645 33.915 ;
        RECT 30.960 33.875 31.130 34.425 ;
        RECT 31.300 34.035 31.635 34.285 ;
        RECT 20.295 32.895 20.625 33.745 ;
        RECT 21.135 32.895 21.465 33.745 ;
        RECT 21.975 32.895 22.305 33.745 ;
        RECT 30.895 32.895 31.225 33.875 ;
        RECT 18.200 31.405 18.530 32.385 ;
        RECT 19.395 31.405 19.725 32.385 ;
        RECT 21.675 31.585 22.005 32.385 ;
        RECT 22.575 31.585 22.905 32.385 ;
        RECT 21.675 31.415 22.905 31.585 ;
        RECT 23.975 31.535 24.305 32.385 ;
        RECT 24.815 31.535 25.145 32.385 ;
        RECT 25.655 31.535 25.985 32.385 ;
        RECT 17.800 30.995 18.130 31.235 ;
        RECT 18.300 30.805 18.530 31.405 ;
        RECT 19.460 31.365 19.635 31.405 ;
        RECT 18.955 30.975 19.290 31.245 ;
        RECT 18.200 30.175 18.530 30.805 ;
        RECT 19.460 30.805 19.630 31.365 ;
        RECT 19.800 30.995 20.135 31.245 ;
        RECT 19.460 30.175 20.155 30.805 ;
        RECT 21.270 30.665 21.490 31.245 ;
        RECT 21.675 30.515 21.855 31.415 ;
        RECT 23.975 31.365 26.325 31.535 ;
        RECT 22.025 30.685 22.400 31.245 ;
        RECT 22.605 30.915 22.915 31.245 ;
        RECT 26.150 31.195 26.325 31.365 ;
        RECT 23.545 30.995 25.945 31.195 ;
        RECT 26.150 30.995 32.870 31.195 ;
        RECT 26.150 30.825 26.325 30.995 ;
        RECT 22.575 30.515 22.905 30.745 ;
        RECT 21.675 30.175 22.905 30.515 ;
        RECT 23.975 30.655 26.325 30.825 ;
        RECT 23.975 30.180 24.305 30.655 ;
        RECT 24.815 30.180 25.145 30.655 ;
        RECT 25.655 30.180 25.985 30.655 ;
        RECT 15.725 29.335 16.025 29.665 ;
        RECT 15.725 28.425 15.895 29.335 ;
        RECT 16.650 29.185 16.945 29.575 ;
        RECT 17.545 29.185 17.805 29.575 ;
        RECT 16.065 28.595 16.415 29.165 ;
        RECT 16.650 29.015 18.300 29.185 ;
        RECT 18.925 29.035 19.255 29.665 ;
        RECT 16.585 28.675 17.725 28.845 ;
        RECT 16.585 28.425 16.755 28.675 ;
        RECT 17.895 28.505 18.300 29.015 ;
        RECT 18.505 28.595 18.835 28.845 ;
        RECT 15.725 28.255 16.755 28.425 ;
        RECT 17.545 28.335 18.300 28.505 ;
        RECT 19.005 28.435 19.255 29.035 ;
        RECT 20.295 29.185 20.625 29.660 ;
        RECT 21.135 29.185 21.465 29.660 ;
        RECT 21.975 29.185 22.305 29.660 ;
        RECT 30.445 29.205 30.785 29.665 ;
        RECT 31.295 29.455 32.465 29.665 ;
        RECT 31.295 29.205 31.545 29.455 ;
        RECT 32.135 29.435 32.465 29.455 ;
        RECT 20.295 29.015 22.645 29.185 ;
        RECT 30.445 29.035 31.545 29.205 ;
        RECT 31.715 29.015 32.575 29.265 ;
        RECT 22.470 28.845 22.645 29.015 ;
        RECT 19.865 28.645 22.265 28.845 ;
        RECT 22.470 28.645 29.190 28.845 ;
        RECT 22.470 28.475 22.645 28.645 ;
        RECT 30.445 28.595 31.205 28.845 ;
        RECT 31.375 28.595 32.125 28.845 ;
        RECT 15.725 27.455 16.035 28.255 ;
        RECT 17.545 28.085 17.805 28.335 ;
        RECT 16.685 27.915 17.805 28.085 ;
        RECT 16.685 27.455 16.945 27.915 ;
        RECT 17.545 27.455 17.805 27.915 ;
        RECT 18.925 27.455 19.255 28.435 ;
        RECT 20.295 28.305 22.645 28.475 ;
        RECT 32.295 28.425 32.575 29.015 ;
        RECT 20.295 27.455 20.625 28.305 ;
        RECT 21.135 27.455 21.465 28.305 ;
        RECT 21.975 27.455 22.305 28.305 ;
        RECT 30.875 28.255 32.575 28.425 ;
        RECT 30.875 27.455 31.205 28.255 ;
        RECT 31.715 27.455 32.045 28.255 ;
        RECT 6.615 26.445 6.785 26.945 ;
        RECT 6.615 26.275 7.280 26.445 ;
        RECT 6.530 25.455 6.880 26.105 ;
        RECT 7.050 25.285 7.280 26.275 ;
        RECT 6.615 25.115 7.280 25.285 ;
        RECT 6.615 24.825 6.785 25.115 ;
        RECT 7.455 24.825 7.680 26.945 ;
        RECT 8.395 26.445 8.565 26.945 ;
        RECT 8.800 26.730 9.630 26.900 ;
        RECT 7.870 26.275 8.565 26.445 ;
        RECT 7.870 25.305 8.040 26.275 ;
        RECT 8.210 25.485 8.620 26.105 ;
        RECT 8.790 26.055 9.290 26.435 ;
        RECT 7.870 25.115 8.565 25.305 ;
        RECT 8.790 25.185 9.010 26.055 ;
        RECT 9.460 25.885 9.630 26.730 ;
        RECT 10.430 26.565 10.600 26.855 ;
        RECT 11.570 26.645 12.200 26.895 ;
        RECT 12.030 26.565 12.200 26.645 ;
        RECT 13.000 26.565 13.240 26.855 ;
        RECT 9.800 26.315 11.170 26.565 ;
        RECT 9.800 26.055 10.050 26.315 ;
        RECT 10.560 25.885 10.810 26.045 ;
        RECT 9.460 25.715 10.810 25.885 ;
        RECT 9.460 25.675 9.880 25.715 ;
        RECT 9.190 25.125 9.540 25.495 ;
        RECT 8.395 24.785 8.565 25.115 ;
        RECT 9.710 24.945 9.880 25.675 ;
        RECT 10.980 25.545 11.170 26.315 ;
        RECT 10.050 25.215 10.460 25.545 ;
        RECT 8.865 24.745 9.880 24.945 ;
        RECT 10.750 25.205 11.170 25.545 ;
        RECT 11.340 26.135 11.860 26.445 ;
        RECT 12.030 26.395 13.240 26.565 ;
        RECT 11.340 25.375 11.510 26.135 ;
        RECT 11.680 25.545 11.860 25.955 ;
        RECT 12.030 25.885 12.200 26.395 ;
        RECT 13.970 26.245 14.140 26.855 ;
        RECT 14.410 26.395 14.740 26.905 ;
        RECT 13.970 26.225 14.290 26.245 ;
        RECT 12.370 26.055 14.290 26.225 ;
        RECT 12.030 25.715 13.930 25.885 ;
        RECT 12.260 25.375 12.590 25.495 ;
        RECT 11.340 25.205 12.590 25.375 ;
        RECT 10.750 24.775 11.000 25.205 ;
        RECT 12.760 24.955 12.930 25.715 ;
        RECT 13.600 25.655 13.930 25.715 ;
        RECT 13.120 25.485 13.450 25.545 ;
        RECT 13.120 25.215 13.780 25.485 ;
        RECT 14.100 25.160 14.290 26.055 ;
        RECT 12.080 24.785 12.930 24.955 ;
        RECT 13.970 24.830 14.290 25.160 ;
        RECT 14.490 25.805 14.740 26.395 ;
        RECT 15.385 26.135 15.640 26.805 ;
        RECT 14.490 25.475 15.290 25.805 ;
        RECT 14.490 24.825 14.740 25.475 ;
        RECT 15.460 25.275 15.640 26.135 ;
        RECT 23.975 26.095 24.305 26.945 ;
        RECT 24.815 26.095 25.145 26.945 ;
        RECT 25.655 26.095 25.985 26.945 ;
        RECT 23.975 25.925 26.325 26.095 ;
        RECT 26.150 25.755 26.325 25.925 ;
        RECT 23.545 25.555 25.945 25.755 ;
        RECT 26.150 25.555 32.870 25.755 ;
        RECT 26.150 25.385 26.325 25.555 ;
        RECT 15.385 25.075 15.640 25.275 ;
        RECT 23.975 25.215 26.325 25.385 ;
        RECT 15.385 24.905 15.725 25.075 ;
        RECT 15.385 24.745 15.640 24.905 ;
        RECT 23.975 24.740 24.305 25.215 ;
        RECT 24.815 24.740 25.145 25.215 ;
        RECT 25.655 24.740 25.985 25.215 ;
        RECT 10.755 23.845 10.925 24.135 ;
        RECT 10.755 23.675 11.420 23.845 ;
        RECT 10.670 22.855 11.020 23.505 ;
        RECT 11.190 22.685 11.420 23.675 ;
        RECT 10.755 22.515 11.420 22.685 ;
        RECT 10.755 22.015 10.925 22.515 ;
        RECT 11.595 22.015 11.820 24.135 ;
        RECT 12.535 23.845 12.705 24.175 ;
        RECT 13.005 24.015 14.020 24.215 ;
        RECT 12.010 23.655 12.705 23.845 ;
        RECT 12.010 22.685 12.180 23.655 ;
        RECT 12.350 22.855 12.760 23.475 ;
        RECT 12.930 22.905 13.150 23.775 ;
        RECT 13.330 23.465 13.680 23.835 ;
        RECT 13.850 23.285 14.020 24.015 ;
        RECT 14.890 23.755 15.140 24.185 ;
        RECT 16.220 24.005 17.070 24.175 ;
        RECT 14.190 23.415 14.600 23.745 ;
        RECT 14.890 23.415 15.310 23.755 ;
        RECT 13.600 23.245 14.020 23.285 ;
        RECT 13.600 23.075 14.950 23.245 ;
        RECT 12.010 22.515 12.705 22.685 ;
        RECT 12.930 22.525 13.430 22.905 ;
        RECT 12.535 22.015 12.705 22.515 ;
        RECT 13.600 22.230 13.770 23.075 ;
        RECT 14.700 22.915 14.950 23.075 ;
        RECT 13.940 22.645 14.190 22.905 ;
        RECT 15.120 22.645 15.310 23.415 ;
        RECT 13.940 22.395 15.310 22.645 ;
        RECT 15.480 23.585 16.730 23.755 ;
        RECT 15.480 22.825 15.650 23.585 ;
        RECT 16.400 23.465 16.730 23.585 ;
        RECT 15.820 23.005 16.000 23.415 ;
        RECT 16.900 23.245 17.070 24.005 ;
        RECT 18.110 23.800 18.430 24.130 ;
        RECT 17.260 23.475 17.920 23.745 ;
        RECT 17.260 23.415 17.590 23.475 ;
        RECT 17.740 23.245 18.070 23.305 ;
        RECT 16.170 23.075 18.070 23.245 ;
        RECT 15.480 22.515 16.000 22.825 ;
        RECT 16.170 22.565 16.340 23.075 ;
        RECT 18.240 22.905 18.430 23.800 ;
        RECT 16.510 22.735 18.430 22.905 ;
        RECT 18.110 22.715 18.430 22.735 ;
        RECT 18.630 23.485 18.880 24.135 ;
        RECT 19.525 24.055 19.780 24.215 ;
        RECT 19.525 23.885 19.865 24.055 ;
        RECT 19.525 23.685 19.780 23.885 ;
        RECT 18.630 23.155 19.430 23.485 ;
        RECT 16.170 22.395 17.380 22.565 ;
        RECT 12.940 22.060 13.770 22.230 ;
        RECT 14.570 22.105 14.740 22.395 ;
        RECT 16.170 22.315 16.340 22.395 ;
        RECT 15.710 22.065 16.340 22.315 ;
        RECT 17.140 22.105 17.380 22.395 ;
        RECT 18.110 22.105 18.280 22.715 ;
        RECT 18.630 22.565 18.880 23.155 ;
        RECT 19.600 22.825 19.780 23.685 ;
        RECT 20.415 23.845 20.585 24.135 ;
        RECT 20.415 23.675 21.080 23.845 ;
        RECT 20.330 22.855 20.680 23.505 ;
        RECT 18.550 22.055 18.880 22.565 ;
        RECT 19.525 22.155 19.780 22.825 ;
        RECT 20.850 22.685 21.080 23.675 ;
        RECT 20.415 22.515 21.080 22.685 ;
        RECT 20.415 22.015 20.585 22.515 ;
        RECT 21.255 22.015 21.480 24.135 ;
        RECT 22.195 23.845 22.365 24.175 ;
        RECT 22.665 24.015 23.680 24.215 ;
        RECT 21.670 23.655 22.365 23.845 ;
        RECT 21.670 22.685 21.840 23.655 ;
        RECT 22.010 22.855 22.420 23.475 ;
        RECT 22.590 22.905 22.810 23.775 ;
        RECT 22.990 23.465 23.340 23.835 ;
        RECT 23.510 23.285 23.680 24.015 ;
        RECT 24.550 23.755 24.800 24.185 ;
        RECT 25.880 24.005 26.730 24.175 ;
        RECT 23.850 23.415 24.260 23.745 ;
        RECT 24.550 23.415 24.970 23.755 ;
        RECT 23.260 23.245 23.680 23.285 ;
        RECT 23.260 23.075 24.610 23.245 ;
        RECT 21.670 22.515 22.365 22.685 ;
        RECT 22.590 22.525 23.090 22.905 ;
        RECT 22.195 22.015 22.365 22.515 ;
        RECT 23.260 22.230 23.430 23.075 ;
        RECT 24.360 22.915 24.610 23.075 ;
        RECT 23.600 22.645 23.850 22.905 ;
        RECT 24.780 22.645 24.970 23.415 ;
        RECT 23.600 22.395 24.970 22.645 ;
        RECT 25.140 23.585 26.390 23.755 ;
        RECT 25.140 22.825 25.310 23.585 ;
        RECT 26.060 23.465 26.390 23.585 ;
        RECT 25.480 23.005 25.660 23.415 ;
        RECT 26.560 23.245 26.730 24.005 ;
        RECT 27.770 23.800 28.090 24.130 ;
        RECT 26.920 23.475 27.580 23.745 ;
        RECT 26.920 23.415 27.250 23.475 ;
        RECT 27.400 23.245 27.730 23.305 ;
        RECT 25.830 23.075 27.730 23.245 ;
        RECT 25.140 22.515 25.660 22.825 ;
        RECT 25.830 22.565 26.000 23.075 ;
        RECT 27.900 22.905 28.090 23.800 ;
        RECT 26.170 22.735 28.090 22.905 ;
        RECT 27.770 22.715 28.090 22.735 ;
        RECT 28.290 23.485 28.540 24.135 ;
        RECT 29.185 24.055 29.440 24.215 ;
        RECT 29.185 23.885 29.525 24.055 ;
        RECT 29.185 23.685 29.440 23.885 ;
        RECT 28.290 23.155 29.090 23.485 ;
        RECT 25.830 22.395 27.040 22.565 ;
        RECT 22.600 22.060 23.430 22.230 ;
        RECT 24.230 22.105 24.400 22.395 ;
        RECT 25.830 22.315 26.000 22.395 ;
        RECT 25.370 22.065 26.000 22.315 ;
        RECT 26.800 22.105 27.040 22.395 ;
        RECT 27.770 22.105 27.940 22.715 ;
        RECT 28.290 22.565 28.540 23.155 ;
        RECT 29.260 22.825 29.440 23.685 ;
        RECT 31.080 23.595 31.410 24.225 ;
        RECT 32.460 23.595 32.790 24.225 ;
        RECT 30.680 23.165 31.010 23.405 ;
        RECT 31.180 22.995 31.410 23.595 ;
        RECT 32.060 23.165 32.390 23.405 ;
        RECT 32.560 22.995 32.790 23.595 ;
        RECT 28.210 22.055 28.540 22.565 ;
        RECT 29.185 22.155 29.440 22.825 ;
        RECT 31.080 22.015 31.410 22.995 ;
        RECT 32.460 22.015 32.790 22.995 ;
        RECT 6.155 21.005 6.325 21.505 ;
        RECT 6.155 20.835 6.820 21.005 ;
        RECT 6.070 20.015 6.420 20.665 ;
        RECT 6.590 19.845 6.820 20.835 ;
        RECT 6.155 19.675 6.820 19.845 ;
        RECT 6.155 19.385 6.325 19.675 ;
        RECT 6.995 19.385 7.220 21.505 ;
        RECT 7.935 21.005 8.105 21.505 ;
        RECT 8.340 21.290 9.170 21.460 ;
        RECT 7.410 20.835 8.105 21.005 ;
        RECT 7.410 19.865 7.580 20.835 ;
        RECT 7.750 20.045 8.160 20.665 ;
        RECT 8.330 20.615 8.830 20.995 ;
        RECT 7.410 19.675 8.105 19.865 ;
        RECT 8.330 19.745 8.550 20.615 ;
        RECT 9.000 20.445 9.170 21.290 ;
        RECT 9.970 21.125 10.140 21.415 ;
        RECT 11.110 21.205 11.740 21.455 ;
        RECT 11.570 21.125 11.740 21.205 ;
        RECT 12.540 21.125 12.780 21.415 ;
        RECT 9.340 20.875 10.710 21.125 ;
        RECT 9.340 20.615 9.590 20.875 ;
        RECT 10.100 20.445 10.350 20.605 ;
        RECT 9.000 20.275 10.350 20.445 ;
        RECT 9.000 20.235 9.420 20.275 ;
        RECT 8.730 19.685 9.080 20.055 ;
        RECT 7.935 19.345 8.105 19.675 ;
        RECT 9.250 19.505 9.420 20.235 ;
        RECT 10.520 20.105 10.710 20.875 ;
        RECT 9.590 19.775 10.000 20.105 ;
        RECT 8.405 19.305 9.420 19.505 ;
        RECT 10.290 19.765 10.710 20.105 ;
        RECT 10.880 20.695 11.400 21.005 ;
        RECT 11.570 20.955 12.780 21.125 ;
        RECT 10.880 19.935 11.050 20.695 ;
        RECT 11.220 20.105 11.400 20.515 ;
        RECT 11.570 20.445 11.740 20.955 ;
        RECT 13.510 20.805 13.680 21.415 ;
        RECT 13.950 20.955 14.280 21.465 ;
        RECT 13.510 20.785 13.830 20.805 ;
        RECT 11.910 20.615 13.830 20.785 ;
        RECT 11.570 20.275 13.470 20.445 ;
        RECT 11.800 19.935 12.130 20.055 ;
        RECT 10.880 19.765 12.130 19.935 ;
        RECT 10.290 19.335 10.540 19.765 ;
        RECT 12.300 19.515 12.470 20.275 ;
        RECT 13.140 20.215 13.470 20.275 ;
        RECT 12.660 20.045 12.990 20.105 ;
        RECT 12.660 19.775 13.320 20.045 ;
        RECT 13.640 19.720 13.830 20.615 ;
        RECT 11.620 19.345 12.470 19.515 ;
        RECT 13.510 19.390 13.830 19.720 ;
        RECT 14.030 20.365 14.280 20.955 ;
        RECT 14.925 20.695 15.180 21.365 ;
        RECT 17.195 21.005 17.365 21.505 ;
        RECT 17.195 20.835 17.860 21.005 ;
        RECT 14.030 20.035 14.830 20.365 ;
        RECT 15.000 20.315 15.180 20.695 ;
        RECT 15.000 20.145 15.265 20.315 ;
        RECT 14.030 19.385 14.280 20.035 ;
        RECT 15.000 19.835 15.180 20.145 ;
        RECT 17.110 20.015 17.460 20.665 ;
        RECT 17.630 19.845 17.860 20.835 ;
        RECT 14.925 19.305 15.180 19.835 ;
        RECT 17.195 19.675 17.860 19.845 ;
        RECT 17.195 19.385 17.365 19.675 ;
        RECT 18.035 19.385 18.260 21.505 ;
        RECT 18.975 21.005 19.145 21.505 ;
        RECT 19.380 21.290 20.210 21.460 ;
        RECT 18.450 20.835 19.145 21.005 ;
        RECT 18.450 19.865 18.620 20.835 ;
        RECT 18.790 20.045 19.200 20.665 ;
        RECT 19.370 20.615 19.870 20.995 ;
        RECT 18.450 19.675 19.145 19.865 ;
        RECT 19.370 19.745 19.590 20.615 ;
        RECT 20.040 20.445 20.210 21.290 ;
        RECT 21.010 21.125 21.180 21.415 ;
        RECT 22.150 21.205 22.780 21.455 ;
        RECT 22.610 21.125 22.780 21.205 ;
        RECT 23.580 21.125 23.820 21.415 ;
        RECT 20.380 20.875 21.750 21.125 ;
        RECT 20.380 20.615 20.630 20.875 ;
        RECT 21.140 20.445 21.390 20.605 ;
        RECT 20.040 20.275 21.390 20.445 ;
        RECT 20.040 20.235 20.460 20.275 ;
        RECT 19.770 19.685 20.120 20.055 ;
        RECT 18.975 19.345 19.145 19.675 ;
        RECT 20.290 19.505 20.460 20.235 ;
        RECT 21.560 20.105 21.750 20.875 ;
        RECT 20.630 19.775 21.040 20.105 ;
        RECT 19.445 19.305 20.460 19.505 ;
        RECT 21.330 19.765 21.750 20.105 ;
        RECT 21.920 20.695 22.440 21.005 ;
        RECT 22.610 20.955 23.820 21.125 ;
        RECT 21.920 19.935 22.090 20.695 ;
        RECT 22.260 20.105 22.440 20.515 ;
        RECT 22.610 20.445 22.780 20.955 ;
        RECT 24.550 20.805 24.720 21.415 ;
        RECT 24.990 20.955 25.320 21.465 ;
        RECT 24.550 20.785 24.870 20.805 ;
        RECT 22.950 20.615 24.870 20.785 ;
        RECT 22.610 20.275 24.510 20.445 ;
        RECT 22.840 19.935 23.170 20.055 ;
        RECT 21.920 19.765 23.170 19.935 ;
        RECT 21.330 19.335 21.580 19.765 ;
        RECT 23.340 19.515 23.510 20.275 ;
        RECT 24.180 20.215 24.510 20.275 ;
        RECT 23.700 20.045 24.030 20.105 ;
        RECT 23.700 19.775 24.360 20.045 ;
        RECT 24.680 19.720 24.870 20.615 ;
        RECT 22.660 19.345 23.510 19.515 ;
        RECT 24.550 19.390 24.870 19.720 ;
        RECT 25.070 20.365 25.320 20.955 ;
        RECT 25.965 20.695 26.220 21.365 ;
        RECT 25.070 20.035 25.870 20.365 ;
        RECT 25.070 19.385 25.320 20.035 ;
        RECT 26.040 19.835 26.220 20.695 ;
        RECT 29.055 20.525 29.385 21.505 ;
        RECT 28.615 20.095 28.950 20.365 ;
        RECT 25.965 19.635 26.220 19.835 ;
        RECT 29.120 19.925 29.290 20.525 ;
        RECT 29.460 20.115 29.795 20.365 ;
        RECT 25.965 19.465 26.305 19.635 ;
        RECT 25.965 19.305 26.220 19.465 ;
        RECT 29.120 19.295 29.815 19.925 ;
        RECT 20.380 18.155 21.075 18.785 ;
        RECT 21.760 18.155 22.455 18.785 ;
        RECT 23.140 18.155 23.835 18.785 ;
        RECT 24.640 18.155 24.970 18.785 ;
        RECT 26.765 18.325 27.105 18.785 ;
        RECT 27.615 18.575 28.785 18.785 ;
        RECT 27.615 18.325 27.865 18.575 ;
        RECT 28.455 18.555 28.785 18.575 ;
        RECT 30.905 18.455 31.205 18.785 ;
        RECT 26.765 18.155 27.865 18.325 ;
        RECT 19.875 17.715 20.210 17.985 ;
        RECT 20.380 17.555 20.550 18.155 ;
        RECT 20.720 17.715 21.055 17.965 ;
        RECT 21.255 17.715 21.590 17.985 ;
        RECT 21.760 17.555 21.930 18.155 ;
        RECT 22.100 17.715 22.435 17.965 ;
        RECT 22.635 17.715 22.970 17.985 ;
        RECT 23.140 17.555 23.310 18.155 ;
        RECT 23.480 17.715 23.815 17.965 ;
        RECT 24.240 17.725 24.570 17.965 ;
        RECT 24.740 17.555 24.970 18.155 ;
        RECT 28.035 18.135 28.895 18.385 ;
        RECT 26.765 17.715 27.525 17.965 ;
        RECT 27.695 17.715 28.445 17.965 ;
        RECT 20.315 16.575 20.645 17.555 ;
        RECT 21.695 16.575 22.025 17.555 ;
        RECT 23.075 16.575 23.405 17.555 ;
        RECT 24.640 16.575 24.970 17.555 ;
        RECT 28.615 17.545 28.895 18.135 ;
        RECT 27.195 17.375 28.895 17.545 ;
        RECT 30.905 17.545 31.075 18.455 ;
        RECT 31.830 18.305 32.125 18.695 ;
        RECT 32.725 18.305 32.985 18.695 ;
        RECT 31.830 18.135 33.480 18.305 ;
        RECT 31.765 17.795 32.905 17.965 ;
        RECT 31.765 17.545 31.935 17.795 ;
        RECT 33.075 17.625 33.480 18.135 ;
        RECT 30.905 17.375 31.935 17.545 ;
        RECT 32.725 17.455 33.480 17.625 ;
        RECT 27.195 16.575 27.525 17.375 ;
        RECT 28.035 16.575 28.365 17.375 ;
        RECT 30.905 16.575 31.215 17.375 ;
        RECT 32.725 17.205 32.985 17.455 ;
        RECT 31.865 17.035 32.985 17.205 ;
        RECT 31.865 16.575 32.125 17.035 ;
        RECT 32.725 16.575 32.985 17.035 ;
        RECT 16.645 15.265 16.955 16.065 ;
        RECT 17.605 15.605 17.865 16.065 ;
        RECT 18.465 15.605 18.725 16.065 ;
        RECT 17.605 15.435 18.725 15.605 ;
        RECT 16.645 15.095 17.675 15.265 ;
        RECT 16.645 14.185 16.815 15.095 ;
        RECT 17.505 14.845 17.675 15.095 ;
        RECT 18.465 15.185 18.725 15.435 ;
        RECT 21.795 15.305 21.965 16.065 ;
        RECT 18.465 15.015 19.220 15.185 ;
        RECT 21.795 15.135 22.510 15.305 ;
        RECT 22.680 15.160 22.935 16.065 ;
        RECT 17.505 14.675 18.645 14.845 ;
        RECT 18.815 14.505 19.220 15.015 ;
        RECT 21.705 14.585 22.060 14.955 ;
        RECT 22.340 14.925 22.510 15.135 ;
        RECT 22.340 14.595 22.595 14.925 ;
        RECT 17.570 14.335 19.220 14.505 ;
        RECT 22.340 14.405 22.510 14.595 ;
        RECT 22.765 14.430 22.935 15.160 ;
        RECT 24.180 15.085 24.510 16.065 ;
        RECT 26.940 15.085 27.270 16.065 ;
        RECT 28.145 15.605 28.440 16.065 ;
        RECT 28.995 15.775 29.380 16.065 ;
        RECT 28.145 15.385 28.955 15.605 ;
        RECT 23.780 14.675 24.110 14.915 ;
        RECT 24.280 14.485 24.510 15.085 ;
        RECT 26.540 14.675 26.870 14.915 ;
        RECT 27.040 14.485 27.270 15.085 ;
        RECT 28.145 14.655 28.615 15.215 ;
        RECT 28.785 14.925 28.955 15.385 ;
        RECT 28.785 14.595 29.040 14.925 ;
        RECT 29.210 14.875 29.380 15.775 ;
        RECT 29.575 15.345 29.800 16.030 ;
        RECT 29.575 15.175 30.300 15.345 ;
        RECT 30.130 14.925 30.300 15.175 ;
        RECT 30.500 15.095 30.760 16.065 ;
        RECT 29.210 14.675 29.960 14.875 ;
        RECT 28.785 14.485 28.955 14.595 ;
        RECT 16.645 13.855 16.945 14.185 ;
        RECT 17.570 13.945 17.865 14.335 ;
        RECT 18.465 13.945 18.725 14.335 ;
        RECT 21.795 14.235 22.510 14.405 ;
        RECT 21.795 13.855 21.965 14.235 ;
        RECT 22.680 13.855 22.935 14.430 ;
        RECT 24.180 13.855 24.510 14.485 ;
        RECT 26.940 13.855 27.270 14.485 ;
        RECT 28.155 14.315 28.955 14.485 ;
        RECT 28.155 13.855 28.440 14.315 ;
        RECT 29.210 14.145 29.380 14.675 ;
        RECT 30.130 14.595 30.420 14.925 ;
        RECT 30.130 14.505 30.300 14.595 ;
        RECT 28.995 13.855 29.380 14.145 ;
        RECT 29.575 14.335 30.300 14.505 ;
        RECT 30.590 14.425 30.760 15.095 ;
        RECT 31.795 15.265 32.125 16.065 ;
        RECT 32.695 15.265 33.025 16.065 ;
        RECT 31.795 15.095 33.025 15.265 ;
        RECT 29.575 13.855 29.800 14.335 ;
        RECT 30.470 13.855 30.760 14.425 ;
        RECT 31.390 14.345 31.610 14.925 ;
        RECT 31.795 14.195 31.975 15.095 ;
        RECT 32.145 14.365 32.520 14.925 ;
        RECT 32.725 14.595 33.035 14.925 ;
        RECT 32.695 14.195 33.025 14.425 ;
        RECT 31.795 13.855 33.025 14.195 ;
        RECT 18.945 12.965 19.205 13.255 ;
        RECT 19.875 13.035 20.095 13.255 ;
        RECT 18.945 12.795 19.695 12.965 ;
        RECT 18.945 11.975 19.295 12.625 ;
        RECT 19.465 11.805 19.695 12.795 ;
        RECT 18.945 11.635 19.695 11.805 ;
        RECT 18.945 11.135 19.205 11.635 ;
        RECT 19.865 11.555 20.095 13.035 ;
        RECT 20.815 12.965 20.985 13.295 ;
        RECT 21.285 13.135 22.300 13.335 ;
        RECT 20.290 12.775 20.985 12.965 ;
        RECT 20.290 11.805 20.460 12.775 ;
        RECT 20.630 11.975 21.040 12.595 ;
        RECT 21.210 12.025 21.430 12.895 ;
        RECT 21.610 12.585 21.960 12.955 ;
        RECT 22.130 12.405 22.300 13.135 ;
        RECT 23.170 12.875 23.420 13.305 ;
        RECT 24.500 13.125 25.350 13.295 ;
        RECT 22.470 12.535 22.880 12.865 ;
        RECT 23.170 12.535 23.570 12.875 ;
        RECT 21.880 12.365 22.300 12.405 ;
        RECT 21.880 12.195 23.230 12.365 ;
        RECT 20.290 11.635 20.985 11.805 ;
        RECT 21.210 11.645 21.710 12.025 ;
        RECT 19.875 11.135 20.095 11.555 ;
        RECT 20.815 11.135 20.985 11.635 ;
        RECT 21.880 11.350 22.050 12.195 ;
        RECT 22.980 12.035 23.230 12.195 ;
        RECT 22.220 11.765 22.470 12.025 ;
        RECT 23.400 11.765 23.570 12.535 ;
        RECT 22.220 11.515 23.570 11.765 ;
        RECT 23.740 12.705 25.010 12.875 ;
        RECT 23.740 11.945 23.910 12.705 ;
        RECT 24.660 12.585 25.010 12.705 ;
        RECT 24.080 12.125 24.260 12.535 ;
        RECT 25.180 12.365 25.350 13.125 ;
        RECT 26.390 12.920 26.740 13.250 ;
        RECT 25.520 12.595 26.200 12.865 ;
        RECT 25.520 12.535 25.870 12.595 ;
        RECT 26.000 12.365 26.350 12.425 ;
        RECT 24.430 12.195 26.350 12.365 ;
        RECT 23.740 11.635 24.260 11.945 ;
        RECT 24.430 11.685 24.600 12.195 ;
        RECT 26.550 12.025 26.740 12.920 ;
        RECT 24.770 11.855 26.740 12.025 ;
        RECT 26.370 11.835 26.740 11.855 ;
        RECT 26.910 12.605 27.080 13.255 ;
        RECT 27.750 12.835 27.995 13.335 ;
        RECT 27.750 12.775 28.435 12.835 ;
        RECT 27.835 12.745 28.435 12.775 ;
        RECT 27.850 12.705 28.435 12.745 ;
        RECT 26.910 12.275 27.710 12.605 ;
        RECT 24.430 11.515 25.640 11.685 ;
        RECT 21.220 11.180 22.050 11.350 ;
        RECT 22.850 11.225 23.020 11.515 ;
        RECT 24.430 11.435 24.600 11.515 ;
        RECT 23.970 11.185 24.600 11.435 ;
        RECT 25.400 11.225 25.640 11.515 ;
        RECT 26.370 11.225 26.540 11.835 ;
        RECT 26.910 11.685 27.160 12.275 ;
        RECT 27.880 12.155 28.435 12.705 ;
        RECT 29.120 12.715 29.815 13.345 ;
        RECT 30.960 12.715 31.655 13.345 ;
        RECT 31.825 12.840 32.085 13.345 ;
        RECT 32.775 12.965 32.945 13.345 ;
        RECT 29.120 12.665 29.295 12.715 ;
        RECT 28.615 12.275 28.950 12.545 ;
        RECT 27.835 12.105 28.435 12.155 ;
        RECT 29.120 12.115 29.290 12.665 ;
        RECT 29.460 12.275 29.795 12.525 ;
        RECT 30.455 12.275 30.790 12.545 ;
        RECT 30.960 12.115 31.130 12.715 ;
        RECT 31.300 12.275 31.635 12.525 ;
        RECT 26.830 11.175 27.160 11.685 ;
        RECT 27.670 11.985 28.435 12.105 ;
        RECT 27.670 11.140 28.000 11.985 ;
        RECT 29.055 11.135 29.385 12.115 ;
        RECT 30.895 11.135 31.225 12.115 ;
        RECT 31.825 12.040 31.995 12.840 ;
        RECT 32.280 12.795 32.945 12.965 ;
        RECT 32.280 12.540 32.450 12.795 ;
        RECT 32.165 12.210 32.450 12.540 ;
        RECT 32.280 12.065 32.450 12.210 ;
        RECT 31.825 11.135 32.095 12.040 ;
        RECT 32.280 11.895 32.945 12.065 ;
        RECT 32.775 11.135 32.945 11.895 ;
        RECT 18.945 9.825 19.255 10.625 ;
        RECT 19.905 10.165 20.165 10.625 ;
        RECT 20.765 10.165 21.025 10.625 ;
        RECT 19.905 9.995 21.025 10.165 ;
        RECT 18.945 9.655 19.975 9.825 ;
        RECT 18.945 8.745 19.115 9.655 ;
        RECT 19.285 8.915 19.635 9.485 ;
        RECT 19.805 9.405 19.975 9.655 ;
        RECT 20.765 9.745 21.025 9.995 ;
        RECT 21.795 10.125 21.965 10.625 ;
        RECT 21.795 9.955 22.460 10.125 ;
        RECT 20.765 9.575 21.520 9.745 ;
        RECT 19.805 9.235 20.945 9.405 ;
        RECT 21.115 9.065 21.520 9.575 ;
        RECT 21.710 9.135 22.060 9.785 ;
        RECT 19.870 8.895 21.520 9.065 ;
        RECT 22.230 8.965 22.460 9.955 ;
        RECT 18.945 8.415 19.245 8.745 ;
        RECT 19.870 8.505 20.165 8.895 ;
        RECT 20.765 8.505 21.025 8.895 ;
        RECT 21.795 8.795 22.460 8.965 ;
        RECT 21.795 8.505 21.965 8.795 ;
        RECT 22.635 8.505 22.860 10.625 ;
        RECT 23.575 10.125 23.745 10.625 ;
        RECT 23.980 10.410 24.810 10.580 ;
        RECT 23.050 9.955 23.745 10.125 ;
        RECT 23.050 8.985 23.220 9.955 ;
        RECT 23.390 9.165 23.800 9.785 ;
        RECT 23.970 9.735 24.470 10.115 ;
        RECT 23.050 8.795 23.745 8.985 ;
        RECT 23.970 8.865 24.190 9.735 ;
        RECT 24.640 9.565 24.810 10.410 ;
        RECT 25.610 10.245 25.780 10.535 ;
        RECT 26.750 10.325 27.380 10.575 ;
        RECT 27.210 10.245 27.380 10.325 ;
        RECT 28.180 10.245 28.420 10.535 ;
        RECT 24.980 9.995 26.350 10.245 ;
        RECT 24.980 9.735 25.230 9.995 ;
        RECT 25.740 9.565 25.990 9.725 ;
        RECT 24.640 9.395 25.990 9.565 ;
        RECT 24.640 9.355 25.060 9.395 ;
        RECT 24.370 8.805 24.720 9.175 ;
        RECT 23.575 8.465 23.745 8.795 ;
        RECT 24.890 8.625 25.060 9.355 ;
        RECT 26.160 9.225 26.350 9.995 ;
        RECT 25.230 8.895 25.640 9.225 ;
        RECT 24.045 8.425 25.060 8.625 ;
        RECT 25.930 8.885 26.350 9.225 ;
        RECT 26.520 9.815 27.040 10.125 ;
        RECT 27.210 10.075 28.420 10.245 ;
        RECT 26.520 9.055 26.690 9.815 ;
        RECT 26.860 9.225 27.040 9.635 ;
        RECT 27.210 9.565 27.380 10.075 ;
        RECT 29.150 9.925 29.320 10.535 ;
        RECT 29.590 10.075 29.920 10.585 ;
        RECT 29.150 9.905 29.470 9.925 ;
        RECT 27.550 9.735 29.470 9.905 ;
        RECT 27.210 9.395 29.110 9.565 ;
        RECT 27.440 9.055 27.770 9.175 ;
        RECT 26.520 8.885 27.770 9.055 ;
        RECT 25.930 8.455 26.180 8.885 ;
        RECT 27.940 8.635 28.110 9.395 ;
        RECT 28.780 9.335 29.110 9.395 ;
        RECT 28.300 9.165 28.630 9.225 ;
        RECT 28.300 8.895 28.960 9.165 ;
        RECT 29.280 8.840 29.470 9.735 ;
        RECT 27.260 8.465 28.110 8.635 ;
        RECT 29.150 8.510 29.470 8.840 ;
        RECT 29.670 9.485 29.920 10.075 ;
        RECT 30.565 9.815 30.820 10.485 ;
        RECT 29.670 9.155 30.470 9.485 ;
        RECT 30.640 9.435 30.820 9.815 ;
        RECT 32.000 9.645 32.330 10.625 ;
        RECT 30.640 9.265 30.905 9.435 ;
        RECT 29.670 8.505 29.920 9.155 ;
        RECT 30.640 8.955 30.820 9.265 ;
        RECT 31.600 9.235 31.930 9.475 ;
        RECT 32.100 9.045 32.330 9.645 ;
        RECT 30.565 8.425 30.820 8.955 ;
        RECT 32.000 8.415 32.330 9.045 ;
        RECT 8.915 7.525 9.085 7.815 ;
        RECT 8.915 7.355 9.580 7.525 ;
        RECT 8.830 6.535 9.180 7.185 ;
        RECT 9.350 6.365 9.580 7.355 ;
        RECT 8.915 6.195 9.580 6.365 ;
        RECT 8.915 5.695 9.085 6.195 ;
        RECT 9.755 5.695 9.980 7.815 ;
        RECT 10.695 7.525 10.865 7.855 ;
        RECT 11.165 7.695 12.180 7.895 ;
        RECT 10.170 7.335 10.865 7.525 ;
        RECT 10.170 6.365 10.340 7.335 ;
        RECT 10.510 6.535 10.920 7.155 ;
        RECT 11.090 6.585 11.310 7.455 ;
        RECT 11.490 7.145 11.840 7.515 ;
        RECT 12.010 6.965 12.180 7.695 ;
        RECT 13.050 7.435 13.300 7.865 ;
        RECT 14.380 7.685 15.230 7.855 ;
        RECT 12.350 7.095 12.760 7.425 ;
        RECT 13.050 7.095 13.470 7.435 ;
        RECT 11.760 6.925 12.180 6.965 ;
        RECT 11.760 6.755 13.110 6.925 ;
        RECT 10.170 6.195 10.865 6.365 ;
        RECT 11.090 6.205 11.590 6.585 ;
        RECT 10.695 5.695 10.865 6.195 ;
        RECT 11.760 5.910 11.930 6.755 ;
        RECT 12.860 6.595 13.110 6.755 ;
        RECT 12.100 6.325 12.350 6.585 ;
        RECT 13.280 6.325 13.470 7.095 ;
        RECT 12.100 6.075 13.470 6.325 ;
        RECT 13.640 7.265 14.890 7.435 ;
        RECT 13.640 6.505 13.810 7.265 ;
        RECT 14.560 7.145 14.890 7.265 ;
        RECT 13.980 6.685 14.160 7.095 ;
        RECT 15.060 6.925 15.230 7.685 ;
        RECT 16.270 7.480 16.590 7.810 ;
        RECT 15.420 7.155 16.080 7.425 ;
        RECT 15.420 7.095 15.750 7.155 ;
        RECT 15.900 6.925 16.230 6.985 ;
        RECT 14.330 6.755 16.230 6.925 ;
        RECT 13.640 6.195 14.160 6.505 ;
        RECT 14.330 6.245 14.500 6.755 ;
        RECT 16.400 6.585 16.590 7.480 ;
        RECT 14.670 6.415 16.590 6.585 ;
        RECT 16.270 6.395 16.590 6.415 ;
        RECT 16.790 7.165 17.040 7.815 ;
        RECT 17.685 7.365 17.940 7.895 ;
        RECT 16.790 6.835 17.590 7.165 ;
        RECT 17.760 7.055 17.940 7.365 ;
        RECT 18.575 7.525 18.745 7.815 ;
        RECT 18.575 7.355 19.240 7.525 ;
        RECT 17.760 6.885 18.025 7.055 ;
        RECT 14.330 6.075 15.540 6.245 ;
        RECT 11.100 5.740 11.930 5.910 ;
        RECT 12.730 5.785 12.900 6.075 ;
        RECT 14.330 5.995 14.500 6.075 ;
        RECT 13.870 5.745 14.500 5.995 ;
        RECT 15.300 5.785 15.540 6.075 ;
        RECT 16.270 5.785 16.440 6.395 ;
        RECT 16.790 6.245 17.040 6.835 ;
        RECT 17.760 6.505 17.940 6.885 ;
        RECT 18.490 6.535 18.840 7.185 ;
        RECT 16.710 5.735 17.040 6.245 ;
        RECT 17.685 5.835 17.940 6.505 ;
        RECT 19.010 6.365 19.240 7.355 ;
        RECT 18.575 6.195 19.240 6.365 ;
        RECT 18.575 5.695 18.745 6.195 ;
        RECT 19.415 5.695 19.640 7.815 ;
        RECT 20.355 7.525 20.525 7.855 ;
        RECT 20.825 7.695 21.840 7.895 ;
        RECT 19.830 7.335 20.525 7.525 ;
        RECT 19.830 6.365 20.000 7.335 ;
        RECT 20.170 6.535 20.580 7.155 ;
        RECT 20.750 6.585 20.970 7.455 ;
        RECT 21.150 7.145 21.500 7.515 ;
        RECT 21.670 6.965 21.840 7.695 ;
        RECT 22.710 7.435 22.960 7.865 ;
        RECT 24.040 7.685 24.890 7.855 ;
        RECT 22.010 7.095 22.420 7.425 ;
        RECT 22.710 7.095 23.130 7.435 ;
        RECT 21.420 6.925 21.840 6.965 ;
        RECT 21.420 6.755 22.770 6.925 ;
        RECT 19.830 6.195 20.525 6.365 ;
        RECT 20.750 6.205 21.250 6.585 ;
        RECT 20.355 5.695 20.525 6.195 ;
        RECT 21.420 5.910 21.590 6.755 ;
        RECT 22.520 6.595 22.770 6.755 ;
        RECT 21.760 6.325 22.010 6.585 ;
        RECT 22.940 6.325 23.130 7.095 ;
        RECT 21.760 6.075 23.130 6.325 ;
        RECT 23.300 7.265 24.550 7.435 ;
        RECT 23.300 6.505 23.470 7.265 ;
        RECT 24.220 7.145 24.550 7.265 ;
        RECT 23.640 6.685 23.820 7.095 ;
        RECT 24.720 6.925 24.890 7.685 ;
        RECT 25.930 7.480 26.250 7.810 ;
        RECT 25.080 7.155 25.740 7.425 ;
        RECT 25.080 7.095 25.410 7.155 ;
        RECT 25.560 6.925 25.890 6.985 ;
        RECT 23.990 6.755 25.890 6.925 ;
        RECT 23.300 6.195 23.820 6.505 ;
        RECT 23.990 6.245 24.160 6.755 ;
        RECT 26.060 6.585 26.250 7.480 ;
        RECT 24.330 6.415 26.250 6.585 ;
        RECT 25.930 6.395 26.250 6.415 ;
        RECT 26.450 7.165 26.700 7.815 ;
        RECT 27.345 7.735 27.600 7.895 ;
        RECT 27.345 7.565 27.685 7.735 ;
        RECT 27.345 7.365 27.600 7.565 ;
        RECT 26.450 6.835 27.250 7.165 ;
        RECT 23.990 6.075 25.200 6.245 ;
        RECT 20.760 5.740 21.590 5.910 ;
        RECT 22.390 5.785 22.560 6.075 ;
        RECT 23.990 5.995 24.160 6.075 ;
        RECT 23.530 5.745 24.160 5.995 ;
        RECT 24.960 5.785 25.200 6.075 ;
        RECT 25.930 5.785 26.100 6.395 ;
        RECT 26.450 6.245 26.700 6.835 ;
        RECT 27.420 6.505 27.600 7.365 ;
        RECT 31.080 7.275 31.410 7.905 ;
        RECT 30.680 6.845 31.010 7.085 ;
        RECT 31.180 6.675 31.410 7.275 ;
        RECT 32.340 7.275 33.035 7.905 ;
        RECT 31.835 6.835 32.170 7.105 ;
        RECT 32.340 6.675 32.510 7.275 ;
        RECT 32.680 6.835 33.015 7.085 ;
        RECT 26.370 5.735 26.700 6.245 ;
        RECT 27.345 5.835 27.600 6.505 ;
        RECT 31.080 5.695 31.410 6.675 ;
        RECT 32.275 5.695 32.605 6.675 ;
        RECT 6.615 4.685 6.785 5.185 ;
        RECT 6.615 4.515 7.280 4.685 ;
        RECT 6.530 3.695 6.880 4.345 ;
        RECT 7.050 3.525 7.280 4.515 ;
        RECT 6.615 3.355 7.280 3.525 ;
        RECT 6.615 3.065 6.785 3.355 ;
        RECT 7.455 3.065 7.680 5.185 ;
        RECT 8.395 4.685 8.565 5.185 ;
        RECT 8.800 4.970 9.630 5.140 ;
        RECT 7.870 4.515 8.565 4.685 ;
        RECT 7.870 3.545 8.040 4.515 ;
        RECT 8.210 3.725 8.620 4.345 ;
        RECT 8.790 4.295 9.290 4.675 ;
        RECT 7.870 3.355 8.565 3.545 ;
        RECT 8.790 3.425 9.010 4.295 ;
        RECT 9.460 4.125 9.630 4.970 ;
        RECT 10.430 4.805 10.600 5.095 ;
        RECT 11.570 4.885 12.200 5.135 ;
        RECT 12.030 4.805 12.200 4.885 ;
        RECT 13.000 4.805 13.240 5.095 ;
        RECT 9.800 4.555 11.170 4.805 ;
        RECT 9.800 4.295 10.050 4.555 ;
        RECT 10.560 4.125 10.810 4.285 ;
        RECT 9.460 3.955 10.810 4.125 ;
        RECT 9.460 3.915 9.880 3.955 ;
        RECT 9.190 3.365 9.540 3.735 ;
        RECT 8.395 3.025 8.565 3.355 ;
        RECT 9.710 3.185 9.880 3.915 ;
        RECT 10.980 3.785 11.170 4.555 ;
        RECT 10.050 3.455 10.460 3.785 ;
        RECT 8.865 2.985 9.880 3.185 ;
        RECT 10.750 3.445 11.170 3.785 ;
        RECT 11.340 4.375 11.860 4.685 ;
        RECT 12.030 4.635 13.240 4.805 ;
        RECT 11.340 3.615 11.510 4.375 ;
        RECT 11.680 3.785 11.860 4.195 ;
        RECT 12.030 4.125 12.200 4.635 ;
        RECT 13.970 4.485 14.140 5.095 ;
        RECT 14.410 4.635 14.740 5.145 ;
        RECT 13.970 4.465 14.290 4.485 ;
        RECT 12.370 4.295 14.290 4.465 ;
        RECT 12.030 3.955 13.930 4.125 ;
        RECT 12.260 3.615 12.590 3.735 ;
        RECT 11.340 3.445 12.590 3.615 ;
        RECT 10.750 3.015 11.000 3.445 ;
        RECT 12.760 3.195 12.930 3.955 ;
        RECT 13.600 3.895 13.930 3.955 ;
        RECT 13.120 3.725 13.450 3.785 ;
        RECT 13.120 3.455 13.780 3.725 ;
        RECT 14.100 3.400 14.290 4.295 ;
        RECT 12.080 3.025 12.930 3.195 ;
        RECT 13.970 3.070 14.290 3.400 ;
        RECT 14.490 4.045 14.740 4.635 ;
        RECT 15.385 5.015 15.640 5.045 ;
        RECT 15.385 4.845 15.725 5.015 ;
        RECT 15.385 4.375 15.640 4.845 ;
        RECT 16.735 4.685 16.905 5.185 ;
        RECT 16.735 4.515 17.400 4.685 ;
        RECT 14.490 3.715 15.290 4.045 ;
        RECT 14.490 3.065 14.740 3.715 ;
        RECT 15.460 3.515 15.640 4.375 ;
        RECT 16.650 3.695 17.000 4.345 ;
        RECT 17.170 3.525 17.400 4.515 ;
        RECT 15.385 2.985 15.640 3.515 ;
        RECT 16.735 3.355 17.400 3.525 ;
        RECT 16.735 3.065 16.905 3.355 ;
        RECT 17.575 3.065 17.800 5.185 ;
        RECT 18.515 4.685 18.685 5.185 ;
        RECT 18.920 4.970 19.750 5.140 ;
        RECT 17.990 4.515 18.685 4.685 ;
        RECT 17.990 3.545 18.160 4.515 ;
        RECT 18.330 3.725 18.740 4.345 ;
        RECT 18.910 4.295 19.410 4.675 ;
        RECT 17.990 3.355 18.685 3.545 ;
        RECT 18.910 3.425 19.130 4.295 ;
        RECT 19.580 4.125 19.750 4.970 ;
        RECT 20.550 4.805 20.720 5.095 ;
        RECT 21.690 4.885 22.320 5.135 ;
        RECT 22.150 4.805 22.320 4.885 ;
        RECT 23.120 4.805 23.360 5.095 ;
        RECT 19.920 4.555 21.290 4.805 ;
        RECT 19.920 4.295 20.170 4.555 ;
        RECT 20.680 4.125 20.930 4.285 ;
        RECT 19.580 3.955 20.930 4.125 ;
        RECT 19.580 3.915 20.000 3.955 ;
        RECT 19.310 3.365 19.660 3.735 ;
        RECT 18.515 3.025 18.685 3.355 ;
        RECT 19.830 3.185 20.000 3.915 ;
        RECT 21.100 3.785 21.290 4.555 ;
        RECT 20.170 3.455 20.580 3.785 ;
        RECT 18.985 2.985 20.000 3.185 ;
        RECT 20.870 3.445 21.290 3.785 ;
        RECT 21.460 4.375 21.980 4.685 ;
        RECT 22.150 4.635 23.360 4.805 ;
        RECT 21.460 3.615 21.630 4.375 ;
        RECT 21.800 3.785 21.980 4.195 ;
        RECT 22.150 4.125 22.320 4.635 ;
        RECT 24.090 4.485 24.260 5.095 ;
        RECT 24.530 4.635 24.860 5.145 ;
        RECT 24.090 4.465 24.410 4.485 ;
        RECT 22.490 4.295 24.410 4.465 ;
        RECT 22.150 3.955 24.050 4.125 ;
        RECT 22.380 3.615 22.710 3.735 ;
        RECT 21.460 3.445 22.710 3.615 ;
        RECT 20.870 3.015 21.120 3.445 ;
        RECT 22.880 3.195 23.050 3.955 ;
        RECT 23.720 3.895 24.050 3.955 ;
        RECT 23.240 3.725 23.570 3.785 ;
        RECT 23.240 3.455 23.900 3.725 ;
        RECT 24.220 3.400 24.410 4.295 ;
        RECT 22.200 3.025 23.050 3.195 ;
        RECT 24.090 3.070 24.410 3.400 ;
        RECT 24.610 4.045 24.860 4.635 ;
        RECT 25.505 4.375 25.760 5.045 ;
        RECT 24.610 3.715 25.410 4.045 ;
        RECT 24.610 3.065 24.860 3.715 ;
        RECT 25.580 3.515 25.760 4.375 ;
        RECT 25.505 3.315 25.760 3.515 ;
        RECT 25.505 3.145 25.845 3.315 ;
        RECT 25.505 2.985 25.760 3.145 ;
      LAYER mcon ;
        RECT 17.165 37.485 17.335 37.655 ;
        RECT 19.925 37.145 20.095 37.315 ;
        RECT 16.705 36.465 16.875 36.635 ;
        RECT 17.625 36.465 17.795 36.635 ;
        RECT 20.560 36.465 20.730 36.635 ;
        RECT 21.075 36.465 21.245 36.635 ;
        RECT 22.225 36.465 22.395 36.635 ;
        RECT 23.145 36.465 23.315 36.635 ;
        RECT 24.065 36.465 24.235 36.635 ;
        RECT 24.985 36.465 25.155 36.635 ;
        RECT 25.620 36.465 25.790 36.635 ;
        RECT 27.000 36.470 27.170 36.640 ;
        RECT 23.145 35.785 23.315 35.955 ;
        RECT 24.985 35.785 25.155 35.955 ;
        RECT 26.135 36.125 26.305 36.295 ;
        RECT 29.585 37.145 29.755 37.315 ;
        RECT 27.515 36.125 27.685 36.295 ;
        RECT 28.205 36.125 28.375 36.295 ;
        RECT 29.125 36.465 29.295 36.635 ;
        RECT 29.585 36.465 29.755 36.635 ;
        RECT 30.505 36.465 30.675 36.635 ;
        RECT 31.425 36.465 31.595 36.635 ;
        RECT 31.885 36.465 32.055 36.635 ;
        RECT 30.965 35.785 31.135 35.955 ;
        RECT 32.805 36.465 32.975 36.635 ;
        RECT 32.345 35.785 32.515 35.955 ;
        RECT 16.475 34.765 16.645 34.935 ;
        RECT 17.855 34.765 18.025 34.935 ;
        RECT 16.120 34.085 16.290 34.255 ;
        RECT 17.500 34.085 17.670 34.255 ;
        RECT 30.965 34.425 31.135 34.595 ;
        RECT 21.765 34.085 21.935 34.255 ;
        RECT 30.505 34.085 30.675 34.255 ;
        RECT 31.425 34.085 31.595 34.255 ;
        RECT 17.800 31.025 17.970 31.195 ;
        RECT 19.465 31.365 19.635 31.535 ;
        RECT 22.685 32.045 22.855 32.215 ;
        RECT 19.005 31.025 19.175 31.195 ;
        RECT 18.315 30.685 18.485 30.855 ;
        RECT 19.925 31.025 20.095 31.195 ;
        RECT 21.305 30.685 21.475 30.855 ;
        RECT 22.225 31.025 22.395 31.195 ;
        RECT 22.685 31.025 22.855 31.195 ;
        RECT 25.445 31.025 25.615 31.195 ;
        RECT 16.245 28.645 16.415 28.815 ;
        RECT 18.545 28.645 18.715 28.815 ;
        RECT 32.345 28.985 32.515 29.155 ;
        RECT 19.005 28.645 19.175 28.815 ;
        RECT 19.925 28.645 20.095 28.815 ;
        RECT 30.965 28.645 31.135 28.815 ;
        RECT 31.885 28.645 32.055 28.815 ;
        RECT 17.625 27.625 17.795 27.795 ;
        RECT 7.050 26.265 7.220 26.435 ;
        RECT 6.585 25.585 6.755 25.755 ;
        RECT 7.510 25.245 7.680 25.415 ;
        RECT 8.910 26.265 9.080 26.435 ;
        RECT 8.425 25.925 8.595 26.095 ;
        RECT 9.370 25.245 9.540 25.415 ;
        RECT 10.290 25.245 10.460 25.415 ;
        RECT 11.690 26.265 11.860 26.435 ;
        RECT 11.690 25.585 11.860 25.755 ;
        RECT 13.550 25.245 13.720 25.415 ;
        RECT 25.445 25.585 25.615 25.755 ;
        RECT 15.555 24.905 15.725 25.075 ;
        RECT 10.725 23.205 10.895 23.375 ;
        RECT 11.190 22.525 11.360 22.695 ;
        RECT 11.650 23.545 11.820 23.715 ;
        RECT 12.565 22.865 12.735 23.035 ;
        RECT 13.510 23.545 13.680 23.715 ;
        RECT 14.430 23.545 14.600 23.715 ;
        RECT 13.050 22.525 13.220 22.695 ;
        RECT 15.830 23.205 16.000 23.375 ;
        RECT 17.690 23.545 17.860 23.715 ;
        RECT 15.830 22.525 16.000 22.695 ;
        RECT 19.695 23.885 19.865 24.055 ;
        RECT 20.385 23.205 20.555 23.375 ;
        RECT 20.850 22.525 21.020 22.695 ;
        RECT 21.310 23.545 21.480 23.715 ;
        RECT 22.225 23.205 22.395 23.375 ;
        RECT 23.170 23.545 23.340 23.715 ;
        RECT 24.090 23.545 24.260 23.715 ;
        RECT 22.710 22.525 22.880 22.695 ;
        RECT 25.490 23.205 25.660 23.375 ;
        RECT 27.350 23.545 27.520 23.715 ;
        RECT 25.490 22.525 25.660 22.695 ;
        RECT 29.355 23.885 29.525 24.055 ;
        RECT 32.575 23.885 32.745 24.055 ;
        RECT 30.840 23.205 31.010 23.375 ;
        RECT 32.060 23.205 32.230 23.375 ;
        RECT 31.195 22.525 31.365 22.695 ;
        RECT 6.590 20.825 6.760 20.995 ;
        RECT 6.125 20.145 6.295 20.315 ;
        RECT 7.050 19.805 7.220 19.975 ;
        RECT 8.450 20.825 8.620 20.995 ;
        RECT 7.965 20.485 8.135 20.655 ;
        RECT 8.910 19.805 9.080 19.975 ;
        RECT 9.830 19.805 10.000 19.975 ;
        RECT 11.230 20.825 11.400 20.995 ;
        RECT 11.230 20.145 11.400 20.315 ;
        RECT 13.090 19.805 13.260 19.975 ;
        RECT 17.630 20.825 17.800 20.995 ;
        RECT 17.165 20.485 17.335 20.655 ;
        RECT 15.095 20.145 15.265 20.315 ;
        RECT 18.090 19.805 18.260 19.975 ;
        RECT 19.490 20.825 19.660 20.995 ;
        RECT 19.005 20.145 19.175 20.315 ;
        RECT 19.950 19.805 20.120 19.975 ;
        RECT 20.870 19.805 21.040 19.975 ;
        RECT 22.270 20.825 22.440 20.995 ;
        RECT 22.270 20.145 22.440 20.315 ;
        RECT 24.130 19.805 24.300 19.975 ;
        RECT 28.665 20.145 28.835 20.315 ;
        RECT 29.585 20.145 29.755 20.315 ;
        RECT 26.135 19.465 26.305 19.635 ;
        RECT 29.125 19.465 29.295 19.635 ;
        RECT 20.385 18.445 20.555 18.615 ;
        RECT 21.765 18.445 21.935 18.615 ;
        RECT 19.925 17.765 20.095 17.935 ;
        RECT 20.845 17.765 21.015 17.935 ;
        RECT 21.305 17.815 21.475 17.985 ;
        RECT 22.225 17.765 22.395 17.935 ;
        RECT 22.685 17.765 22.855 17.935 ;
        RECT 23.605 17.765 23.775 17.935 ;
        RECT 24.240 17.765 24.410 17.935 ;
        RECT 27.285 17.765 27.455 17.935 ;
        RECT 28.205 17.765 28.375 17.935 ;
        RECT 23.145 16.745 23.315 16.915 ;
        RECT 24.755 17.425 24.925 17.595 ;
        RECT 27.285 17.085 27.455 17.255 ;
        RECT 31.885 16.745 32.055 16.915 ;
        RECT 17.625 15.725 17.795 15.895 ;
        RECT 21.765 14.705 21.935 14.875 ;
        RECT 24.295 15.725 24.465 15.895 ;
        RECT 27.055 15.725 27.225 15.895 ;
        RECT 23.940 14.705 24.110 14.875 ;
        RECT 26.700 14.705 26.870 14.875 ;
        RECT 28.205 14.705 28.375 14.875 ;
        RECT 22.685 14.025 22.855 14.195 ;
        RECT 31.885 15.725 32.055 15.895 ;
        RECT 31.425 14.365 31.595 14.535 ;
        RECT 30.505 14.025 30.675 14.195 ;
        RECT 32.345 14.705 32.515 14.875 ;
        RECT 32.805 14.705 32.975 14.875 ;
        RECT 19.005 11.985 19.175 12.155 ;
        RECT 19.465 11.645 19.635 11.815 ;
        RECT 19.925 12.665 20.095 12.835 ;
        RECT 20.845 12.325 21.015 12.495 ;
        RECT 21.765 12.665 21.935 12.835 ;
        RECT 22.685 12.665 22.855 12.835 ;
        RECT 21.305 11.645 21.475 11.815 ;
        RECT 24.085 12.325 24.255 12.495 ;
        RECT 25.905 12.665 26.075 12.835 ;
        RECT 24.065 11.645 24.235 11.815 ;
        RECT 29.125 12.665 29.295 12.835 ;
        RECT 30.965 13.005 31.135 13.175 ;
        RECT 31.885 13.005 32.055 13.175 ;
        RECT 28.205 12.325 28.375 12.495 ;
        RECT 28.665 12.325 28.835 12.495 ;
        RECT 29.585 12.325 29.755 12.495 ;
        RECT 30.505 12.325 30.675 12.495 ;
        RECT 31.425 12.325 31.595 12.495 ;
        RECT 19.465 9.265 19.635 9.435 ;
        RECT 22.230 9.945 22.400 10.115 ;
        RECT 21.765 9.265 21.935 9.435 ;
        RECT 19.925 8.585 20.095 8.755 ;
        RECT 22.690 8.925 22.860 9.095 ;
        RECT 24.090 9.945 24.260 10.115 ;
        RECT 23.605 9.265 23.775 9.435 ;
        RECT 24.550 8.925 24.720 9.095 ;
        RECT 25.470 8.925 25.640 9.095 ;
        RECT 26.870 9.945 27.040 10.115 ;
        RECT 26.870 9.265 27.040 9.435 ;
        RECT 28.730 8.925 28.900 9.095 ;
        RECT 32.115 10.285 32.285 10.455 ;
        RECT 30.735 9.265 30.905 9.435 ;
        RECT 31.600 9.265 31.770 9.435 ;
        RECT 8.885 6.545 9.055 6.715 ;
        RECT 9.350 6.205 9.520 6.375 ;
        RECT 9.810 7.225 9.980 7.395 ;
        RECT 10.725 6.545 10.895 6.715 ;
        RECT 11.670 7.225 11.840 7.395 ;
        RECT 12.590 7.225 12.760 7.395 ;
        RECT 11.210 6.205 11.380 6.375 ;
        RECT 13.990 6.885 14.160 7.055 ;
        RECT 15.850 7.225 16.020 7.395 ;
        RECT 13.990 6.205 14.160 6.375 ;
        RECT 17.855 6.885 18.025 7.055 ;
        RECT 18.545 6.545 18.715 6.715 ;
        RECT 19.010 6.205 19.180 6.375 ;
        RECT 19.470 7.225 19.640 7.395 ;
        RECT 20.385 6.885 20.555 7.055 ;
        RECT 21.330 7.225 21.500 7.395 ;
        RECT 22.250 7.225 22.420 7.395 ;
        RECT 20.870 6.205 21.040 6.375 ;
        RECT 23.650 6.885 23.820 7.055 ;
        RECT 25.510 7.225 25.680 7.395 ;
        RECT 23.650 6.205 23.820 6.375 ;
        RECT 27.515 7.565 27.685 7.735 ;
        RECT 31.195 7.225 31.365 7.395 ;
        RECT 30.680 6.885 30.850 7.055 ;
        RECT 32.345 7.565 32.515 7.735 ;
        RECT 31.885 6.885 32.055 7.055 ;
        RECT 32.805 6.885 32.975 7.055 ;
        RECT 7.050 4.505 7.220 4.675 ;
        RECT 6.585 4.165 6.755 4.335 ;
        RECT 7.510 3.485 7.680 3.655 ;
        RECT 8.910 4.505 9.080 4.675 ;
        RECT 8.425 3.825 8.595 3.995 ;
        RECT 9.370 3.485 9.540 3.655 ;
        RECT 10.290 3.485 10.460 3.655 ;
        RECT 11.690 4.505 11.860 4.675 ;
        RECT 11.690 3.825 11.860 3.995 ;
        RECT 13.550 3.485 13.720 3.655 ;
        RECT 15.555 4.845 15.725 5.015 ;
        RECT 17.170 4.505 17.340 4.675 ;
        RECT 16.705 4.165 16.875 4.335 ;
        RECT 17.630 3.485 17.800 3.655 ;
        RECT 19.030 4.505 19.200 4.675 ;
        RECT 18.545 4.165 18.715 4.335 ;
        RECT 19.490 3.485 19.660 3.655 ;
        RECT 20.410 3.485 20.580 3.655 ;
        RECT 21.810 4.505 21.980 4.675 ;
        RECT 21.810 3.825 21.980 3.995 ;
        RECT 23.670 3.485 23.840 3.655 ;
        RECT 25.675 3.145 25.845 3.315 ;
      LAYER met1 ;
        RECT 17.105 37.640 17.395 37.685 ;
        RECT 17.105 37.500 29.280 37.640 ;
        RECT 17.105 37.455 17.395 37.500 ;
        RECT 19.865 37.300 20.155 37.345 ;
        RECT 28.590 37.300 28.910 37.360 ;
        RECT 19.480 37.160 28.910 37.300 ;
        RECT 16.645 36.620 16.935 36.665 ;
        RECT 17.550 36.620 17.870 36.680 ;
        RECT 15.800 36.480 16.935 36.620 ;
        RECT 17.355 36.480 17.870 36.620 ;
        RECT 19.480 36.620 19.620 37.160 ;
        RECT 19.865 37.115 20.155 37.160 ;
        RECT 19.850 36.620 20.170 36.680 ;
        RECT 20.500 36.620 20.790 36.665 ;
        RECT 19.480 36.480 20.790 36.620 ;
        RECT 15.800 35.940 15.940 36.480 ;
        RECT 16.645 36.435 16.935 36.480 ;
        RECT 17.550 36.420 17.870 36.480 ;
        RECT 19.850 36.420 20.170 36.480 ;
        RECT 20.500 36.435 20.790 36.480 ;
        RECT 21.015 36.620 21.305 36.665 ;
        RECT 22.165 36.620 22.455 36.665 ;
        RECT 23.085 36.620 23.375 36.665 ;
        RECT 23.990 36.620 24.310 36.680 ;
        RECT 25.460 36.665 25.600 37.160 ;
        RECT 28.590 37.100 28.910 37.160 ;
        RECT 29.140 36.960 29.280 37.500 ;
        RECT 29.600 37.500 32.960 37.640 ;
        RECT 29.600 37.345 29.740 37.500 ;
        RECT 29.525 37.115 29.815 37.345 ;
        RECT 29.140 36.820 29.740 36.960 ;
        RECT 26.750 36.670 27.070 36.680 ;
        RECT 21.015 36.480 22.455 36.620 ;
        RECT 21.015 36.435 21.305 36.480 ;
        RECT 22.165 36.435 22.455 36.480 ;
        RECT 22.700 36.480 23.375 36.620 ;
        RECT 23.795 36.480 24.310 36.620 ;
        RECT 16.630 35.940 16.950 36.000 ;
        RECT 22.700 35.940 22.840 36.480 ;
        RECT 23.085 36.435 23.375 36.480 ;
        RECT 23.990 36.420 24.310 36.480 ;
        RECT 24.925 36.435 25.215 36.665 ;
        RECT 25.460 36.480 25.850 36.665 ;
        RECT 25.560 36.435 25.850 36.480 ;
        RECT 26.750 36.440 27.230 36.670 ;
        RECT 29.050 36.620 29.370 36.680 ;
        RECT 29.600 36.665 29.740 36.820 ;
        RECT 28.855 36.480 29.370 36.620 ;
        RECT 25.000 36.280 25.140 36.435 ;
        RECT 26.750 36.420 27.070 36.440 ;
        RECT 29.050 36.420 29.370 36.480 ;
        RECT 29.525 36.435 29.815 36.665 ;
        RECT 30.445 36.620 30.735 36.665 ;
        RECT 30.890 36.620 31.210 36.680 ;
        RECT 30.445 36.480 31.210 36.620 ;
        RECT 30.445 36.435 30.735 36.480 ;
        RECT 26.075 36.280 26.365 36.325 ;
        RECT 25.000 36.140 26.365 36.280 ;
        RECT 26.075 36.095 26.365 36.140 ;
        RECT 27.455 36.280 27.745 36.325 ;
        RECT 28.145 36.280 28.435 36.325 ;
        RECT 27.455 36.140 28.435 36.280 ;
        RECT 27.455 36.095 27.745 36.140 ;
        RECT 28.145 36.095 28.435 36.140 ;
        RECT 28.590 36.280 28.910 36.340 ;
        RECT 30.520 36.280 30.660 36.435 ;
        RECT 30.890 36.420 31.210 36.480 ;
        RECT 31.365 36.435 31.655 36.665 ;
        RECT 31.825 36.620 32.115 36.665 ;
        RECT 32.270 36.620 32.590 36.680 ;
        RECT 32.820 36.665 32.960 37.500 ;
        RECT 31.825 36.480 32.590 36.620 ;
        RECT 31.825 36.435 32.115 36.480 ;
        RECT 28.590 36.140 30.660 36.280 ;
        RECT 31.440 36.280 31.580 36.435 ;
        RECT 32.270 36.420 32.590 36.480 ;
        RECT 32.745 36.435 33.035 36.665 ;
        RECT 31.440 36.140 32.040 36.280 ;
        RECT 28.590 36.080 28.910 36.140 ;
        RECT 31.900 36.000 32.040 36.140 ;
        RECT 15.800 35.800 22.840 35.940 ;
        RECT 23.085 35.940 23.375 35.985 ;
        RECT 23.530 35.940 23.850 36.000 ;
        RECT 24.910 35.940 25.230 36.000 ;
        RECT 23.085 35.800 23.850 35.940 ;
        RECT 24.715 35.800 25.230 35.940 ;
        RECT 16.630 35.740 16.950 35.800 ;
        RECT 23.085 35.755 23.375 35.800 ;
        RECT 23.530 35.740 23.850 35.800 ;
        RECT 24.910 35.740 25.230 35.800 ;
        RECT 25.370 35.940 25.690 36.000 ;
        RECT 30.905 35.940 31.195 35.985 ;
        RECT 25.370 35.800 31.195 35.940 ;
        RECT 25.370 35.740 25.690 35.800 ;
        RECT 30.905 35.755 31.195 35.800 ;
        RECT 31.810 35.940 32.130 36.000 ;
        RECT 32.285 35.940 32.575 35.985 ;
        RECT 31.810 35.800 32.575 35.940 ;
        RECT 31.810 35.740 32.130 35.800 ;
        RECT 32.285 35.755 32.575 35.800 ;
        RECT 16.630 34.965 16.950 34.980 ;
        RECT 16.415 34.735 16.950 34.965 ;
        RECT 16.630 34.720 16.950 34.735 ;
        RECT 17.550 34.965 17.870 34.980 ;
        RECT 17.550 34.735 18.085 34.965 ;
        RECT 18.930 34.920 19.250 34.980 ;
        RECT 23.990 34.920 24.310 34.980 ;
        RECT 18.495 34.780 24.310 34.920 ;
        RECT 17.550 34.720 17.870 34.735 ;
        RECT 18.560 34.580 18.700 34.780 ;
        RECT 18.930 34.720 19.250 34.780 ;
        RECT 23.990 34.720 24.310 34.780 ;
        RECT 24.910 34.920 25.230 34.980 ;
        RECT 29.050 34.920 29.370 34.980 ;
        RECT 24.910 34.780 29.370 34.920 ;
        RECT 24.910 34.720 25.230 34.780 ;
        RECT 29.050 34.720 29.370 34.780 ;
        RECT 30.905 34.580 31.195 34.625 ;
        RECT 16.720 34.440 18.700 34.580 ;
        RECT 21.780 34.440 31.195 34.580 ;
        RECT 16.060 34.240 16.350 34.285 ;
        RECT 16.720 34.240 16.860 34.440 ;
        RECT 17.550 34.285 17.870 34.300 ;
        RECT 17.440 34.240 17.870 34.285 ;
        RECT 19.850 34.240 20.170 34.300 ;
        RECT 21.780 34.285 21.920 34.440 ;
        RECT 30.905 34.395 31.195 34.440 ;
        RECT 16.060 34.100 16.860 34.240 ;
        RECT 17.115 34.100 20.170 34.240 ;
        RECT 16.060 34.055 16.350 34.100 ;
        RECT 17.440 34.055 17.870 34.100 ;
        RECT 17.550 34.040 17.870 34.055 ;
        RECT 19.850 34.040 20.170 34.100 ;
        RECT 21.705 34.055 21.995 34.285 ;
        RECT 30.430 34.240 30.750 34.300 ;
        RECT 31.350 34.240 31.670 34.300 ;
        RECT 30.235 34.100 30.750 34.240 ;
        RECT 31.155 34.100 31.670 34.240 ;
        RECT 30.430 34.040 30.750 34.100 ;
        RECT 31.350 34.040 31.670 34.100 ;
        RECT 22.625 32.200 22.915 32.245 ;
        RECT 32.270 32.200 32.590 32.260 ;
        RECT 22.625 32.060 32.590 32.200 ;
        RECT 22.625 32.015 22.915 32.060 ;
        RECT 32.270 32.000 32.590 32.060 ;
        RECT 23.530 31.660 23.850 31.920 ;
        RECT 19.405 31.520 19.695 31.565 ;
        RECT 23.620 31.520 23.760 31.660 ;
        RECT 19.405 31.380 22.380 31.520 ;
        RECT 19.405 31.335 19.695 31.380 ;
        RECT 17.550 31.225 17.870 31.240 ;
        RECT 17.550 30.995 18.030 31.225 ;
        RECT 18.930 31.180 19.250 31.240 ;
        RECT 22.240 31.225 22.380 31.380 ;
        RECT 22.700 31.380 23.760 31.520 ;
        RECT 22.700 31.225 22.840 31.380 ;
        RECT 18.735 31.040 19.250 31.180 ;
        RECT 17.550 30.980 17.870 30.995 ;
        RECT 18.930 30.980 19.250 31.040 ;
        RECT 19.865 30.995 20.155 31.225 ;
        RECT 22.165 30.995 22.455 31.225 ;
        RECT 22.625 30.995 22.915 31.225 ;
        RECT 25.385 31.180 25.675 31.225 ;
        RECT 32.270 31.180 32.590 31.240 ;
        RECT 25.385 31.040 32.590 31.180 ;
        RECT 25.385 30.995 25.675 31.040 ;
        RECT 18.255 30.840 18.545 30.885 ;
        RECT 19.940 30.840 20.080 30.995 ;
        RECT 32.270 30.980 32.590 31.040 ;
        RECT 18.255 30.700 20.080 30.840 ;
        RECT 21.245 30.840 21.535 30.885 ;
        RECT 26.750 30.840 27.070 30.900 ;
        RECT 21.245 30.700 27.070 30.840 ;
        RECT 18.255 30.655 18.545 30.700 ;
        RECT 21.245 30.655 21.535 30.700 ;
        RECT 26.750 30.640 27.070 30.700 ;
        RECT 32.270 29.140 32.590 29.200 ;
        RECT 18.560 29.000 32.590 29.140 ;
        RECT 16.170 28.800 16.490 28.860 ;
        RECT 18.560 28.845 18.700 29.000 ;
        RECT 32.270 28.940 32.590 29.000 ;
        RECT 15.975 28.660 16.490 28.800 ;
        RECT 16.170 28.600 16.490 28.660 ;
        RECT 18.485 28.615 18.775 28.845 ;
        RECT 18.945 28.800 19.235 28.845 ;
        RECT 19.865 28.800 20.155 28.845 ;
        RECT 30.890 28.800 31.210 28.860 ;
        RECT 31.810 28.800 32.130 28.860 ;
        RECT 18.945 28.660 20.155 28.800 ;
        RECT 30.695 28.660 31.210 28.800 ;
        RECT 31.615 28.660 32.130 28.800 ;
        RECT 18.945 28.615 19.235 28.660 ;
        RECT 19.865 28.615 20.155 28.660 ;
        RECT 30.890 28.600 31.210 28.660 ;
        RECT 31.810 28.600 32.130 28.660 ;
        RECT 17.565 27.780 17.855 27.825 ;
        RECT 18.470 27.780 18.790 27.840 ;
        RECT 17.565 27.640 18.790 27.780 ;
        RECT 17.565 27.595 17.855 27.640 ;
        RECT 18.470 27.580 18.790 27.640 ;
        RECT 6.990 26.420 7.280 26.465 ;
        RECT 8.850 26.420 9.140 26.465 ;
        RECT 11.630 26.420 11.920 26.465 ;
        RECT 6.990 26.280 11.920 26.420 ;
        RECT 6.990 26.235 7.280 26.280 ;
        RECT 8.850 26.235 9.140 26.280 ;
        RECT 11.630 26.235 11.920 26.280 ;
        RECT 8.365 26.080 8.655 26.125 ;
        RECT 14.790 26.080 15.110 26.140 ;
        RECT 8.365 25.940 15.110 26.080 ;
        RECT 8.365 25.895 8.655 25.940 ;
        RECT 14.790 25.880 15.110 25.940 ;
        RECT 6.510 25.740 6.830 25.800 ;
        RECT 11.630 25.740 11.920 25.785 ;
        RECT 25.370 25.740 25.690 25.800 ;
        RECT 6.315 25.600 6.830 25.740 ;
        RECT 6.510 25.540 6.830 25.600 ;
        RECT 9.385 25.600 11.920 25.740 ;
        RECT 25.175 25.600 25.690 25.740 ;
        RECT 9.385 25.445 9.600 25.600 ;
        RECT 11.630 25.555 11.920 25.600 ;
        RECT 25.370 25.540 25.690 25.600 ;
        RECT 7.450 25.400 7.740 25.445 ;
        RECT 9.310 25.400 9.600 25.445 ;
        RECT 7.450 25.260 9.600 25.400 ;
        RECT 7.450 25.215 7.740 25.260 ;
        RECT 9.310 25.215 9.600 25.260 ;
        RECT 10.230 25.400 10.520 25.445 ;
        RECT 12.950 25.400 13.270 25.460 ;
        RECT 13.490 25.400 13.780 25.445 ;
        RECT 10.230 25.260 13.780 25.400 ;
        RECT 10.230 25.215 10.520 25.260 ;
        RECT 12.950 25.200 13.270 25.260 ;
        RECT 13.490 25.215 13.780 25.260 ;
        RECT 12.490 25.060 12.810 25.120 ;
        RECT 15.495 25.060 15.785 25.105 ;
        RECT 12.490 24.920 15.785 25.060 ;
        RECT 12.490 24.860 12.810 24.920 ;
        RECT 15.495 24.875 15.785 24.920 ;
        RECT 12.950 24.040 13.270 24.100 ;
        RECT 18.930 24.040 19.250 24.100 ;
        RECT 19.635 24.040 19.925 24.085 ;
        RECT 26.750 24.040 27.070 24.100 ;
        RECT 29.295 24.040 29.585 24.085 ;
        RECT 12.950 23.900 14.100 24.040 ;
        RECT 12.950 23.840 13.270 23.900 ;
        RECT 11.590 23.700 11.880 23.745 ;
        RECT 13.450 23.700 13.740 23.745 ;
        RECT 11.590 23.560 13.740 23.700 ;
        RECT 13.960 23.700 14.100 23.900 ;
        RECT 18.930 23.900 21.000 24.040 ;
        RECT 18.930 23.840 19.250 23.900 ;
        RECT 19.635 23.855 19.925 23.900 ;
        RECT 14.370 23.700 14.660 23.745 ;
        RECT 17.630 23.700 17.920 23.745 ;
        RECT 13.960 23.560 17.920 23.700 ;
        RECT 11.590 23.515 11.880 23.560 ;
        RECT 13.450 23.515 13.740 23.560 ;
        RECT 14.370 23.515 14.660 23.560 ;
        RECT 17.630 23.515 17.920 23.560 ;
        RECT 6.510 23.360 6.830 23.420 ;
        RECT 10.665 23.360 10.955 23.405 ;
        RECT 13.525 23.360 13.740 23.515 ;
        RECT 15.770 23.360 16.060 23.405 ;
        RECT 6.510 23.220 13.180 23.360 ;
        RECT 13.525 23.220 16.060 23.360 ;
        RECT 6.510 23.160 6.830 23.220 ;
        RECT 10.665 23.175 10.955 23.220 ;
        RECT 12.490 23.020 12.810 23.080 ;
        RECT 12.295 22.880 12.810 23.020 ;
        RECT 13.040 23.020 13.180 23.220 ;
        RECT 15.770 23.175 16.060 23.220 ;
        RECT 18.470 23.360 18.790 23.420 ;
        RECT 20.325 23.360 20.615 23.405 ;
        RECT 18.470 23.220 20.615 23.360 ;
        RECT 20.860 23.360 21.000 23.900 ;
        RECT 26.750 23.900 29.585 24.040 ;
        RECT 26.750 23.840 27.070 23.900 ;
        RECT 29.295 23.855 29.585 23.900 ;
        RECT 31.350 24.040 31.670 24.100 ;
        RECT 32.515 24.040 32.805 24.085 ;
        RECT 31.350 23.900 32.805 24.040 ;
        RECT 31.350 23.840 31.670 23.900 ;
        RECT 32.515 23.855 32.805 23.900 ;
        RECT 23.990 23.745 24.310 23.760 ;
        RECT 21.250 23.700 21.540 23.745 ;
        RECT 23.110 23.700 23.400 23.745 ;
        RECT 21.250 23.560 23.400 23.700 ;
        RECT 21.250 23.515 21.540 23.560 ;
        RECT 23.110 23.515 23.400 23.560 ;
        RECT 22.165 23.360 22.455 23.405 ;
        RECT 20.860 23.220 22.455 23.360 ;
        RECT 23.185 23.360 23.400 23.515 ;
        RECT 23.990 23.700 24.320 23.745 ;
        RECT 27.290 23.700 27.580 23.745 ;
        RECT 23.990 23.560 27.580 23.700 ;
        RECT 23.990 23.515 24.320 23.560 ;
        RECT 27.290 23.515 27.580 23.560 ;
        RECT 23.990 23.500 24.310 23.515 ;
        RECT 30.890 23.405 31.210 23.420 ;
        RECT 25.430 23.360 25.720 23.405 ;
        RECT 23.185 23.220 25.720 23.360 ;
        RECT 18.470 23.160 18.790 23.220 ;
        RECT 20.325 23.175 20.615 23.220 ;
        RECT 22.165 23.175 22.455 23.220 ;
        RECT 25.430 23.175 25.720 23.220 ;
        RECT 30.780 23.175 31.210 23.405 ;
        RECT 30.890 23.160 31.210 23.175 ;
        RECT 31.810 23.405 32.130 23.420 ;
        RECT 31.810 23.175 32.290 23.405 ;
        RECT 31.810 23.160 32.130 23.175 ;
        RECT 18.560 23.020 18.700 23.160 ;
        RECT 13.040 22.880 18.700 23.020 ;
        RECT 12.490 22.820 12.810 22.880 ;
        RECT 11.130 22.680 11.420 22.725 ;
        RECT 12.990 22.680 13.280 22.725 ;
        RECT 15.770 22.680 16.060 22.725 ;
        RECT 11.130 22.540 16.060 22.680 ;
        RECT 11.130 22.495 11.420 22.540 ;
        RECT 12.990 22.495 13.280 22.540 ;
        RECT 15.770 22.495 16.060 22.540 ;
        RECT 20.790 22.680 21.080 22.725 ;
        RECT 22.650 22.680 22.940 22.725 ;
        RECT 25.430 22.680 25.720 22.725 ;
        RECT 20.790 22.540 25.720 22.680 ;
        RECT 20.790 22.495 21.080 22.540 ;
        RECT 22.650 22.495 22.940 22.540 ;
        RECT 25.430 22.495 25.720 22.540 ;
        RECT 30.430 22.680 30.750 22.740 ;
        RECT 31.135 22.680 31.425 22.725 ;
        RECT 30.430 22.540 31.425 22.680 ;
        RECT 30.430 22.480 30.750 22.540 ;
        RECT 31.135 22.495 31.425 22.540 ;
        RECT 12.950 21.320 13.270 21.380 ;
        RECT 20.770 21.320 21.090 21.380 ;
        RECT 23.990 21.320 24.310 21.380 ;
        RECT 12.950 21.180 24.310 21.320 ;
        RECT 12.950 21.120 13.270 21.180 ;
        RECT 20.770 21.120 21.090 21.180 ;
        RECT 23.990 21.120 24.310 21.180 ;
        RECT 6.530 20.980 6.820 21.025 ;
        RECT 8.390 20.980 8.680 21.025 ;
        RECT 11.170 20.980 11.460 21.025 ;
        RECT 6.530 20.840 11.460 20.980 ;
        RECT 6.530 20.795 6.820 20.840 ;
        RECT 8.390 20.795 8.680 20.840 ;
        RECT 11.170 20.795 11.460 20.840 ;
        RECT 17.570 20.980 17.860 21.025 ;
        RECT 19.430 20.980 19.720 21.025 ;
        RECT 22.210 20.980 22.500 21.025 ;
        RECT 17.570 20.840 22.500 20.980 ;
        RECT 17.570 20.795 17.860 20.840 ;
        RECT 19.430 20.795 19.720 20.840 ;
        RECT 22.210 20.795 22.500 20.840 ;
        RECT 7.905 20.640 8.195 20.685 ;
        RECT 17.105 20.640 17.395 20.685 ;
        RECT 18.470 20.640 18.790 20.700 ;
        RECT 7.905 20.500 16.860 20.640 ;
        RECT 7.905 20.455 8.195 20.500 ;
        RECT 6.065 20.300 6.355 20.345 ;
        RECT 6.510 20.300 6.830 20.360 ;
        RECT 14.790 20.345 15.110 20.360 ;
        RECT 11.170 20.300 11.460 20.345 ;
        RECT 6.065 20.160 6.830 20.300 ;
        RECT 6.065 20.115 6.355 20.160 ;
        RECT 6.510 20.100 6.830 20.160 ;
        RECT 8.925 20.160 11.460 20.300 ;
        RECT 8.925 20.005 9.140 20.160 ;
        RECT 11.170 20.115 11.460 20.160 ;
        RECT 14.790 20.115 15.325 20.345 ;
        RECT 16.720 20.300 16.860 20.500 ;
        RECT 17.105 20.500 18.790 20.640 ;
        RECT 17.105 20.455 17.395 20.500 ;
        RECT 18.470 20.440 18.790 20.500 ;
        RECT 18.930 20.300 19.250 20.360 ;
        RECT 22.210 20.300 22.500 20.345 ;
        RECT 28.590 20.300 28.910 20.360 ;
        RECT 29.510 20.300 29.830 20.360 ;
        RECT 16.720 20.160 17.320 20.300 ;
        RECT 18.735 20.160 19.250 20.300 ;
        RECT 14.790 20.100 15.110 20.115 ;
        RECT 12.950 20.005 13.270 20.020 ;
        RECT 6.990 19.960 7.280 20.005 ;
        RECT 8.850 19.960 9.140 20.005 ;
        RECT 6.990 19.820 9.140 19.960 ;
        RECT 6.990 19.775 7.280 19.820 ;
        RECT 8.850 19.775 9.140 19.820 ;
        RECT 9.770 19.960 10.060 20.005 ;
        RECT 12.950 19.960 13.320 20.005 ;
        RECT 9.770 19.820 13.320 19.960 ;
        RECT 9.770 19.775 10.060 19.820 ;
        RECT 12.950 19.775 13.320 19.820 ;
        RECT 12.950 19.760 13.270 19.775 ;
        RECT 17.180 19.620 17.320 20.160 ;
        RECT 18.930 20.100 19.250 20.160 ;
        RECT 19.965 20.160 22.500 20.300 ;
        RECT 28.395 20.160 28.910 20.300 ;
        RECT 29.315 20.160 29.830 20.300 ;
        RECT 19.965 20.005 20.180 20.160 ;
        RECT 22.210 20.115 22.500 20.160 ;
        RECT 28.590 20.100 28.910 20.160 ;
        RECT 29.510 20.100 29.830 20.160 ;
        RECT 18.030 19.960 18.320 20.005 ;
        RECT 19.890 19.960 20.180 20.005 ;
        RECT 18.030 19.820 20.180 19.960 ;
        RECT 18.030 19.775 18.320 19.820 ;
        RECT 19.890 19.775 20.180 19.820 ;
        RECT 20.770 20.005 21.090 20.020 ;
        RECT 20.770 19.960 21.100 20.005 ;
        RECT 24.070 19.960 24.360 20.005 ;
        RECT 20.770 19.820 24.360 19.960 ;
        RECT 20.770 19.775 21.100 19.820 ;
        RECT 24.070 19.775 24.360 19.820 ;
        RECT 20.770 19.760 21.090 19.775 ;
        RECT 26.075 19.620 26.365 19.665 ;
        RECT 17.180 19.480 26.365 19.620 ;
        RECT 26.075 19.435 26.365 19.480 ;
        RECT 28.130 19.620 28.450 19.680 ;
        RECT 29.065 19.620 29.355 19.665 ;
        RECT 28.130 19.480 29.355 19.620 ;
        RECT 28.130 19.420 28.450 19.480 ;
        RECT 29.065 19.435 29.355 19.480 ;
        RECT 18.930 18.600 19.250 18.660 ;
        RECT 20.325 18.600 20.615 18.645 ;
        RECT 21.705 18.600 21.995 18.645 ;
        RECT 18.930 18.460 20.615 18.600 ;
        RECT 18.930 18.400 19.250 18.460 ;
        RECT 20.325 18.415 20.615 18.460 ;
        RECT 20.860 18.460 21.995 18.600 ;
        RECT 20.860 18.260 21.000 18.460 ;
        RECT 21.705 18.415 21.995 18.460 ;
        RECT 26.750 18.260 27.070 18.320 ;
        RECT 19.940 18.120 21.000 18.260 ;
        RECT 21.780 18.120 27.070 18.260 ;
        RECT 19.940 17.965 20.080 18.120 ;
        RECT 21.245 17.970 21.535 18.015 ;
        RECT 21.780 17.970 21.920 18.120 ;
        RECT 19.865 17.735 20.155 17.965 ;
        RECT 20.785 17.735 21.075 17.965 ;
        RECT 21.245 17.830 21.920 17.970 ;
        RECT 24.080 17.965 24.220 18.120 ;
        RECT 26.750 18.060 27.070 18.120 ;
        RECT 21.245 17.785 21.535 17.830 ;
        RECT 22.165 17.735 22.455 17.965 ;
        RECT 22.625 17.735 22.915 17.965 ;
        RECT 23.545 17.735 23.835 17.965 ;
        RECT 24.080 17.780 24.470 17.965 ;
        RECT 24.180 17.735 24.470 17.780 ;
        RECT 27.225 17.735 27.515 17.965 ;
        RECT 28.130 17.920 28.450 17.980 ;
        RECT 27.935 17.780 28.450 17.920 ;
        RECT 20.860 17.240 21.000 17.735 ;
        RECT 22.240 17.300 22.380 17.735 ;
        RECT 20.860 17.100 21.460 17.240 ;
        RECT 21.320 16.900 21.460 17.100 ;
        RECT 22.150 17.040 22.470 17.300 ;
        RECT 22.700 17.240 22.840 17.735 ;
        RECT 23.620 17.580 23.760 17.735 ;
        RECT 24.695 17.580 24.985 17.625 ;
        RECT 23.620 17.440 24.985 17.580 ;
        RECT 27.300 17.580 27.440 17.735 ;
        RECT 28.130 17.720 28.450 17.780 ;
        RECT 31.810 17.580 32.130 17.640 ;
        RECT 27.300 17.440 32.130 17.580 ;
        RECT 24.695 17.395 24.985 17.440 ;
        RECT 31.810 17.380 32.130 17.440 ;
        RECT 23.990 17.240 24.310 17.300 ;
        RECT 27.225 17.240 27.515 17.285 ;
        RECT 22.700 17.100 27.515 17.240 ;
        RECT 23.990 17.040 24.310 17.100 ;
        RECT 27.225 17.055 27.515 17.100 ;
        RECT 23.085 16.900 23.375 16.945 ;
        RECT 21.320 16.760 23.375 16.900 ;
        RECT 23.085 16.715 23.375 16.760 ;
        RECT 23.530 16.900 23.850 16.960 ;
        RECT 31.825 16.900 32.115 16.945 ;
        RECT 23.530 16.760 32.115 16.900 ;
        RECT 23.530 16.700 23.850 16.760 ;
        RECT 31.825 16.715 32.115 16.760 ;
        RECT 16.170 15.880 16.490 15.940 ;
        RECT 17.565 15.880 17.855 15.925 ;
        RECT 16.170 15.740 17.855 15.880 ;
        RECT 16.170 15.680 16.490 15.740 ;
        RECT 17.565 15.695 17.855 15.740 ;
        RECT 22.150 15.880 22.470 15.940 ;
        RECT 24.235 15.880 24.525 15.925 ;
        RECT 22.150 15.740 24.525 15.880 ;
        RECT 22.150 15.680 22.470 15.740 ;
        RECT 24.235 15.695 24.525 15.740 ;
        RECT 26.995 15.880 27.285 15.925 ;
        RECT 28.590 15.880 28.910 15.940 ;
        RECT 31.810 15.880 32.130 15.940 ;
        RECT 26.995 15.740 28.910 15.880 ;
        RECT 31.615 15.740 32.130 15.880 ;
        RECT 26.995 15.695 27.285 15.740 ;
        RECT 28.590 15.680 28.910 15.740 ;
        RECT 31.810 15.680 32.130 15.740 ;
        RECT 23.990 14.905 24.310 14.920 ;
        RECT 21.705 14.860 21.995 14.905 ;
        RECT 23.880 14.860 24.310 14.905 ;
        RECT 21.705 14.720 24.310 14.860 ;
        RECT 21.705 14.675 21.995 14.720 ;
        RECT 23.880 14.675 24.310 14.720 ;
        RECT 26.640 14.860 26.930 14.905 ;
        RECT 28.145 14.860 28.435 14.905 ;
        RECT 28.590 14.860 28.910 14.920 ;
        RECT 26.640 14.720 27.900 14.860 ;
        RECT 26.640 14.675 26.930 14.720 ;
        RECT 23.990 14.660 24.310 14.675 ;
        RECT 27.760 14.520 27.900 14.720 ;
        RECT 28.145 14.720 28.910 14.860 ;
        RECT 28.145 14.675 28.435 14.720 ;
        RECT 28.590 14.660 28.910 14.720 ;
        RECT 30.430 14.860 30.750 14.920 ;
        RECT 32.285 14.860 32.575 14.905 ;
        RECT 30.430 14.720 32.575 14.860 ;
        RECT 30.430 14.660 30.750 14.720 ;
        RECT 32.285 14.675 32.575 14.720 ;
        RECT 32.745 14.675 33.035 14.905 ;
        RECT 31.365 14.520 31.655 14.565 ;
        RECT 31.810 14.520 32.130 14.580 ;
        RECT 32.820 14.520 32.960 14.675 ;
        RECT 27.760 14.380 32.130 14.520 ;
        RECT 31.365 14.335 31.655 14.380 ;
        RECT 31.810 14.320 32.130 14.380 ;
        RECT 32.360 14.380 32.960 14.520 ;
        RECT 32.360 14.240 32.500 14.380 ;
        RECT 20.770 14.180 21.090 14.240 ;
        RECT 22.625 14.180 22.915 14.225 ;
        RECT 20.770 14.040 22.915 14.180 ;
        RECT 20.770 13.980 21.090 14.040 ;
        RECT 22.625 13.995 22.915 14.040 ;
        RECT 27.670 14.180 27.990 14.240 ;
        RECT 30.445 14.180 30.735 14.225 ;
        RECT 27.670 14.040 30.735 14.180 ;
        RECT 27.670 13.980 27.990 14.040 ;
        RECT 30.445 13.995 30.735 14.040 ;
        RECT 32.270 13.980 32.590 14.240 ;
        RECT 29.510 13.160 29.830 13.220 ;
        RECT 30.905 13.160 31.195 13.205 ;
        RECT 31.810 13.160 32.130 13.220 ;
        RECT 29.510 13.020 31.195 13.160 ;
        RECT 31.615 13.020 32.130 13.160 ;
        RECT 29.510 12.960 29.830 13.020 ;
        RECT 30.905 12.975 31.195 13.020 ;
        RECT 31.810 12.960 32.130 13.020 ;
        RECT 19.865 12.820 20.155 12.865 ;
        RECT 21.705 12.820 21.995 12.865 ;
        RECT 19.865 12.680 21.995 12.820 ;
        RECT 19.865 12.635 20.155 12.680 ;
        RECT 21.705 12.635 21.995 12.680 ;
        RECT 22.625 12.820 22.915 12.865 ;
        RECT 23.530 12.820 23.850 12.880 ;
        RECT 25.845 12.820 26.135 12.865 ;
        RECT 22.625 12.680 26.135 12.820 ;
        RECT 22.625 12.635 22.915 12.680 ;
        RECT 20.770 12.480 21.090 12.540 ;
        RECT 20.575 12.340 21.090 12.480 ;
        RECT 21.780 12.480 21.995 12.635 ;
        RECT 23.530 12.620 23.850 12.680 ;
        RECT 25.845 12.635 26.135 12.680 ;
        RECT 29.065 12.820 29.355 12.865 ;
        RECT 29.065 12.680 30.660 12.820 ;
        RECT 29.065 12.635 29.355 12.680 ;
        RECT 30.520 12.540 30.660 12.680 ;
        RECT 24.025 12.480 24.315 12.525 ;
        RECT 21.780 12.340 24.315 12.480 ;
        RECT 20.770 12.280 21.090 12.340 ;
        RECT 24.025 12.295 24.315 12.340 ;
        RECT 28.145 12.480 28.435 12.525 ;
        RECT 28.590 12.480 28.910 12.540 ;
        RECT 29.510 12.480 29.830 12.540 ;
        RECT 30.430 12.480 30.750 12.540 ;
        RECT 28.145 12.340 28.910 12.480 ;
        RECT 29.315 12.340 29.830 12.480 ;
        RECT 30.235 12.340 30.750 12.480 ;
        RECT 28.145 12.295 28.435 12.340 ;
        RECT 28.590 12.280 28.910 12.340 ;
        RECT 29.510 12.280 29.830 12.340 ;
        RECT 30.430 12.280 30.750 12.340 ;
        RECT 31.365 12.295 31.655 12.525 ;
        RECT 18.945 12.140 19.235 12.185 ;
        RECT 19.850 12.140 20.170 12.200 ;
        RECT 18.945 12.000 20.170 12.140 ;
        RECT 31.440 12.140 31.580 12.295 ;
        RECT 32.270 12.140 32.590 12.200 ;
        RECT 31.440 12.000 32.590 12.140 ;
        RECT 18.945 11.955 19.235 12.000 ;
        RECT 19.850 11.940 20.170 12.000 ;
        RECT 32.270 11.940 32.590 12.000 ;
        RECT 19.405 11.800 19.695 11.845 ;
        RECT 21.245 11.800 21.535 11.845 ;
        RECT 24.005 11.800 24.295 11.845 ;
        RECT 19.405 11.660 24.295 11.800 ;
        RECT 19.405 11.615 19.695 11.660 ;
        RECT 21.245 11.615 21.535 11.660 ;
        RECT 24.005 11.615 24.295 11.660 ;
        RECT 29.510 10.440 29.830 10.500 ;
        RECT 32.055 10.440 32.345 10.485 ;
        RECT 29.510 10.300 32.345 10.440 ;
        RECT 29.510 10.240 29.830 10.300 ;
        RECT 32.055 10.255 32.345 10.300 ;
        RECT 22.170 10.100 22.460 10.145 ;
        RECT 24.030 10.100 24.320 10.145 ;
        RECT 26.810 10.100 27.100 10.145 ;
        RECT 22.170 9.960 27.100 10.100 ;
        RECT 22.170 9.915 22.460 9.960 ;
        RECT 24.030 9.915 24.320 9.960 ;
        RECT 26.810 9.915 27.100 9.960 ;
        RECT 16.170 9.420 16.490 9.480 ;
        RECT 19.405 9.420 19.695 9.465 ;
        RECT 21.705 9.420 21.995 9.465 ;
        RECT 23.530 9.420 23.850 9.480 ;
        RECT 31.810 9.465 32.130 9.480 ;
        RECT 26.810 9.420 27.100 9.465 ;
        RECT 16.170 9.280 19.695 9.420 ;
        RECT 16.170 9.220 16.490 9.280 ;
        RECT 19.405 9.235 19.695 9.280 ;
        RECT 19.940 9.280 21.995 9.420 ;
        RECT 23.335 9.280 23.850 9.420 ;
        RECT 19.940 8.800 20.080 9.280 ;
        RECT 21.705 9.235 21.995 9.280 ;
        RECT 23.530 9.220 23.850 9.280 ;
        RECT 24.565 9.280 27.100 9.420 ;
        RECT 24.565 9.125 24.780 9.280 ;
        RECT 26.810 9.235 27.100 9.280 ;
        RECT 30.675 9.420 30.965 9.465 ;
        RECT 31.540 9.420 32.130 9.465 ;
        RECT 30.675 9.280 32.280 9.420 ;
        RECT 30.675 9.235 30.965 9.280 ;
        RECT 31.540 9.235 32.130 9.280 ;
        RECT 31.810 9.220 32.130 9.235 ;
        RECT 22.630 9.080 22.920 9.125 ;
        RECT 24.490 9.080 24.780 9.125 ;
        RECT 25.410 9.080 25.700 9.125 ;
        RECT 28.670 9.080 28.960 9.125 ;
        RECT 22.630 8.940 24.780 9.080 ;
        RECT 22.630 8.895 22.920 8.940 ;
        RECT 24.490 8.895 24.780 8.940 ;
        RECT 25.000 8.940 28.960 9.080 ;
        RECT 19.850 8.740 20.170 8.800 ;
        RECT 19.655 8.600 20.170 8.740 ;
        RECT 19.850 8.540 20.170 8.600 ;
        RECT 20.770 8.740 21.090 8.800 ;
        RECT 23.990 8.740 24.310 8.800 ;
        RECT 25.000 8.740 25.140 8.940 ;
        RECT 25.410 8.895 25.700 8.940 ;
        RECT 28.670 8.895 28.960 8.940 ;
        RECT 20.770 8.600 25.140 8.740 ;
        RECT 20.770 8.540 21.090 8.600 ;
        RECT 23.990 8.540 24.310 8.600 ;
        RECT 20.770 7.720 21.090 7.780 ;
        RECT 18.560 7.580 21.090 7.720 ;
        RECT 9.750 7.380 10.040 7.425 ;
        RECT 11.610 7.380 11.900 7.425 ;
        RECT 9.750 7.240 11.900 7.380 ;
        RECT 9.750 7.195 10.040 7.240 ;
        RECT 11.610 7.195 11.900 7.240 ;
        RECT 12.530 7.380 12.820 7.425 ;
        RECT 15.790 7.380 16.080 7.425 ;
        RECT 18.560 7.380 18.700 7.580 ;
        RECT 20.770 7.520 21.090 7.580 ;
        RECT 23.530 7.720 23.850 7.780 ;
        RECT 27.455 7.720 27.745 7.765 ;
        RECT 32.270 7.720 32.590 7.780 ;
        RECT 23.530 7.580 27.745 7.720 ;
        RECT 32.075 7.580 32.590 7.720 ;
        RECT 23.530 7.520 23.850 7.580 ;
        RECT 27.455 7.535 27.745 7.580 ;
        RECT 32.270 7.520 32.590 7.580 ;
        RECT 12.530 7.240 18.700 7.380 ;
        RECT 19.410 7.380 19.700 7.425 ;
        RECT 21.270 7.380 21.560 7.425 ;
        RECT 19.410 7.240 21.560 7.380 ;
        RECT 12.530 7.195 12.820 7.240 ;
        RECT 15.790 7.195 16.080 7.240 ;
        RECT 19.410 7.195 19.700 7.240 ;
        RECT 21.270 7.195 21.560 7.240 ;
        RECT 22.190 7.380 22.480 7.425 ;
        RECT 23.990 7.380 24.310 7.440 ;
        RECT 25.450 7.380 25.740 7.425 ;
        RECT 22.190 7.240 25.740 7.380 ;
        RECT 22.190 7.195 22.480 7.240 ;
        RECT 11.685 7.040 11.900 7.195 ;
        RECT 13.930 7.040 14.220 7.085 ;
        RECT 11.685 6.900 14.220 7.040 ;
        RECT 13.930 6.855 14.220 6.900 ;
        RECT 17.795 7.040 18.085 7.085 ;
        RECT 20.325 7.040 20.615 7.085 ;
        RECT 17.795 6.900 20.615 7.040 ;
        RECT 21.345 7.040 21.560 7.195 ;
        RECT 23.990 7.180 24.310 7.240 ;
        RECT 25.450 7.195 25.740 7.240 ;
        RECT 31.135 7.380 31.425 7.425 ;
        RECT 31.135 7.240 32.960 7.380 ;
        RECT 31.135 7.195 31.425 7.240 ;
        RECT 23.590 7.040 23.880 7.085 ;
        RECT 21.345 6.900 23.880 7.040 ;
        RECT 17.795 6.855 18.085 6.900 ;
        RECT 20.325 6.855 20.615 6.900 ;
        RECT 23.590 6.855 23.880 6.900 ;
        RECT 28.590 7.040 28.910 7.100 ;
        RECT 30.620 7.040 30.910 7.085 ;
        RECT 31.810 7.040 32.130 7.100 ;
        RECT 32.820 7.085 32.960 7.240 ;
        RECT 28.590 6.900 30.910 7.040 ;
        RECT 31.615 6.900 32.130 7.040 ;
        RECT 28.590 6.840 28.910 6.900 ;
        RECT 30.620 6.855 30.910 6.900 ;
        RECT 31.810 6.840 32.130 6.900 ;
        RECT 32.745 6.855 33.035 7.085 ;
        RECT 6.510 6.700 6.830 6.760 ;
        RECT 8.825 6.700 9.115 6.745 ;
        RECT 10.650 6.700 10.970 6.760 ;
        RECT 6.510 6.560 9.115 6.700 ;
        RECT 10.455 6.560 10.970 6.700 ;
        RECT 6.510 6.500 6.830 6.560 ;
        RECT 8.825 6.515 9.115 6.560 ;
        RECT 10.650 6.500 10.970 6.560 ;
        RECT 16.630 6.700 16.950 6.760 ;
        RECT 18.485 6.700 18.775 6.745 ;
        RECT 19.850 6.700 20.170 6.760 ;
        RECT 16.630 6.560 20.170 6.700 ;
        RECT 16.630 6.500 16.950 6.560 ;
        RECT 18.485 6.515 18.775 6.560 ;
        RECT 19.850 6.500 20.170 6.560 ;
        RECT 9.290 6.360 9.580 6.405 ;
        RECT 11.150 6.360 11.440 6.405 ;
        RECT 13.930 6.360 14.220 6.405 ;
        RECT 9.290 6.220 14.220 6.360 ;
        RECT 9.290 6.175 9.580 6.220 ;
        RECT 11.150 6.175 11.440 6.220 ;
        RECT 13.930 6.175 14.220 6.220 ;
        RECT 18.950 6.360 19.240 6.405 ;
        RECT 20.810 6.360 21.100 6.405 ;
        RECT 23.590 6.360 23.880 6.405 ;
        RECT 18.950 6.220 23.880 6.360 ;
        RECT 18.950 6.175 19.240 6.220 ;
        RECT 20.810 6.175 21.100 6.220 ;
        RECT 23.590 6.175 23.880 6.220 ;
        RECT 10.650 5.000 10.970 5.060 ;
        RECT 15.495 5.000 15.785 5.045 ;
        RECT 10.650 4.860 15.785 5.000 ;
        RECT 10.650 4.800 10.970 4.860 ;
        RECT 15.495 4.815 15.785 4.860 ;
        RECT 6.990 4.660 7.280 4.705 ;
        RECT 8.850 4.660 9.140 4.705 ;
        RECT 11.630 4.660 11.920 4.705 ;
        RECT 6.990 4.520 11.920 4.660 ;
        RECT 6.990 4.475 7.280 4.520 ;
        RECT 8.850 4.475 9.140 4.520 ;
        RECT 11.630 4.475 11.920 4.520 ;
        RECT 17.110 4.660 17.400 4.705 ;
        RECT 18.970 4.660 19.260 4.705 ;
        RECT 21.750 4.660 22.040 4.705 ;
        RECT 17.110 4.520 22.040 4.660 ;
        RECT 17.110 4.475 17.400 4.520 ;
        RECT 18.970 4.475 19.260 4.520 ;
        RECT 21.750 4.475 22.040 4.520 ;
        RECT 6.510 4.320 6.830 4.380 ;
        RECT 16.630 4.320 16.950 4.380 ;
        RECT 6.315 4.180 16.950 4.320 ;
        RECT 6.510 4.120 6.830 4.180 ;
        RECT 16.630 4.120 16.950 4.180 ;
        RECT 18.485 4.320 18.775 4.365 ;
        RECT 27.670 4.320 27.990 4.380 ;
        RECT 18.485 4.180 27.990 4.320 ;
        RECT 18.485 4.135 18.775 4.180 ;
        RECT 27.670 4.120 27.990 4.180 ;
        RECT 8.365 3.980 8.655 4.025 ;
        RECT 11.630 3.980 11.920 4.025 ;
        RECT 18.930 3.980 19.250 4.040 ;
        RECT 21.750 3.980 22.040 4.025 ;
        RECT 7.060 3.840 8.655 3.980 ;
        RECT 7.060 3.300 7.200 3.840 ;
        RECT 8.365 3.795 8.655 3.840 ;
        RECT 9.385 3.840 11.920 3.980 ;
        RECT 9.385 3.685 9.600 3.840 ;
        RECT 11.630 3.795 11.920 3.840 ;
        RECT 13.500 3.840 19.250 3.980 ;
        RECT 13.500 3.685 13.640 3.840 ;
        RECT 18.930 3.780 19.250 3.840 ;
        RECT 19.505 3.840 22.040 3.980 ;
        RECT 19.505 3.685 19.720 3.840 ;
        RECT 21.750 3.795 22.040 3.840 ;
        RECT 7.450 3.640 7.740 3.685 ;
        RECT 9.310 3.640 9.600 3.685 ;
        RECT 7.450 3.500 9.600 3.640 ;
        RECT 7.450 3.455 7.740 3.500 ;
        RECT 9.310 3.455 9.600 3.500 ;
        RECT 10.230 3.640 10.520 3.685 ;
        RECT 13.490 3.640 13.780 3.685 ;
        RECT 10.230 3.500 13.780 3.640 ;
        RECT 10.230 3.455 10.520 3.500 ;
        RECT 13.490 3.455 13.780 3.500 ;
        RECT 17.570 3.640 17.860 3.685 ;
        RECT 19.430 3.640 19.720 3.685 ;
        RECT 17.570 3.500 19.720 3.640 ;
        RECT 17.570 3.455 17.860 3.500 ;
        RECT 19.430 3.455 19.720 3.500 ;
        RECT 20.310 3.685 20.630 3.700 ;
        RECT 20.310 3.640 20.640 3.685 ;
        RECT 23.610 3.640 23.900 3.685 ;
        RECT 20.310 3.500 23.900 3.640 ;
        RECT 20.310 3.455 20.640 3.500 ;
        RECT 23.610 3.455 23.900 3.500 ;
        RECT 20.310 3.440 20.630 3.455 ;
        RECT 25.615 3.300 25.905 3.345 ;
        RECT 7.060 3.160 25.905 3.300 ;
        RECT 25.615 3.115 25.905 3.160 ;
      LAYER via ;
        RECT 17.580 36.420 17.840 36.680 ;
        RECT 19.880 36.420 20.140 36.680 ;
        RECT 16.660 35.740 16.920 36.000 ;
        RECT 24.020 36.420 24.280 36.680 ;
        RECT 28.620 37.100 28.880 37.360 ;
        RECT 26.780 36.420 27.040 36.680 ;
        RECT 29.080 36.420 29.340 36.680 ;
        RECT 28.620 36.080 28.880 36.340 ;
        RECT 30.920 36.420 31.180 36.680 ;
        RECT 32.300 36.420 32.560 36.680 ;
        RECT 23.560 35.740 23.820 36.000 ;
        RECT 24.940 35.740 25.200 36.000 ;
        RECT 25.400 35.740 25.660 36.000 ;
        RECT 31.840 35.740 32.100 36.000 ;
        RECT 16.660 34.720 16.920 34.980 ;
        RECT 17.580 34.720 17.840 34.980 ;
        RECT 18.960 34.720 19.220 34.980 ;
        RECT 24.020 34.720 24.280 34.980 ;
        RECT 24.940 34.720 25.200 34.980 ;
        RECT 29.080 34.720 29.340 34.980 ;
        RECT 17.580 34.040 17.840 34.300 ;
        RECT 19.880 34.040 20.140 34.300 ;
        RECT 30.460 34.040 30.720 34.300 ;
        RECT 31.380 34.040 31.640 34.300 ;
        RECT 32.300 32.000 32.560 32.260 ;
        RECT 23.560 31.660 23.820 31.920 ;
        RECT 17.580 30.980 17.840 31.240 ;
        RECT 18.960 30.980 19.220 31.240 ;
        RECT 32.300 30.980 32.560 31.240 ;
        RECT 26.780 30.640 27.040 30.900 ;
        RECT 16.200 28.600 16.460 28.860 ;
        RECT 32.300 28.940 32.560 29.200 ;
        RECT 30.920 28.600 31.180 28.860 ;
        RECT 31.840 28.600 32.100 28.860 ;
        RECT 18.500 27.580 18.760 27.840 ;
        RECT 14.820 25.880 15.080 26.140 ;
        RECT 6.540 25.540 6.800 25.800 ;
        RECT 25.400 25.540 25.660 25.800 ;
        RECT 12.980 25.200 13.240 25.460 ;
        RECT 12.520 24.860 12.780 25.120 ;
        RECT 12.980 23.840 13.240 24.100 ;
        RECT 18.960 23.840 19.220 24.100 ;
        RECT 6.540 23.160 6.800 23.420 ;
        RECT 12.520 22.820 12.780 23.080 ;
        RECT 18.500 23.160 18.760 23.420 ;
        RECT 26.780 23.840 27.040 24.100 ;
        RECT 31.380 23.840 31.640 24.100 ;
        RECT 24.020 23.500 24.280 23.760 ;
        RECT 30.920 23.160 31.180 23.420 ;
        RECT 31.840 23.160 32.100 23.420 ;
        RECT 30.460 22.480 30.720 22.740 ;
        RECT 12.980 21.120 13.240 21.380 ;
        RECT 20.800 21.120 21.060 21.380 ;
        RECT 24.020 21.120 24.280 21.380 ;
        RECT 6.540 20.100 6.800 20.360 ;
        RECT 14.820 20.100 15.080 20.360 ;
        RECT 18.500 20.440 18.760 20.700 ;
        RECT 12.980 19.760 13.240 20.020 ;
        RECT 18.960 20.100 19.220 20.360 ;
        RECT 28.620 20.100 28.880 20.360 ;
        RECT 29.540 20.100 29.800 20.360 ;
        RECT 20.800 19.760 21.060 20.020 ;
        RECT 28.160 19.420 28.420 19.680 ;
        RECT 18.960 18.400 19.220 18.660 ;
        RECT 26.780 18.060 27.040 18.320 ;
        RECT 22.180 17.040 22.440 17.300 ;
        RECT 28.160 17.720 28.420 17.980 ;
        RECT 31.840 17.380 32.100 17.640 ;
        RECT 24.020 17.040 24.280 17.300 ;
        RECT 23.560 16.700 23.820 16.960 ;
        RECT 16.200 15.680 16.460 15.940 ;
        RECT 22.180 15.680 22.440 15.940 ;
        RECT 28.620 15.680 28.880 15.940 ;
        RECT 31.840 15.680 32.100 15.940 ;
        RECT 24.020 14.660 24.280 14.920 ;
        RECT 28.620 14.660 28.880 14.920 ;
        RECT 30.460 14.660 30.720 14.920 ;
        RECT 31.840 14.320 32.100 14.580 ;
        RECT 20.800 13.980 21.060 14.240 ;
        RECT 27.700 13.980 27.960 14.240 ;
        RECT 32.300 13.980 32.560 14.240 ;
        RECT 29.540 12.960 29.800 13.220 ;
        RECT 31.840 12.960 32.100 13.220 ;
        RECT 20.800 12.280 21.060 12.540 ;
        RECT 23.560 12.620 23.820 12.880 ;
        RECT 28.620 12.280 28.880 12.540 ;
        RECT 29.540 12.280 29.800 12.540 ;
        RECT 30.460 12.280 30.720 12.540 ;
        RECT 19.880 11.940 20.140 12.200 ;
        RECT 32.300 11.940 32.560 12.200 ;
        RECT 29.540 10.240 29.800 10.500 ;
        RECT 16.200 9.220 16.460 9.480 ;
        RECT 23.560 9.220 23.820 9.480 ;
        RECT 31.840 9.220 32.100 9.480 ;
        RECT 19.880 8.540 20.140 8.800 ;
        RECT 20.800 8.540 21.060 8.800 ;
        RECT 24.020 8.540 24.280 8.800 ;
        RECT 20.800 7.520 21.060 7.780 ;
        RECT 23.560 7.520 23.820 7.780 ;
        RECT 32.300 7.520 32.560 7.780 ;
        RECT 24.020 7.180 24.280 7.440 ;
        RECT 28.620 6.840 28.880 7.100 ;
        RECT 31.840 6.840 32.100 7.100 ;
        RECT 6.540 6.500 6.800 6.760 ;
        RECT 10.680 6.500 10.940 6.760 ;
        RECT 16.660 6.500 16.920 6.760 ;
        RECT 19.880 6.500 20.140 6.760 ;
        RECT 10.680 4.800 10.940 5.060 ;
        RECT 6.540 4.120 6.800 4.380 ;
        RECT 16.660 4.120 16.920 4.380 ;
        RECT 27.700 4.120 27.960 4.380 ;
        RECT 18.960 3.780 19.220 4.040 ;
        RECT 20.340 3.440 20.600 3.700 ;
      LAYER met2 ;
        RECT 28.620 37.070 28.880 37.390 ;
        RECT 17.580 36.390 17.840 36.710 ;
        RECT 19.880 36.390 20.140 36.710 ;
        RECT 24.020 36.390 24.280 36.710 ;
        RECT 26.780 36.390 27.040 36.710 ;
        RECT 16.660 35.710 16.920 36.030 ;
        RECT 16.720 35.010 16.860 35.710 ;
        RECT 17.640 35.010 17.780 36.390 ;
        RECT 16.660 34.690 16.920 35.010 ;
        RECT 17.580 34.690 17.840 35.010 ;
        RECT 18.960 34.690 19.220 35.010 ;
        RECT 17.580 34.010 17.840 34.330 ;
        RECT 17.640 31.270 17.780 34.010 ;
        RECT 19.020 31.270 19.160 34.690 ;
        RECT 19.940 34.330 20.080 36.390 ;
        RECT 23.560 35.710 23.820 36.030 ;
        RECT 19.880 34.010 20.140 34.330 ;
        RECT 23.620 31.950 23.760 35.710 ;
        RECT 24.080 35.010 24.220 36.390 ;
        RECT 24.940 35.710 25.200 36.030 ;
        RECT 25.400 35.710 25.660 36.030 ;
        RECT 25.000 35.010 25.140 35.710 ;
        RECT 24.020 34.690 24.280 35.010 ;
        RECT 24.940 34.690 25.200 35.010 ;
        RECT 23.560 31.630 23.820 31.950 ;
        RECT 17.580 30.950 17.840 31.270 ;
        RECT 18.960 30.950 19.220 31.270 ;
        RECT 16.200 28.570 16.460 28.890 ;
        RECT 14.820 25.850 15.080 26.170 ;
        RECT 6.540 25.510 6.800 25.830 ;
        RECT 6.600 23.450 6.740 25.510 ;
        RECT 12.980 25.170 13.240 25.490 ;
        RECT 12.520 24.830 12.780 25.150 ;
        RECT 6.540 23.130 6.800 23.450 ;
        RECT 6.600 20.390 6.740 23.130 ;
        RECT 12.580 23.110 12.720 24.830 ;
        RECT 13.040 24.130 13.180 25.170 ;
        RECT 12.980 23.810 13.240 24.130 ;
        RECT 12.520 22.790 12.780 23.110 ;
        RECT 13.040 21.410 13.180 23.810 ;
        RECT 12.980 21.090 13.240 21.410 ;
        RECT 6.540 20.070 6.800 20.390 ;
        RECT 13.040 20.050 13.180 21.090 ;
        RECT 14.880 20.390 15.020 25.850 ;
        RECT 14.820 20.070 15.080 20.390 ;
        RECT 12.980 19.730 13.240 20.050 ;
        RECT 16.260 15.970 16.400 28.570 ;
        RECT 18.500 27.550 18.760 27.870 ;
        RECT 18.560 23.450 18.700 27.550 ;
        RECT 19.020 24.130 19.160 30.950 ;
        RECT 25.460 25.830 25.600 35.710 ;
        RECT 26.840 30.930 26.980 36.390 ;
        RECT 28.680 36.370 28.820 37.070 ;
        RECT 29.080 36.390 29.340 36.710 ;
        RECT 30.920 36.390 31.180 36.710 ;
        RECT 32.300 36.390 32.560 36.710 ;
        RECT 28.620 36.050 28.880 36.370 ;
        RECT 29.140 35.010 29.280 36.390 ;
        RECT 29.080 34.690 29.340 35.010 ;
        RECT 30.460 34.010 30.720 34.330 ;
        RECT 26.780 30.610 27.040 30.930 ;
        RECT 25.400 25.510 25.660 25.830 ;
        RECT 26.840 24.130 26.980 30.610 ;
        RECT 18.960 23.810 19.220 24.130 ;
        RECT 26.780 23.810 27.040 24.130 ;
        RECT 24.020 23.470 24.280 23.790 ;
        RECT 18.500 23.130 18.760 23.450 ;
        RECT 18.560 20.730 18.700 23.130 ;
        RECT 24.080 21.410 24.220 23.470 ;
        RECT 20.800 21.090 21.060 21.410 ;
        RECT 24.020 21.090 24.280 21.410 ;
        RECT 18.500 20.410 18.760 20.730 ;
        RECT 18.960 20.070 19.220 20.390 ;
        RECT 19.020 18.690 19.160 20.070 ;
        RECT 20.860 20.050 21.000 21.090 ;
        RECT 20.800 19.730 21.060 20.050 ;
        RECT 18.960 18.370 19.220 18.690 ;
        RECT 24.080 18.090 24.220 21.090 ;
        RECT 26.840 18.350 26.980 23.810 ;
        RECT 30.520 22.770 30.660 34.010 ;
        RECT 30.980 28.890 31.120 36.390 ;
        RECT 31.840 35.710 32.100 36.030 ;
        RECT 31.380 34.010 31.640 34.330 ;
        RECT 30.920 28.570 31.180 28.890 ;
        RECT 30.980 23.450 31.120 28.570 ;
        RECT 31.440 24.130 31.580 34.010 ;
        RECT 31.900 28.890 32.040 35.710 ;
        RECT 32.360 32.290 32.500 36.390 ;
        RECT 32.300 31.970 32.560 32.290 ;
        RECT 32.300 30.950 32.560 31.270 ;
        RECT 32.360 29.230 32.500 30.950 ;
        RECT 32.300 28.910 32.560 29.230 ;
        RECT 31.840 28.570 32.100 28.890 ;
        RECT 31.380 23.810 31.640 24.130 ;
        RECT 31.900 23.450 32.040 28.570 ;
        RECT 30.920 23.130 31.180 23.450 ;
        RECT 31.840 23.130 32.100 23.450 ;
        RECT 30.460 22.450 30.720 22.770 ;
        RECT 28.620 20.070 28.880 20.390 ;
        RECT 29.540 20.070 29.800 20.390 ;
        RECT 28.160 19.390 28.420 19.710 ;
        RECT 23.620 17.950 24.220 18.090 ;
        RECT 26.780 18.030 27.040 18.350 ;
        RECT 28.220 18.010 28.360 19.390 ;
        RECT 22.180 17.010 22.440 17.330 ;
        RECT 22.240 15.970 22.380 17.010 ;
        RECT 23.620 16.990 23.760 17.950 ;
        RECT 28.160 17.690 28.420 18.010 ;
        RECT 24.020 17.010 24.280 17.330 ;
        RECT 23.560 16.670 23.820 16.990 ;
        RECT 16.200 15.650 16.460 15.970 ;
        RECT 22.180 15.650 22.440 15.970 ;
        RECT 16.260 9.510 16.400 15.650 ;
        RECT 20.800 13.950 21.060 14.270 ;
        RECT 20.860 12.570 21.000 13.950 ;
        RECT 23.620 12.910 23.760 16.670 ;
        RECT 24.080 14.950 24.220 17.010 ;
        RECT 28.680 15.970 28.820 20.070 ;
        RECT 28.620 15.650 28.880 15.970 ;
        RECT 24.020 14.630 24.280 14.950 ;
        RECT 28.620 14.630 28.880 14.950 ;
        RECT 27.700 13.950 27.960 14.270 ;
        RECT 23.560 12.590 23.820 12.910 ;
        RECT 20.800 12.250 21.060 12.570 ;
        RECT 19.880 11.910 20.140 12.230 ;
        RECT 16.200 9.190 16.460 9.510 ;
        RECT 19.940 8.830 20.080 11.910 ;
        RECT 23.620 9.930 23.760 12.590 ;
        RECT 23.620 9.790 24.220 9.930 ;
        RECT 23.560 9.190 23.820 9.510 ;
        RECT 19.880 8.510 20.140 8.830 ;
        RECT 20.800 8.510 21.060 8.830 ;
        RECT 19.940 6.790 20.080 8.510 ;
        RECT 20.860 7.810 21.000 8.510 ;
        RECT 23.620 7.810 23.760 9.190 ;
        RECT 24.080 8.830 24.220 9.790 ;
        RECT 24.020 8.510 24.280 8.830 ;
        RECT 20.800 7.490 21.060 7.810 ;
        RECT 23.560 7.490 23.820 7.810 ;
        RECT 6.540 6.470 6.800 6.790 ;
        RECT 10.680 6.470 10.940 6.790 ;
        RECT 16.660 6.470 16.920 6.790 ;
        RECT 19.880 6.470 20.140 6.790 ;
        RECT 6.600 4.410 6.740 6.470 ;
        RECT 10.740 5.090 10.880 6.470 ;
        RECT 10.680 4.770 10.940 5.090 ;
        RECT 16.720 4.410 16.860 6.470 ;
        RECT 6.540 4.090 6.800 4.410 ;
        RECT 16.660 4.090 16.920 4.410 ;
        RECT 18.960 3.810 19.220 4.070 ;
        RECT 20.860 3.810 21.000 7.490 ;
        RECT 24.080 7.470 24.220 8.510 ;
        RECT 24.020 7.150 24.280 7.470 ;
        RECT 27.760 4.410 27.900 13.950 ;
        RECT 28.680 12.570 28.820 14.630 ;
        RECT 29.600 13.250 29.740 20.070 ;
        RECT 31.840 17.350 32.100 17.670 ;
        RECT 31.900 15.970 32.040 17.350 ;
        RECT 31.840 15.650 32.100 15.970 ;
        RECT 30.460 14.630 30.720 14.950 ;
        RECT 29.540 12.930 29.800 13.250 ;
        RECT 30.520 12.570 30.660 14.630 ;
        RECT 31.840 14.290 32.100 14.610 ;
        RECT 31.900 13.250 32.040 14.290 ;
        RECT 32.300 13.950 32.560 14.270 ;
        RECT 31.840 12.930 32.100 13.250 ;
        RECT 28.620 12.250 28.880 12.570 ;
        RECT 29.540 12.250 29.800 12.570 ;
        RECT 30.460 12.250 30.720 12.570 ;
        RECT 28.680 7.130 28.820 12.250 ;
        RECT 29.600 10.530 29.740 12.250 ;
        RECT 32.360 12.230 32.500 13.950 ;
        RECT 32.300 11.910 32.560 12.230 ;
        RECT 29.540 10.210 29.800 10.530 ;
        RECT 31.840 9.190 32.100 9.510 ;
        RECT 31.900 7.130 32.040 9.190 ;
        RECT 32.360 7.810 32.500 11.910 ;
        RECT 32.300 7.490 32.560 7.810 ;
        RECT 28.620 6.810 28.880 7.130 ;
        RECT 31.840 6.810 32.100 7.130 ;
        RECT 27.700 4.090 27.960 4.410 ;
        RECT 18.960 3.750 21.000 3.810 ;
        RECT 19.020 3.670 21.000 3.750 ;
        RECT 20.340 3.410 20.600 3.670 ;
  END
END NON_CLK_GEN
END LIBRARY
